VERSION 5.8 ;
BUSBITCHARS "[]" ;
DIVIDERCHAR "/" ;
UNITS
    DATABASE MICRONS 1000 ;
END UNITS

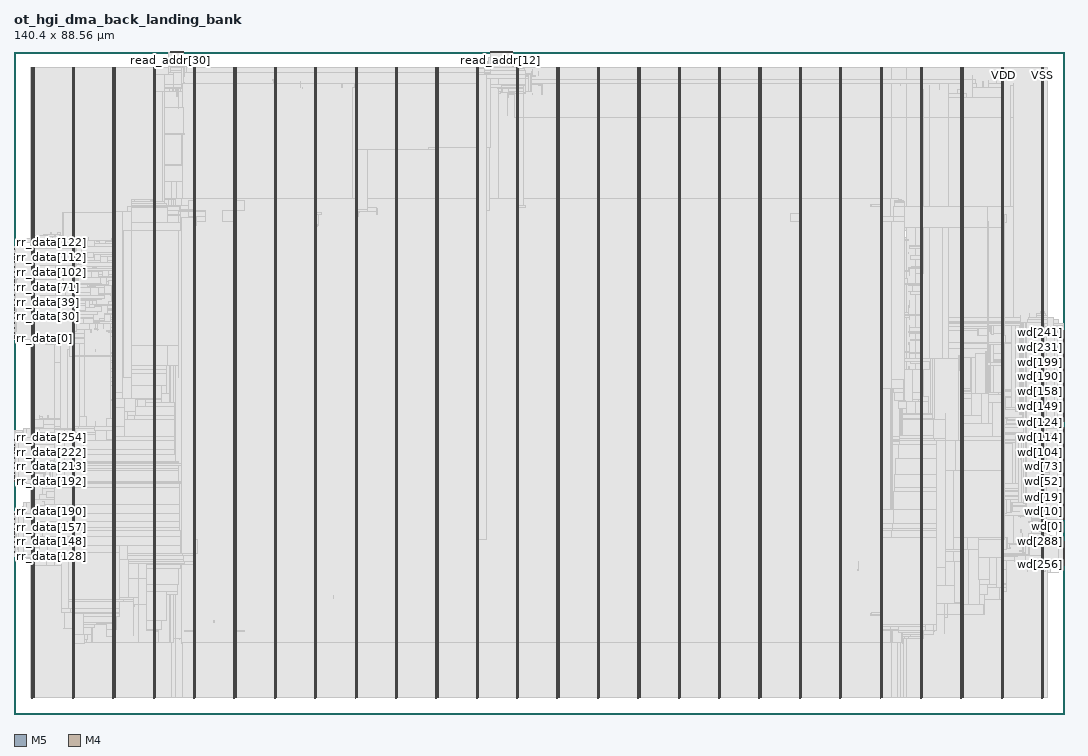
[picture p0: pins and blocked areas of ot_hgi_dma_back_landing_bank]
MACRO ot_hgi_dma_back_landing_bank
  FOREIGN ot_hgi_dma_back_landing_bank 0 0 ;
  CLASS BLOCK ;
  SIZE 140.4 BY 88.56 ;
  PIN clk
    DIRECTION INPUT ;
    USE SIGNAL ;
    PORT
      LAYER M5 ;
        RECT  63.696 88.476 63.72 88.56 ;
    END
  END clk
  PIN output_en
    DIRECTION INPUT ;
    USE SIGNAL ;
    PORT
      LAYER M5 ;
        RECT  63.792 88.476 63.816 88.56 ;
    END
  END output_en
  PIN read_addr[0]
    DIRECTION INPUT ;
    USE SIGNAL ;
    PORT
      LAYER M5 ;
        RECT  63.888 88.476 63.912 88.56 ;
    END
  END read_addr[0]
  PIN read_addr[10]
    DIRECTION INPUT ;
    USE SIGNAL ;
    PORT
      LAYER M5 ;
        RECT  64.848 88.476 64.872 88.56 ;
    END
  END read_addr[10]
  PIN read_addr[11]
    DIRECTION INPUT ;
    USE SIGNAL ;
    PORT
      LAYER M5 ;
        RECT  64.944 88.476 64.968 88.56 ;
    END
  END read_addr[11]
  PIN read_addr[12]
    DIRECTION INPUT ;
    USE SIGNAL ;
    PORT
      LAYER M5 ;
        RECT  65.04 88.476 65.064 88.56 ;
    END
  END read_addr[12]
  PIN read_addr[13]
    DIRECTION INPUT ;
    USE SIGNAL ;
    PORT
      LAYER M5 ;
        RECT  65.136 88.476 65.16 88.56 ;
    END
  END read_addr[13]
  PIN read_addr[14]
    DIRECTION INPUT ;
    USE SIGNAL ;
    PORT
      LAYER M5 ;
        RECT  65.232 88.476 65.256 88.56 ;
    END
  END read_addr[14]
  PIN read_addr[15]
    DIRECTION INPUT ;
    USE SIGNAL ;
    PORT
      LAYER M5 ;
        RECT  65.328 88.476 65.352 88.56 ;
    END
  END read_addr[15]
  PIN read_addr[16]
    DIRECTION INPUT ;
    USE SIGNAL ;
    PORT
      LAYER M5 ;
        RECT  65.424 88.476 65.448 88.56 ;
    END
  END read_addr[16]
  PIN read_addr[17]
    DIRECTION INPUT ;
    USE SIGNAL ;
    PORT
      LAYER M5 ;
        RECT  65.52 88.476 65.544 88.56 ;
    END
  END read_addr[17]
  PIN read_addr[18]
    DIRECTION INPUT ;
    USE SIGNAL ;
    PORT
      LAYER M5 ;
        RECT  65.616 88.476 65.64 88.56 ;
    END
  END read_addr[18]
  PIN read_addr[19]
    DIRECTION INPUT ;
    USE SIGNAL ;
    PORT
      LAYER M5 ;
        RECT  65.712 88.476 65.736 88.56 ;
    END
  END read_addr[19]
  PIN read_addr[1]
    DIRECTION INPUT ;
    USE SIGNAL ;
    PORT
      LAYER M5 ;
        RECT  63.984 88.476 64.008 88.56 ;
    END
  END read_addr[1]
  PIN read_addr[20]
    DIRECTION INPUT ;
    USE SIGNAL ;
    PORT
      LAYER M5 ;
        RECT  65.808 88.476 65.832 88.56 ;
    END
  END read_addr[20]
  PIN read_addr[21]
    DIRECTION INPUT ;
    USE SIGNAL ;
    PORT
      LAYER M5 ;
        RECT  65.904 88.476 65.928 88.56 ;
    END
  END read_addr[21]
  PIN read_addr[22]
    DIRECTION INPUT ;
    USE SIGNAL ;
    PORT
      LAYER M5 ;
        RECT  66 88.476 66.024 88.56 ;
    END
  END read_addr[22]
  PIN read_addr[23]
    DIRECTION INPUT ;
    USE SIGNAL ;
    PORT
      LAYER M5 ;
        RECT  66.096 88.476 66.12 88.56 ;
    END
  END read_addr[23]
  PIN read_addr[24]
    DIRECTION INPUT ;
    USE SIGNAL ;
    PORT
      LAYER M5 ;
        RECT  66.192 88.476 66.216 88.56 ;
    END
  END read_addr[24]
  PIN read_addr[25]
    DIRECTION INPUT ;
    USE SIGNAL ;
    PORT
      LAYER M5 ;
        RECT  66.288 88.476 66.312 88.56 ;
    END
  END read_addr[25]
  PIN read_addr[26]
    DIRECTION INPUT ;
    USE SIGNAL ;
    PORT
      LAYER M5 ;
        RECT  66.384 88.476 66.408 88.56 ;
    END
  END read_addr[26]
  PIN read_addr[27]
    DIRECTION INPUT ;
    USE SIGNAL ;
    PORT
      LAYER M5 ;
        RECT  66.48 88.476 66.504 88.56 ;
    END
  END read_addr[27]
  PIN read_addr[28]
    DIRECTION INPUT ;
    USE SIGNAL ;
    PORT
      LAYER M5 ;
        RECT  66.576 88.476 66.6 88.56 ;
    END
  END read_addr[28]
  PIN read_addr[29]
    DIRECTION INPUT ;
    USE SIGNAL ;
    PORT
      LAYER M5 ;
        RECT  66.672 88.476 66.696 88.56 ;
    END
  END read_addr[29]
  PIN read_addr[2]
    DIRECTION INPUT ;
    USE SIGNAL ;
    PORT
      LAYER M5 ;
        RECT  64.08 88.476 64.104 88.56 ;
    END
  END read_addr[2]
  PIN read_addr[30]
    DIRECTION INPUT ;
    USE SIGNAL ;
    PORT
      LAYER M5 ;
        RECT  20.88 88.476 20.904 88.56 ;
    END
  END read_addr[30]
  PIN read_addr[31]
    DIRECTION INPUT ;
    USE SIGNAL ;
    PORT
      LAYER M5 ;
        RECT  20.976 88.476 21 88.56 ;
    END
  END read_addr[31]
  PIN read_addr[3]
    DIRECTION INPUT ;
    USE SIGNAL ;
    PORT
      LAYER M5 ;
        RECT  64.176 88.476 64.2 88.56 ;
    END
  END read_addr[3]
  PIN read_addr[4]
    DIRECTION INPUT ;
    USE SIGNAL ;
    PORT
      LAYER M5 ;
        RECT  64.272 88.476 64.296 88.56 ;
    END
  END read_addr[4]
  PIN read_addr[5]
    DIRECTION INPUT ;
    USE SIGNAL ;
    PORT
      LAYER M5 ;
        RECT  64.368 88.476 64.392 88.56 ;
    END
  END read_addr[5]
  PIN read_addr[6]
    DIRECTION INPUT ;
    USE SIGNAL ;
    PORT
      LAYER M5 ;
        RECT  64.464 88.476 64.488 88.56 ;
    END
  END read_addr[6]
  PIN read_addr[7]
    DIRECTION INPUT ;
    USE SIGNAL ;
    PORT
      LAYER M5 ;
        RECT  64.56 88.476 64.584 88.56 ;
    END
  END read_addr[7]
  PIN read_addr[8]
    DIRECTION INPUT ;
    USE SIGNAL ;
    PORT
      LAYER M5 ;
        RECT  64.656 88.476 64.68 88.56 ;
    END
  END read_addr[8]
  PIN read_addr[9]
    DIRECTION INPUT ;
    USE SIGNAL ;
    PORT
      LAYER M5 ;
        RECT  64.752 88.476 64.776 88.56 ;
    END
  END read_addr[9]
  PIN read_en
    DIRECTION INPUT ;
    USE SIGNAL ;
    PORT
      LAYER M5 ;
        RECT  21.072 88.476 21.096 88.56 ;
    END
  END read_en
  PIN read_slot[0]
    DIRECTION INPUT ;
    USE SIGNAL ;
    PORT
      LAYER M5 ;
        RECT  21.168 88.476 21.192 88.56 ;
    END
  END read_slot[0]
  PIN read_slot[1]
    DIRECTION INPUT ;
    USE SIGNAL ;
    PORT
      LAYER M5 ;
        RECT  21.264 88.476 21.288 88.56 ;
    END
  END read_slot[1]
  PIN read_slot[2]
    DIRECTION INPUT ;
    USE SIGNAL ;
    PORT
      LAYER M5 ;
        RECT  21.36 88.476 21.384 88.56 ;
    END
  END read_slot[2]
  PIN read_slot[3]
    DIRECTION INPUT ;
    USE SIGNAL ;
    PORT
      LAYER M5 ;
        RECT  21.456 88.476 21.48 88.56 ;
    END
  END read_slot[3]
  PIN read_slot[4]
    DIRECTION INPUT ;
    USE SIGNAL ;
    PORT
      LAYER M5 ;
        RECT  21.552 88.476 21.576 88.56 ;
    END
  END read_slot[4]
  PIN read_slot[5]
    DIRECTION INPUT ;
    USE SIGNAL ;
    PORT
      LAYER M5 ;
        RECT  21.648 88.476 21.672 88.56 ;
    END
  END read_slot[5]
  PIN read_slot[6]
    DIRECTION INPUT ;
    USE SIGNAL ;
    PORT
      LAYER M5 ;
        RECT  21.744 88.476 21.768 88.56 ;
    END
  END read_slot[6]
  PIN rr_data[0]
    DIRECTION INPUT ;
    USE SIGNAL ;
    PORT
      LAYER M4 ;
        RECT  0 50.256 0.084 50.28 ;
    END
  END rr_data[0]
  PIN rr_data[100]
    DIRECTION INPUT ;
    USE SIGNAL ;
    PORT
      LAYER M4 ;
        RECT  0 59.856 0.084 59.88 ;
    END
  END rr_data[100]
  PIN rr_data[101]
    DIRECTION INPUT ;
    USE SIGNAL ;
    PORT
      LAYER M4 ;
        RECT  0 59.952 0.084 59.976 ;
    END
  END rr_data[101]
  PIN rr_data[102]
    DIRECTION INPUT ;
    USE SIGNAL ;
    PORT
      LAYER M4 ;
        RECT  0 60.048 0.084 60.072 ;
    END
  END rr_data[102]
  PIN rr_data[103]
    DIRECTION INPUT ;
    USE SIGNAL ;
    PORT
      LAYER M4 ;
        RECT  0 60.144 0.084 60.168 ;
    END
  END rr_data[103]
  PIN rr_data[104]
    DIRECTION INPUT ;
    USE SIGNAL ;
    PORT
      LAYER M4 ;
        RECT  0 60.24 0.084 60.264 ;
    END
  END rr_data[104]
  PIN rr_data[105]
    DIRECTION INPUT ;
    USE SIGNAL ;
    PORT
      LAYER M4 ;
        RECT  0 60.336 0.084 60.36 ;
    END
  END rr_data[105]
  PIN rr_data[106]
    DIRECTION INPUT ;
    USE SIGNAL ;
    PORT
      LAYER M4 ;
        RECT  0 60.432 0.084 60.456 ;
    END
  END rr_data[106]
  PIN rr_data[107]
    DIRECTION INPUT ;
    USE SIGNAL ;
    PORT
      LAYER M4 ;
        RECT  0 60.528 0.084 60.552 ;
    END
  END rr_data[107]
  PIN rr_data[108]
    DIRECTION INPUT ;
    USE SIGNAL ;
    PORT
      LAYER M4 ;
        RECT  0 60.624 0.084 60.648 ;
    END
  END rr_data[108]
  PIN rr_data[109]
    DIRECTION INPUT ;
    USE SIGNAL ;
    PORT
      LAYER M4 ;
        RECT  0 60.72 0.084 60.744 ;
    END
  END rr_data[109]
  PIN rr_data[10]
    DIRECTION INPUT ;
    USE SIGNAL ;
    PORT
      LAYER M4 ;
        RECT  0 51.216 0.084 51.24 ;
    END
  END rr_data[10]
  PIN rr_data[110]
    DIRECTION INPUT ;
    USE SIGNAL ;
    PORT
      LAYER M4 ;
        RECT  0 60.816 0.084 60.84 ;
    END
  END rr_data[110]
  PIN rr_data[111]
    DIRECTION INPUT ;
    USE SIGNAL ;
    PORT
      LAYER M4 ;
        RECT  0 60.912 0.084 60.936 ;
    END
  END rr_data[111]
  PIN rr_data[112]
    DIRECTION INPUT ;
    USE SIGNAL ;
    PORT
      LAYER M4 ;
        RECT  0 61.008 0.084 61.032 ;
    END
  END rr_data[112]
  PIN rr_data[113]
    DIRECTION INPUT ;
    USE SIGNAL ;
    PORT
      LAYER M4 ;
        RECT  0 61.104 0.084 61.128 ;
    END
  END rr_data[113]
  PIN rr_data[114]
    DIRECTION INPUT ;
    USE SIGNAL ;
    PORT
      LAYER M4 ;
        RECT  0 61.2 0.084 61.224 ;
    END
  END rr_data[114]
  PIN rr_data[115]
    DIRECTION INPUT ;
    USE SIGNAL ;
    PORT
      LAYER M4 ;
        RECT  0 61.296 0.084 61.32 ;
    END
  END rr_data[115]
  PIN rr_data[116]
    DIRECTION INPUT ;
    USE SIGNAL ;
    PORT
      LAYER M4 ;
        RECT  0 61.392 0.084 61.416 ;
    END
  END rr_data[116]
  PIN rr_data[117]
    DIRECTION INPUT ;
    USE SIGNAL ;
    PORT
      LAYER M4 ;
        RECT  0 61.488 0.084 61.512 ;
    END
  END rr_data[117]
  PIN rr_data[118]
    DIRECTION INPUT ;
    USE SIGNAL ;
    PORT
      LAYER M4 ;
        RECT  0 61.584 0.084 61.608 ;
    END
  END rr_data[118]
  PIN rr_data[119]
    DIRECTION INPUT ;
    USE SIGNAL ;
    PORT
      LAYER M4 ;
        RECT  0 61.68 0.084 61.704 ;
    END
  END rr_data[119]
  PIN rr_data[11]
    DIRECTION INPUT ;
    USE SIGNAL ;
    PORT
      LAYER M4 ;
        RECT  0 51.312 0.084 51.336 ;
    END
  END rr_data[11]
  PIN rr_data[120]
    DIRECTION INPUT ;
    USE SIGNAL ;
    PORT
      LAYER M4 ;
        RECT  0 61.776 0.084 61.8 ;
    END
  END rr_data[120]
  PIN rr_data[121]
    DIRECTION INPUT ;
    USE SIGNAL ;
    PORT
      LAYER M4 ;
        RECT  0 61.872 0.084 61.896 ;
    END
  END rr_data[121]
  PIN rr_data[122]
    DIRECTION INPUT ;
    USE SIGNAL ;
    PORT
      LAYER M4 ;
        RECT  0 61.968 0.084 61.992 ;
    END
  END rr_data[122]
  PIN rr_data[123]
    DIRECTION INPUT ;
    USE SIGNAL ;
    PORT
      LAYER M4 ;
        RECT  0 62.064 0.084 62.088 ;
    END
  END rr_data[123]
  PIN rr_data[124]
    DIRECTION INPUT ;
    USE SIGNAL ;
    PORT
      LAYER M4 ;
        RECT  0 62.16 0.084 62.184 ;
    END
  END rr_data[124]
  PIN rr_data[125]
    DIRECTION INPUT ;
    USE SIGNAL ;
    PORT
      LAYER M4 ;
        RECT  0 62.256 0.084 62.28 ;
    END
  END rr_data[125]
  PIN rr_data[126]
    DIRECTION INPUT ;
    USE SIGNAL ;
    PORT
      LAYER M4 ;
        RECT  0 62.352 0.084 62.376 ;
    END
  END rr_data[126]
  PIN rr_data[127]
    DIRECTION INPUT ;
    USE SIGNAL ;
    PORT
      LAYER M4 ;
        RECT  0 62.448 0.084 62.472 ;
    END
  END rr_data[127]
  PIN rr_data[128]
    DIRECTION INPUT ;
    USE SIGNAL ;
    PORT
      LAYER M4 ;
        RECT  0 21.072 0.084 21.096 ;
    END
  END rr_data[128]
  PIN rr_data[129]
    DIRECTION INPUT ;
    USE SIGNAL ;
    PORT
      LAYER M4 ;
        RECT  0 21.168 0.084 21.192 ;
    END
  END rr_data[129]
  PIN rr_data[12]
    DIRECTION INPUT ;
    USE SIGNAL ;
    PORT
      LAYER M4 ;
        RECT  0 51.408 0.084 51.432 ;
    END
  END rr_data[12]
  PIN rr_data[130]
    DIRECTION INPUT ;
    USE SIGNAL ;
    PORT
      LAYER M4 ;
        RECT  0 21.264 0.084 21.288 ;
    END
  END rr_data[130]
  PIN rr_data[131]
    DIRECTION INPUT ;
    USE SIGNAL ;
    PORT
      LAYER M4 ;
        RECT  0 21.36 0.084 21.384 ;
    END
  END rr_data[131]
  PIN rr_data[132]
    DIRECTION INPUT ;
    USE SIGNAL ;
    PORT
      LAYER M4 ;
        RECT  0 21.456 0.084 21.48 ;
    END
  END rr_data[132]
  PIN rr_data[133]
    DIRECTION INPUT ;
    USE SIGNAL ;
    PORT
      LAYER M4 ;
        RECT  0 21.552 0.084 21.576 ;
    END
  END rr_data[133]
  PIN rr_data[134]
    DIRECTION INPUT ;
    USE SIGNAL ;
    PORT
      LAYER M4 ;
        RECT  0 21.648 0.084 21.672 ;
    END
  END rr_data[134]
  PIN rr_data[135]
    DIRECTION INPUT ;
    USE SIGNAL ;
    PORT
      LAYER M4 ;
        RECT  0 21.744 0.084 21.768 ;
    END
  END rr_data[135]
  PIN rr_data[136]
    DIRECTION INPUT ;
    USE SIGNAL ;
    PORT
      LAYER M4 ;
        RECT  0 21.84 0.084 21.864 ;
    END
  END rr_data[136]
  PIN rr_data[137]
    DIRECTION INPUT ;
    USE SIGNAL ;
    PORT
      LAYER M4 ;
        RECT  0 21.936 0.084 21.96 ;
    END
  END rr_data[137]
  PIN rr_data[138]
    DIRECTION INPUT ;
    USE SIGNAL ;
    PORT
      LAYER M4 ;
        RECT  0 22.032 0.084 22.056 ;
    END
  END rr_data[138]
  PIN rr_data[139]
    DIRECTION INPUT ;
    USE SIGNAL ;
    PORT
      LAYER M4 ;
        RECT  0 22.128 0.084 22.152 ;
    END
  END rr_data[139]
  PIN rr_data[13]
    DIRECTION INPUT ;
    USE SIGNAL ;
    PORT
      LAYER M4 ;
        RECT  0 51.504 0.084 51.528 ;
    END
  END rr_data[13]
  PIN rr_data[140]
    DIRECTION INPUT ;
    USE SIGNAL ;
    PORT
      LAYER M4 ;
        RECT  0 22.224 0.084 22.248 ;
    END
  END rr_data[140]
  PIN rr_data[141]
    DIRECTION INPUT ;
    USE SIGNAL ;
    PORT
      LAYER M4 ;
        RECT  0 22.32 0.084 22.344 ;
    END
  END rr_data[141]
  PIN rr_data[142]
    DIRECTION INPUT ;
    USE SIGNAL ;
    PORT
      LAYER M4 ;
        RECT  0 22.416 0.084 22.44 ;
    END
  END rr_data[142]
  PIN rr_data[143]
    DIRECTION INPUT ;
    USE SIGNAL ;
    PORT
      LAYER M4 ;
        RECT  0 22.512 0.084 22.536 ;
    END
  END rr_data[143]
  PIN rr_data[144]
    DIRECTION INPUT ;
    USE SIGNAL ;
    PORT
      LAYER M4 ;
        RECT  0 22.608 0.084 22.632 ;
    END
  END rr_data[144]
  PIN rr_data[145]
    DIRECTION INPUT ;
    USE SIGNAL ;
    PORT
      LAYER M4 ;
        RECT  0 22.704 0.084 22.728 ;
    END
  END rr_data[145]
  PIN rr_data[146]
    DIRECTION INPUT ;
    USE SIGNAL ;
    PORT
      LAYER M4 ;
        RECT  0 22.8 0.084 22.824 ;
    END
  END rr_data[146]
  PIN rr_data[147]
    DIRECTION INPUT ;
    USE SIGNAL ;
    PORT
      LAYER M4 ;
        RECT  0 22.896 0.084 22.92 ;
    END
  END rr_data[147]
  PIN rr_data[148]
    DIRECTION INPUT ;
    USE SIGNAL ;
    PORT
      LAYER M4 ;
        RECT  0 22.992 0.084 23.016 ;
    END
  END rr_data[148]
  PIN rr_data[149]
    DIRECTION INPUT ;
    USE SIGNAL ;
    PORT
      LAYER M4 ;
        RECT  0 23.088 0.084 23.112 ;
    END
  END rr_data[149]
  PIN rr_data[14]
    DIRECTION INPUT ;
    USE SIGNAL ;
    PORT
      LAYER M4 ;
        RECT  0 51.6 0.084 51.624 ;
    END
  END rr_data[14]
  PIN rr_data[150]
    DIRECTION INPUT ;
    USE SIGNAL ;
    PORT
      LAYER M4 ;
        RECT  0 23.184 0.084 23.208 ;
    END
  END rr_data[150]
  PIN rr_data[151]
    DIRECTION INPUT ;
    USE SIGNAL ;
    PORT
      LAYER M4 ;
        RECT  0 23.28 0.084 23.304 ;
    END
  END rr_data[151]
  PIN rr_data[152]
    DIRECTION INPUT ;
    USE SIGNAL ;
    PORT
      LAYER M4 ;
        RECT  0 23.376 0.084 23.4 ;
    END
  END rr_data[152]
  PIN rr_data[153]
    DIRECTION INPUT ;
    USE SIGNAL ;
    PORT
      LAYER M4 ;
        RECT  0 23.472 0.084 23.496 ;
    END
  END rr_data[153]
  PIN rr_data[154]
    DIRECTION INPUT ;
    USE SIGNAL ;
    PORT
      LAYER M4 ;
        RECT  0 23.568 0.084 23.592 ;
    END
  END rr_data[154]
  PIN rr_data[155]
    DIRECTION INPUT ;
    USE SIGNAL ;
    PORT
      LAYER M4 ;
        RECT  0 23.664 0.084 23.688 ;
    END
  END rr_data[155]
  PIN rr_data[156]
    DIRECTION INPUT ;
    USE SIGNAL ;
    PORT
      LAYER M4 ;
        RECT  0 23.76 0.084 23.784 ;
    END
  END rr_data[156]
  PIN rr_data[157]
    DIRECTION INPUT ;
    USE SIGNAL ;
    PORT
      LAYER M4 ;
        RECT  0 23.856 0.084 23.88 ;
    END
  END rr_data[157]
  PIN rr_data[158]
    DIRECTION INPUT ;
    USE SIGNAL ;
    PORT
      LAYER M4 ;
        RECT  0 23.952 0.084 23.976 ;
    END
  END rr_data[158]
  PIN rr_data[159]
    DIRECTION INPUT ;
    USE SIGNAL ;
    PORT
      LAYER M4 ;
        RECT  0 24.048 0.084 24.072 ;
    END
  END rr_data[159]
  PIN rr_data[15]
    DIRECTION INPUT ;
    USE SIGNAL ;
    PORT
      LAYER M4 ;
        RECT  0 51.696 0.084 51.72 ;
    END
  END rr_data[15]
  PIN rr_data[160]
    DIRECTION INPUT ;
    USE SIGNAL ;
    PORT
      LAYER M4 ;
        RECT  0 24.144 0.084 24.168 ;
    END
  END rr_data[160]
  PIN rr_data[161]
    DIRECTION INPUT ;
    USE SIGNAL ;
    PORT
      LAYER M4 ;
        RECT  0 24.24 0.084 24.264 ;
    END
  END rr_data[161]
  PIN rr_data[162]
    DIRECTION INPUT ;
    USE SIGNAL ;
    PORT
      LAYER M4 ;
        RECT  0 24.336 0.084 24.36 ;
    END
  END rr_data[162]
  PIN rr_data[163]
    DIRECTION INPUT ;
    USE SIGNAL ;
    PORT
      LAYER M4 ;
        RECT  0 24.432 0.084 24.456 ;
    END
  END rr_data[163]
  PIN rr_data[164]
    DIRECTION INPUT ;
    USE SIGNAL ;
    PORT
      LAYER M4 ;
        RECT  0 24.528 0.084 24.552 ;
    END
  END rr_data[164]
  PIN rr_data[165]
    DIRECTION INPUT ;
    USE SIGNAL ;
    PORT
      LAYER M4 ;
        RECT  0 24.624 0.084 24.648 ;
    END
  END rr_data[165]
  PIN rr_data[166]
    DIRECTION INPUT ;
    USE SIGNAL ;
    PORT
      LAYER M4 ;
        RECT  0 24.72 0.084 24.744 ;
    END
  END rr_data[166]
  PIN rr_data[167]
    DIRECTION INPUT ;
    USE SIGNAL ;
    PORT
      LAYER M4 ;
        RECT  0 24.816 0.084 24.84 ;
    END
  END rr_data[167]
  PIN rr_data[168]
    DIRECTION INPUT ;
    USE SIGNAL ;
    PORT
      LAYER M4 ;
        RECT  0 24.912 0.084 24.936 ;
    END
  END rr_data[168]
  PIN rr_data[169]
    DIRECTION INPUT ;
    USE SIGNAL ;
    PORT
      LAYER M4 ;
        RECT  0 25.008 0.084 25.032 ;
    END
  END rr_data[169]
  PIN rr_data[16]
    DIRECTION INPUT ;
    USE SIGNAL ;
    PORT
      LAYER M4 ;
        RECT  0 51.792 0.084 51.816 ;
    END
  END rr_data[16]
  PIN rr_data[170]
    DIRECTION INPUT ;
    USE SIGNAL ;
    PORT
      LAYER M4 ;
        RECT  0 25.104 0.084 25.128 ;
    END
  END rr_data[170]
  PIN rr_data[171]
    DIRECTION INPUT ;
    USE SIGNAL ;
    PORT
      LAYER M4 ;
        RECT  0 25.2 0.084 25.224 ;
    END
  END rr_data[171]
  PIN rr_data[172]
    DIRECTION INPUT ;
    USE SIGNAL ;
    PORT
      LAYER M4 ;
        RECT  0 25.296 0.084 25.32 ;
    END
  END rr_data[172]
  PIN rr_data[173]
    DIRECTION INPUT ;
    USE SIGNAL ;
    PORT
      LAYER M4 ;
        RECT  0 25.392 0.084 25.416 ;
    END
  END rr_data[173]
  PIN rr_data[174]
    DIRECTION INPUT ;
    USE SIGNAL ;
    PORT
      LAYER M4 ;
        RECT  0 25.488 0.084 25.512 ;
    END
  END rr_data[174]
  PIN rr_data[175]
    DIRECTION INPUT ;
    USE SIGNAL ;
    PORT
      LAYER M4 ;
        RECT  0 25.584 0.084 25.608 ;
    END
  END rr_data[175]
  PIN rr_data[176]
    DIRECTION INPUT ;
    USE SIGNAL ;
    PORT
      LAYER M4 ;
        RECT  0 25.68 0.084 25.704 ;
    END
  END rr_data[176]
  PIN rr_data[177]
    DIRECTION INPUT ;
    USE SIGNAL ;
    PORT
      LAYER M4 ;
        RECT  0 25.776 0.084 25.8 ;
    END
  END rr_data[177]
  PIN rr_data[178]
    DIRECTION INPUT ;
    USE SIGNAL ;
    PORT
      LAYER M4 ;
        RECT  0 25.872 0.084 25.896 ;
    END
  END rr_data[178]
  PIN rr_data[179]
    DIRECTION INPUT ;
    USE SIGNAL ;
    PORT
      LAYER M4 ;
        RECT  0 25.968 0.084 25.992 ;
    END
  END rr_data[179]
  PIN rr_data[17]
    DIRECTION INPUT ;
    USE SIGNAL ;
    PORT
      LAYER M4 ;
        RECT  0 51.888 0.084 51.912 ;
    END
  END rr_data[17]
  PIN rr_data[180]
    DIRECTION INPUT ;
    USE SIGNAL ;
    PORT
      LAYER M4 ;
        RECT  0 26.064 0.084 26.088 ;
    END
  END rr_data[180]
  PIN rr_data[181]
    DIRECTION INPUT ;
    USE SIGNAL ;
    PORT
      LAYER M4 ;
        RECT  0 26.16 0.084 26.184 ;
    END
  END rr_data[181]
  PIN rr_data[182]
    DIRECTION INPUT ;
    USE SIGNAL ;
    PORT
      LAYER M4 ;
        RECT  0 26.256 0.084 26.28 ;
    END
  END rr_data[182]
  PIN rr_data[183]
    DIRECTION INPUT ;
    USE SIGNAL ;
    PORT
      LAYER M4 ;
        RECT  0 26.352 0.084 26.376 ;
    END
  END rr_data[183]
  PIN rr_data[184]
    DIRECTION INPUT ;
    USE SIGNAL ;
    PORT
      LAYER M4 ;
        RECT  0 26.448 0.084 26.472 ;
    END
  END rr_data[184]
  PIN rr_data[185]
    DIRECTION INPUT ;
    USE SIGNAL ;
    PORT
      LAYER M4 ;
        RECT  0 26.544 0.084 26.568 ;
    END
  END rr_data[185]
  PIN rr_data[186]
    DIRECTION INPUT ;
    USE SIGNAL ;
    PORT
      LAYER M4 ;
        RECT  0 26.64 0.084 26.664 ;
    END
  END rr_data[186]
  PIN rr_data[187]
    DIRECTION INPUT ;
    USE SIGNAL ;
    PORT
      LAYER M4 ;
        RECT  0 26.736 0.084 26.76 ;
    END
  END rr_data[187]
  PIN rr_data[188]
    DIRECTION INPUT ;
    USE SIGNAL ;
    PORT
      LAYER M4 ;
        RECT  0 26.832 0.084 26.856 ;
    END
  END rr_data[188]
  PIN rr_data[189]
    DIRECTION INPUT ;
    USE SIGNAL ;
    PORT
      LAYER M4 ;
        RECT  0 26.928 0.084 26.952 ;
    END
  END rr_data[189]
  PIN rr_data[18]
    DIRECTION INPUT ;
    USE SIGNAL ;
    PORT
      LAYER M4 ;
        RECT  0 51.984 0.084 52.008 ;
    END
  END rr_data[18]
  PIN rr_data[190]
    DIRECTION INPUT ;
    USE SIGNAL ;
    PORT
      LAYER M4 ;
        RECT  0 27.024 0.084 27.048 ;
    END
  END rr_data[190]
  PIN rr_data[191]
    DIRECTION INPUT ;
    USE SIGNAL ;
    PORT
      LAYER M4 ;
        RECT  0 27.12 0.084 27.144 ;
    END
  END rr_data[191]
  PIN rr_data[192]
    DIRECTION INPUT ;
    USE SIGNAL ;
    PORT
      LAYER M4 ;
        RECT  0 31.056 0.084 31.08 ;
    END
  END rr_data[192]
  PIN rr_data[193]
    DIRECTION INPUT ;
    USE SIGNAL ;
    PORT
      LAYER M4 ;
        RECT  0 31.152 0.084 31.176 ;
    END
  END rr_data[193]
  PIN rr_data[194]
    DIRECTION INPUT ;
    USE SIGNAL ;
    PORT
      LAYER M4 ;
        RECT  0 31.248 0.084 31.272 ;
    END
  END rr_data[194]
  PIN rr_data[195]
    DIRECTION INPUT ;
    USE SIGNAL ;
    PORT
      LAYER M4 ;
        RECT  0 31.344 0.084 31.368 ;
    END
  END rr_data[195]
  PIN rr_data[196]
    DIRECTION INPUT ;
    USE SIGNAL ;
    PORT
      LAYER M4 ;
        RECT  0 31.44 0.084 31.464 ;
    END
  END rr_data[196]
  PIN rr_data[197]
    DIRECTION INPUT ;
    USE SIGNAL ;
    PORT
      LAYER M4 ;
        RECT  0 31.536 0.084 31.56 ;
    END
  END rr_data[197]
  PIN rr_data[198]
    DIRECTION INPUT ;
    USE SIGNAL ;
    PORT
      LAYER M4 ;
        RECT  0 31.632 0.084 31.656 ;
    END
  END rr_data[198]
  PIN rr_data[199]
    DIRECTION INPUT ;
    USE SIGNAL ;
    PORT
      LAYER M4 ;
        RECT  0 31.728 0.084 31.752 ;
    END
  END rr_data[199]
  PIN rr_data[19]
    DIRECTION INPUT ;
    USE SIGNAL ;
    PORT
      LAYER M4 ;
        RECT  0 52.08 0.084 52.104 ;
    END
  END rr_data[19]
  PIN rr_data[1]
    DIRECTION INPUT ;
    USE SIGNAL ;
    PORT
      LAYER M4 ;
        RECT  0 50.352 0.084 50.376 ;
    END
  END rr_data[1]
  PIN rr_data[200]
    DIRECTION INPUT ;
    USE SIGNAL ;
    PORT
      LAYER M4 ;
        RECT  0 31.824 0.084 31.848 ;
    END
  END rr_data[200]
  PIN rr_data[201]
    DIRECTION INPUT ;
    USE SIGNAL ;
    PORT
      LAYER M4 ;
        RECT  0 31.92 0.084 31.944 ;
    END
  END rr_data[201]
  PIN rr_data[202]
    DIRECTION INPUT ;
    USE SIGNAL ;
    PORT
      LAYER M4 ;
        RECT  0 32.016 0.084 32.04 ;
    END
  END rr_data[202]
  PIN rr_data[203]
    DIRECTION INPUT ;
    USE SIGNAL ;
    PORT
      LAYER M4 ;
        RECT  0 32.112 0.084 32.136 ;
    END
  END rr_data[203]
  PIN rr_data[204]
    DIRECTION INPUT ;
    USE SIGNAL ;
    PORT
      LAYER M4 ;
        RECT  0 32.208 0.084 32.232 ;
    END
  END rr_data[204]
  PIN rr_data[205]
    DIRECTION INPUT ;
    USE SIGNAL ;
    PORT
      LAYER M4 ;
        RECT  0 32.304 0.084 32.328 ;
    END
  END rr_data[205]
  PIN rr_data[206]
    DIRECTION INPUT ;
    USE SIGNAL ;
    PORT
      LAYER M4 ;
        RECT  0 32.4 0.084 32.424 ;
    END
  END rr_data[206]
  PIN rr_data[207]
    DIRECTION INPUT ;
    USE SIGNAL ;
    PORT
      LAYER M4 ;
        RECT  0 32.496 0.084 32.52 ;
    END
  END rr_data[207]
  PIN rr_data[208]
    DIRECTION INPUT ;
    USE SIGNAL ;
    PORT
      LAYER M4 ;
        RECT  0 32.592 0.084 32.616 ;
    END
  END rr_data[208]
  PIN rr_data[209]
    DIRECTION INPUT ;
    USE SIGNAL ;
    PORT
      LAYER M4 ;
        RECT  0 32.688 0.084 32.712 ;
    END
  END rr_data[209]
  PIN rr_data[20]
    DIRECTION INPUT ;
    USE SIGNAL ;
    PORT
      LAYER M4 ;
        RECT  0 52.176 0.084 52.2 ;
    END
  END rr_data[20]
  PIN rr_data[210]
    DIRECTION INPUT ;
    USE SIGNAL ;
    PORT
      LAYER M4 ;
        RECT  0 32.784 0.084 32.808 ;
    END
  END rr_data[210]
  PIN rr_data[211]
    DIRECTION INPUT ;
    USE SIGNAL ;
    PORT
      LAYER M4 ;
        RECT  0 32.88 0.084 32.904 ;
    END
  END rr_data[211]
  PIN rr_data[212]
    DIRECTION INPUT ;
    USE SIGNAL ;
    PORT
      LAYER M4 ;
        RECT  0 32.976 0.084 33 ;
    END
  END rr_data[212]
  PIN rr_data[213]
    DIRECTION INPUT ;
    USE SIGNAL ;
    PORT
      LAYER M4 ;
        RECT  0 33.072 0.084 33.096 ;
    END
  END rr_data[213]
  PIN rr_data[214]
    DIRECTION INPUT ;
    USE SIGNAL ;
    PORT
      LAYER M4 ;
        RECT  0 33.168 0.084 33.192 ;
    END
  END rr_data[214]
  PIN rr_data[215]
    DIRECTION INPUT ;
    USE SIGNAL ;
    PORT
      LAYER M4 ;
        RECT  0 33.264 0.084 33.288 ;
    END
  END rr_data[215]
  PIN rr_data[216]
    DIRECTION INPUT ;
    USE SIGNAL ;
    PORT
      LAYER M4 ;
        RECT  0 33.36 0.084 33.384 ;
    END
  END rr_data[216]
  PIN rr_data[217]
    DIRECTION INPUT ;
    USE SIGNAL ;
    PORT
      LAYER M4 ;
        RECT  0 33.456 0.084 33.48 ;
    END
  END rr_data[217]
  PIN rr_data[218]
    DIRECTION INPUT ;
    USE SIGNAL ;
    PORT
      LAYER M4 ;
        RECT  0 33.552 0.084 33.576 ;
    END
  END rr_data[218]
  PIN rr_data[219]
    DIRECTION INPUT ;
    USE SIGNAL ;
    PORT
      LAYER M4 ;
        RECT  0 33.648 0.084 33.672 ;
    END
  END rr_data[219]
  PIN rr_data[21]
    DIRECTION INPUT ;
    USE SIGNAL ;
    PORT
      LAYER M4 ;
        RECT  0 52.272 0.084 52.296 ;
    END
  END rr_data[21]
  PIN rr_data[220]
    DIRECTION INPUT ;
    USE SIGNAL ;
    PORT
      LAYER M4 ;
        RECT  0 33.744 0.084 33.768 ;
    END
  END rr_data[220]
  PIN rr_data[221]
    DIRECTION INPUT ;
    USE SIGNAL ;
    PORT
      LAYER M4 ;
        RECT  0 33.84 0.084 33.864 ;
    END
  END rr_data[221]
  PIN rr_data[222]
    DIRECTION INPUT ;
    USE SIGNAL ;
    PORT
      LAYER M4 ;
        RECT  0 33.936 0.084 33.96 ;
    END
  END rr_data[222]
  PIN rr_data[223]
    DIRECTION INPUT ;
    USE SIGNAL ;
    PORT
      LAYER M4 ;
        RECT  0 34.032 0.084 34.056 ;
    END
  END rr_data[223]
  PIN rr_data[224]
    DIRECTION INPUT ;
    USE SIGNAL ;
    PORT
      LAYER M4 ;
        RECT  0 34.128 0.084 34.152 ;
    END
  END rr_data[224]
  PIN rr_data[225]
    DIRECTION INPUT ;
    USE SIGNAL ;
    PORT
      LAYER M4 ;
        RECT  0 34.224 0.084 34.248 ;
    END
  END rr_data[225]
  PIN rr_data[226]
    DIRECTION INPUT ;
    USE SIGNAL ;
    PORT
      LAYER M4 ;
        RECT  0 34.32 0.084 34.344 ;
    END
  END rr_data[226]
  PIN rr_data[227]
    DIRECTION INPUT ;
    USE SIGNAL ;
    PORT
      LAYER M4 ;
        RECT  0 34.416 0.084 34.44 ;
    END
  END rr_data[227]
  PIN rr_data[228]
    DIRECTION INPUT ;
    USE SIGNAL ;
    PORT
      LAYER M4 ;
        RECT  0 34.512 0.084 34.536 ;
    END
  END rr_data[228]
  PIN rr_data[229]
    DIRECTION INPUT ;
    USE SIGNAL ;
    PORT
      LAYER M4 ;
        RECT  0 34.608 0.084 34.632 ;
    END
  END rr_data[229]
  PIN rr_data[22]
    DIRECTION INPUT ;
    USE SIGNAL ;
    PORT
      LAYER M4 ;
        RECT  0 52.368 0.084 52.392 ;
    END
  END rr_data[22]
  PIN rr_data[230]
    DIRECTION INPUT ;
    USE SIGNAL ;
    PORT
      LAYER M4 ;
        RECT  0 34.704 0.084 34.728 ;
    END
  END rr_data[230]
  PIN rr_data[231]
    DIRECTION INPUT ;
    USE SIGNAL ;
    PORT
      LAYER M4 ;
        RECT  0 34.8 0.084 34.824 ;
    END
  END rr_data[231]
  PIN rr_data[232]
    DIRECTION INPUT ;
    USE SIGNAL ;
    PORT
      LAYER M4 ;
        RECT  0 34.896 0.084 34.92 ;
    END
  END rr_data[232]
  PIN rr_data[233]
    DIRECTION INPUT ;
    USE SIGNAL ;
    PORT
      LAYER M4 ;
        RECT  0 34.992 0.084 35.016 ;
    END
  END rr_data[233]
  PIN rr_data[234]
    DIRECTION INPUT ;
    USE SIGNAL ;
    PORT
      LAYER M4 ;
        RECT  0 35.088 0.084 35.112 ;
    END
  END rr_data[234]
  PIN rr_data[235]
    DIRECTION INPUT ;
    USE SIGNAL ;
    PORT
      LAYER M4 ;
        RECT  0 35.184 0.084 35.208 ;
    END
  END rr_data[235]
  PIN rr_data[236]
    DIRECTION INPUT ;
    USE SIGNAL ;
    PORT
      LAYER M4 ;
        RECT  0 35.28 0.084 35.304 ;
    END
  END rr_data[236]
  PIN rr_data[237]
    DIRECTION INPUT ;
    USE SIGNAL ;
    PORT
      LAYER M4 ;
        RECT  0 35.376 0.084 35.4 ;
    END
  END rr_data[237]
  PIN rr_data[238]
    DIRECTION INPUT ;
    USE SIGNAL ;
    PORT
      LAYER M4 ;
        RECT  0 35.472 0.084 35.496 ;
    END
  END rr_data[238]
  PIN rr_data[239]
    DIRECTION INPUT ;
    USE SIGNAL ;
    PORT
      LAYER M4 ;
        RECT  0 35.568 0.084 35.592 ;
    END
  END rr_data[239]
  PIN rr_data[23]
    DIRECTION INPUT ;
    USE SIGNAL ;
    PORT
      LAYER M4 ;
        RECT  0 52.464 0.084 52.488 ;
    END
  END rr_data[23]
  PIN rr_data[240]
    DIRECTION INPUT ;
    USE SIGNAL ;
    PORT
      LAYER M4 ;
        RECT  0 35.664 0.084 35.688 ;
    END
  END rr_data[240]
  PIN rr_data[241]
    DIRECTION INPUT ;
    USE SIGNAL ;
    PORT
      LAYER M4 ;
        RECT  0 35.76 0.084 35.784 ;
    END
  END rr_data[241]
  PIN rr_data[242]
    DIRECTION INPUT ;
    USE SIGNAL ;
    PORT
      LAYER M4 ;
        RECT  0 35.856 0.084 35.88 ;
    END
  END rr_data[242]
  PIN rr_data[243]
    DIRECTION INPUT ;
    USE SIGNAL ;
    PORT
      LAYER M4 ;
        RECT  0 35.952 0.084 35.976 ;
    END
  END rr_data[243]
  PIN rr_data[244]
    DIRECTION INPUT ;
    USE SIGNAL ;
    PORT
      LAYER M4 ;
        RECT  0 36.048 0.084 36.072 ;
    END
  END rr_data[244]
  PIN rr_data[245]
    DIRECTION INPUT ;
    USE SIGNAL ;
    PORT
      LAYER M4 ;
        RECT  0 36.144 0.084 36.168 ;
    END
  END rr_data[245]
  PIN rr_data[246]
    DIRECTION INPUT ;
    USE SIGNAL ;
    PORT
      LAYER M4 ;
        RECT  0 36.24 0.084 36.264 ;
    END
  END rr_data[246]
  PIN rr_data[247]
    DIRECTION INPUT ;
    USE SIGNAL ;
    PORT
      LAYER M4 ;
        RECT  0 36.336 0.084 36.36 ;
    END
  END rr_data[247]
  PIN rr_data[248]
    DIRECTION INPUT ;
    USE SIGNAL ;
    PORT
      LAYER M4 ;
        RECT  0 36.432 0.084 36.456 ;
    END
  END rr_data[248]
  PIN rr_data[249]
    DIRECTION INPUT ;
    USE SIGNAL ;
    PORT
      LAYER M4 ;
        RECT  0 36.528 0.084 36.552 ;
    END
  END rr_data[249]
  PIN rr_data[24]
    DIRECTION INPUT ;
    USE SIGNAL ;
    PORT
      LAYER M4 ;
        RECT  0 52.56 0.084 52.584 ;
    END
  END rr_data[24]
  PIN rr_data[250]
    DIRECTION INPUT ;
    USE SIGNAL ;
    PORT
      LAYER M4 ;
        RECT  0 36.624 0.084 36.648 ;
    END
  END rr_data[250]
  PIN rr_data[251]
    DIRECTION INPUT ;
    USE SIGNAL ;
    PORT
      LAYER M4 ;
        RECT  0 36.72 0.084 36.744 ;
    END
  END rr_data[251]
  PIN rr_data[252]
    DIRECTION INPUT ;
    USE SIGNAL ;
    PORT
      LAYER M4 ;
        RECT  0 36.816 0.084 36.84 ;
    END
  END rr_data[252]
  PIN rr_data[253]
    DIRECTION INPUT ;
    USE SIGNAL ;
    PORT
      LAYER M4 ;
        RECT  0 36.912 0.084 36.936 ;
    END
  END rr_data[253]
  PIN rr_data[254]
    DIRECTION INPUT ;
    USE SIGNAL ;
    PORT
      LAYER M4 ;
        RECT  0 37.008 0.084 37.032 ;
    END
  END rr_data[254]
  PIN rr_data[255]
    DIRECTION INPUT ;
    USE SIGNAL ;
    PORT
      LAYER M4 ;
        RECT  0 37.104 0.084 37.128 ;
    END
  END rr_data[255]
  PIN rr_data[25]
    DIRECTION INPUT ;
    USE SIGNAL ;
    PORT
      LAYER M4 ;
        RECT  0 52.656 0.084 52.68 ;
    END
  END rr_data[25]
  PIN rr_data[26]
    DIRECTION INPUT ;
    USE SIGNAL ;
    PORT
      LAYER M4 ;
        RECT  0 52.752 0.084 52.776 ;
    END
  END rr_data[26]
  PIN rr_data[27]
    DIRECTION INPUT ;
    USE SIGNAL ;
    PORT
      LAYER M4 ;
        RECT  0 52.848 0.084 52.872 ;
    END
  END rr_data[27]
  PIN rr_data[28]
    DIRECTION INPUT ;
    USE SIGNAL ;
    PORT
      LAYER M4 ;
        RECT  0 52.944 0.084 52.968 ;
    END
  END rr_data[28]
  PIN rr_data[29]
    DIRECTION INPUT ;
    USE SIGNAL ;
    PORT
      LAYER M4 ;
        RECT  0 53.04 0.084 53.064 ;
    END
  END rr_data[29]
  PIN rr_data[2]
    DIRECTION INPUT ;
    USE SIGNAL ;
    PORT
      LAYER M4 ;
        RECT  0 50.448 0.084 50.472 ;
    END
  END rr_data[2]
  PIN rr_data[30]
    DIRECTION INPUT ;
    USE SIGNAL ;
    PORT
      LAYER M4 ;
        RECT  0 53.136 0.084 53.16 ;
    END
  END rr_data[30]
  PIN rr_data[31]
    DIRECTION INPUT ;
    USE SIGNAL ;
    PORT
      LAYER M4 ;
        RECT  0 53.232 0.084 53.256 ;
    END
  END rr_data[31]
  PIN rr_data[32]
    DIRECTION INPUT ;
    USE SIGNAL ;
    PORT
      LAYER M4 ;
        RECT  0 53.328 0.084 53.352 ;
    END
  END rr_data[32]
  PIN rr_data[33]
    DIRECTION INPUT ;
    USE SIGNAL ;
    PORT
      LAYER M4 ;
        RECT  0 53.424 0.084 53.448 ;
    END
  END rr_data[33]
  PIN rr_data[34]
    DIRECTION INPUT ;
    USE SIGNAL ;
    PORT
      LAYER M4 ;
        RECT  0 53.52 0.084 53.544 ;
    END
  END rr_data[34]
  PIN rr_data[35]
    DIRECTION INPUT ;
    USE SIGNAL ;
    PORT
      LAYER M4 ;
        RECT  0 53.616 0.084 53.64 ;
    END
  END rr_data[35]
  PIN rr_data[36]
    DIRECTION INPUT ;
    USE SIGNAL ;
    PORT
      LAYER M4 ;
        RECT  0 53.712 0.084 53.736 ;
    END
  END rr_data[36]
  PIN rr_data[37]
    DIRECTION INPUT ;
    USE SIGNAL ;
    PORT
      LAYER M4 ;
        RECT  0 53.808 0.084 53.832 ;
    END
  END rr_data[37]
  PIN rr_data[38]
    DIRECTION INPUT ;
    USE SIGNAL ;
    PORT
      LAYER M4 ;
        RECT  0 53.904 0.084 53.928 ;
    END
  END rr_data[38]
  PIN rr_data[39]
    DIRECTION INPUT ;
    USE SIGNAL ;
    PORT
      LAYER M4 ;
        RECT  0 54 0.084 54.024 ;
    END
  END rr_data[39]
  PIN rr_data[3]
    DIRECTION INPUT ;
    USE SIGNAL ;
    PORT
      LAYER M4 ;
        RECT  0 50.544 0.084 50.568 ;
    END
  END rr_data[3]
  PIN rr_data[40]
    DIRECTION INPUT ;
    USE SIGNAL ;
    PORT
      LAYER M4 ;
        RECT  0 54.096 0.084 54.12 ;
    END
  END rr_data[40]
  PIN rr_data[41]
    DIRECTION INPUT ;
    USE SIGNAL ;
    PORT
      LAYER M4 ;
        RECT  0 54.192 0.084 54.216 ;
    END
  END rr_data[41]
  PIN rr_data[42]
    DIRECTION INPUT ;
    USE SIGNAL ;
    PORT
      LAYER M4 ;
        RECT  0 54.288 0.084 54.312 ;
    END
  END rr_data[42]
  PIN rr_data[43]
    DIRECTION INPUT ;
    USE SIGNAL ;
    PORT
      LAYER M4 ;
        RECT  0 54.384 0.084 54.408 ;
    END
  END rr_data[43]
  PIN rr_data[44]
    DIRECTION INPUT ;
    USE SIGNAL ;
    PORT
      LAYER M4 ;
        RECT  0 54.48 0.084 54.504 ;
    END
  END rr_data[44]
  PIN rr_data[45]
    DIRECTION INPUT ;
    USE SIGNAL ;
    PORT
      LAYER M4 ;
        RECT  0 54.576 0.084 54.6 ;
    END
  END rr_data[45]
  PIN rr_data[46]
    DIRECTION INPUT ;
    USE SIGNAL ;
    PORT
      LAYER M4 ;
        RECT  0 54.672 0.084 54.696 ;
    END
  END rr_data[46]
  PIN rr_data[47]
    DIRECTION INPUT ;
    USE SIGNAL ;
    PORT
      LAYER M4 ;
        RECT  0 54.768 0.084 54.792 ;
    END
  END rr_data[47]
  PIN rr_data[48]
    DIRECTION INPUT ;
    USE SIGNAL ;
    PORT
      LAYER M4 ;
        RECT  0 54.864 0.084 54.888 ;
    END
  END rr_data[48]
  PIN rr_data[49]
    DIRECTION INPUT ;
    USE SIGNAL ;
    PORT
      LAYER M4 ;
        RECT  0 54.96 0.084 54.984 ;
    END
  END rr_data[49]
  PIN rr_data[4]
    DIRECTION INPUT ;
    USE SIGNAL ;
    PORT
      LAYER M4 ;
        RECT  0 50.64 0.084 50.664 ;
    END
  END rr_data[4]
  PIN rr_data[50]
    DIRECTION INPUT ;
    USE SIGNAL ;
    PORT
      LAYER M4 ;
        RECT  0 55.056 0.084 55.08 ;
    END
  END rr_data[50]
  PIN rr_data[51]
    DIRECTION INPUT ;
    USE SIGNAL ;
    PORT
      LAYER M4 ;
        RECT  0 55.152 0.084 55.176 ;
    END
  END rr_data[51]
  PIN rr_data[52]
    DIRECTION INPUT ;
    USE SIGNAL ;
    PORT
      LAYER M4 ;
        RECT  0 55.248 0.084 55.272 ;
    END
  END rr_data[52]
  PIN rr_data[53]
    DIRECTION INPUT ;
    USE SIGNAL ;
    PORT
      LAYER M4 ;
        RECT  0 55.344 0.084 55.368 ;
    END
  END rr_data[53]
  PIN rr_data[54]
    DIRECTION INPUT ;
    USE SIGNAL ;
    PORT
      LAYER M4 ;
        RECT  0 55.44 0.084 55.464 ;
    END
  END rr_data[54]
  PIN rr_data[55]
    DIRECTION INPUT ;
    USE SIGNAL ;
    PORT
      LAYER M4 ;
        RECT  0 55.536 0.084 55.56 ;
    END
  END rr_data[55]
  PIN rr_data[56]
    DIRECTION INPUT ;
    USE SIGNAL ;
    PORT
      LAYER M4 ;
        RECT  0 55.632 0.084 55.656 ;
    END
  END rr_data[56]
  PIN rr_data[57]
    DIRECTION INPUT ;
    USE SIGNAL ;
    PORT
      LAYER M4 ;
        RECT  0 55.728 0.084 55.752 ;
    END
  END rr_data[57]
  PIN rr_data[58]
    DIRECTION INPUT ;
    USE SIGNAL ;
    PORT
      LAYER M4 ;
        RECT  0 55.824 0.084 55.848 ;
    END
  END rr_data[58]
  PIN rr_data[59]
    DIRECTION INPUT ;
    USE SIGNAL ;
    PORT
      LAYER M4 ;
        RECT  0 55.92 0.084 55.944 ;
    END
  END rr_data[59]
  PIN rr_data[5]
    DIRECTION INPUT ;
    USE SIGNAL ;
    PORT
      LAYER M4 ;
        RECT  0 50.736 0.084 50.76 ;
    END
  END rr_data[5]
  PIN rr_data[60]
    DIRECTION INPUT ;
    USE SIGNAL ;
    PORT
      LAYER M4 ;
        RECT  0 56.016 0.084 56.04 ;
    END
  END rr_data[60]
  PIN rr_data[61]
    DIRECTION INPUT ;
    USE SIGNAL ;
    PORT
      LAYER M4 ;
        RECT  0 56.112 0.084 56.136 ;
    END
  END rr_data[61]
  PIN rr_data[62]
    DIRECTION INPUT ;
    USE SIGNAL ;
    PORT
      LAYER M4 ;
        RECT  0 56.208 0.084 56.232 ;
    END
  END rr_data[62]
  PIN rr_data[63]
    DIRECTION INPUT ;
    USE SIGNAL ;
    PORT
      LAYER M4 ;
        RECT  0 56.304 0.084 56.328 ;
    END
  END rr_data[63]
  PIN rr_data[64]
    DIRECTION INPUT ;
    USE SIGNAL ;
    PORT
      LAYER M4 ;
        RECT  0 56.4 0.084 56.424 ;
    END
  END rr_data[64]
  PIN rr_data[65]
    DIRECTION INPUT ;
    USE SIGNAL ;
    PORT
      LAYER M4 ;
        RECT  0 56.496 0.084 56.52 ;
    END
  END rr_data[65]
  PIN rr_data[66]
    DIRECTION INPUT ;
    USE SIGNAL ;
    PORT
      LAYER M4 ;
        RECT  0 56.592 0.084 56.616 ;
    END
  END rr_data[66]
  PIN rr_data[67]
    DIRECTION INPUT ;
    USE SIGNAL ;
    PORT
      LAYER M4 ;
        RECT  0 56.688 0.084 56.712 ;
    END
  END rr_data[67]
  PIN rr_data[68]
    DIRECTION INPUT ;
    USE SIGNAL ;
    PORT
      LAYER M4 ;
        RECT  0 56.784 0.084 56.808 ;
    END
  END rr_data[68]
  PIN rr_data[69]
    DIRECTION INPUT ;
    USE SIGNAL ;
    PORT
      LAYER M4 ;
        RECT  0 56.88 0.084 56.904 ;
    END
  END rr_data[69]
  PIN rr_data[6]
    DIRECTION INPUT ;
    USE SIGNAL ;
    PORT
      LAYER M4 ;
        RECT  0 50.832 0.084 50.856 ;
    END
  END rr_data[6]
  PIN rr_data[70]
    DIRECTION INPUT ;
    USE SIGNAL ;
    PORT
      LAYER M4 ;
        RECT  0 56.976 0.084 57 ;
    END
  END rr_data[70]
  PIN rr_data[71]
    DIRECTION INPUT ;
    USE SIGNAL ;
    PORT
      LAYER M4 ;
        RECT  0 57.072 0.084 57.096 ;
    END
  END rr_data[71]
  PIN rr_data[72]
    DIRECTION INPUT ;
    USE SIGNAL ;
    PORT
      LAYER M4 ;
        RECT  0 57.168 0.084 57.192 ;
    END
  END rr_data[72]
  PIN rr_data[73]
    DIRECTION INPUT ;
    USE SIGNAL ;
    PORT
      LAYER M4 ;
        RECT  0 57.264 0.084 57.288 ;
    END
  END rr_data[73]
  PIN rr_data[74]
    DIRECTION INPUT ;
    USE SIGNAL ;
    PORT
      LAYER M4 ;
        RECT  0 57.36 0.084 57.384 ;
    END
  END rr_data[74]
  PIN rr_data[75]
    DIRECTION INPUT ;
    USE SIGNAL ;
    PORT
      LAYER M4 ;
        RECT  0 57.456 0.084 57.48 ;
    END
  END rr_data[75]
  PIN rr_data[76]
    DIRECTION INPUT ;
    USE SIGNAL ;
    PORT
      LAYER M4 ;
        RECT  0 57.552 0.084 57.576 ;
    END
  END rr_data[76]
  PIN rr_data[77]
    DIRECTION INPUT ;
    USE SIGNAL ;
    PORT
      LAYER M4 ;
        RECT  0 57.648 0.084 57.672 ;
    END
  END rr_data[77]
  PIN rr_data[78]
    DIRECTION INPUT ;
    USE SIGNAL ;
    PORT
      LAYER M4 ;
        RECT  0 57.744 0.084 57.768 ;
    END
  END rr_data[78]
  PIN rr_data[79]
    DIRECTION INPUT ;
    USE SIGNAL ;
    PORT
      LAYER M4 ;
        RECT  0 57.84 0.084 57.864 ;
    END
  END rr_data[79]
  PIN rr_data[7]
    DIRECTION INPUT ;
    USE SIGNAL ;
    PORT
      LAYER M4 ;
        RECT  0 50.928 0.084 50.952 ;
    END
  END rr_data[7]
  PIN rr_data[80]
    DIRECTION INPUT ;
    USE SIGNAL ;
    PORT
      LAYER M4 ;
        RECT  0 57.936 0.084 57.96 ;
    END
  END rr_data[80]
  PIN rr_data[81]
    DIRECTION INPUT ;
    USE SIGNAL ;
    PORT
      LAYER M4 ;
        RECT  0 58.032 0.084 58.056 ;
    END
  END rr_data[81]
  PIN rr_data[82]
    DIRECTION INPUT ;
    USE SIGNAL ;
    PORT
      LAYER M4 ;
        RECT  0 58.128 0.084 58.152 ;
    END
  END rr_data[82]
  PIN rr_data[83]
    DIRECTION INPUT ;
    USE SIGNAL ;
    PORT
      LAYER M4 ;
        RECT  0 58.224 0.084 58.248 ;
    END
  END rr_data[83]
  PIN rr_data[84]
    DIRECTION INPUT ;
    USE SIGNAL ;
    PORT
      LAYER M4 ;
        RECT  0 58.32 0.084 58.344 ;
    END
  END rr_data[84]
  PIN rr_data[85]
    DIRECTION INPUT ;
    USE SIGNAL ;
    PORT
      LAYER M4 ;
        RECT  0 58.416 0.084 58.44 ;
    END
  END rr_data[85]
  PIN rr_data[86]
    DIRECTION INPUT ;
    USE SIGNAL ;
    PORT
      LAYER M4 ;
        RECT  0 58.512 0.084 58.536 ;
    END
  END rr_data[86]
  PIN rr_data[87]
    DIRECTION INPUT ;
    USE SIGNAL ;
    PORT
      LAYER M4 ;
        RECT  0 58.608 0.084 58.632 ;
    END
  END rr_data[87]
  PIN rr_data[88]
    DIRECTION INPUT ;
    USE SIGNAL ;
    PORT
      LAYER M4 ;
        RECT  0 58.704 0.084 58.728 ;
    END
  END rr_data[88]
  PIN rr_data[89]
    DIRECTION INPUT ;
    USE SIGNAL ;
    PORT
      LAYER M4 ;
        RECT  0 58.8 0.084 58.824 ;
    END
  END rr_data[89]
  PIN rr_data[8]
    DIRECTION INPUT ;
    USE SIGNAL ;
    PORT
      LAYER M4 ;
        RECT  0 51.024 0.084 51.048 ;
    END
  END rr_data[8]
  PIN rr_data[90]
    DIRECTION INPUT ;
    USE SIGNAL ;
    PORT
      LAYER M4 ;
        RECT  0 58.896 0.084 58.92 ;
    END
  END rr_data[90]
  PIN rr_data[91]
    DIRECTION INPUT ;
    USE SIGNAL ;
    PORT
      LAYER M4 ;
        RECT  0 58.992 0.084 59.016 ;
    END
  END rr_data[91]
  PIN rr_data[92]
    DIRECTION INPUT ;
    USE SIGNAL ;
    PORT
      LAYER M4 ;
        RECT  0 59.088 0.084 59.112 ;
    END
  END rr_data[92]
  PIN rr_data[93]
    DIRECTION INPUT ;
    USE SIGNAL ;
    PORT
      LAYER M4 ;
        RECT  0 59.184 0.084 59.208 ;
    END
  END rr_data[93]
  PIN rr_data[94]
    DIRECTION INPUT ;
    USE SIGNAL ;
    PORT
      LAYER M4 ;
        RECT  0 59.28 0.084 59.304 ;
    END
  END rr_data[94]
  PIN rr_data[95]
    DIRECTION INPUT ;
    USE SIGNAL ;
    PORT
      LAYER M4 ;
        RECT  0 59.376 0.084 59.4 ;
    END
  END rr_data[95]
  PIN rr_data[96]
    DIRECTION INPUT ;
    USE SIGNAL ;
    PORT
      LAYER M4 ;
        RECT  0 59.472 0.084 59.496 ;
    END
  END rr_data[96]
  PIN rr_data[97]
    DIRECTION INPUT ;
    USE SIGNAL ;
    PORT
      LAYER M4 ;
        RECT  0 59.568 0.084 59.592 ;
    END
  END rr_data[97]
  PIN rr_data[98]
    DIRECTION INPUT ;
    USE SIGNAL ;
    PORT
      LAYER M4 ;
        RECT  0 59.664 0.084 59.688 ;
    END
  END rr_data[98]
  PIN rr_data[99]
    DIRECTION INPUT ;
    USE SIGNAL ;
    PORT
      LAYER M4 ;
        RECT  0 59.76 0.084 59.784 ;
    END
  END rr_data[99]
  PIN rr_data[9]
    DIRECTION INPUT ;
    USE SIGNAL ;
    PORT
      LAYER M4 ;
        RECT  0 51.12 0.084 51.144 ;
    END
  END rr_data[9]
  PIN rst_n
    DIRECTION INPUT ;
    USE SIGNAL ;
    PORT
      LAYER M5 ;
        RECT  21.84 88.476 21.864 88.56 ;
    END
  END rst_n
  PIN wd[0]
    DIRECTION OUTPUT ;
    USE SIGNAL ;
    PORT
      LAYER M4 ;
        RECT  140.316 26.064 140.4 26.088 ;
    END
  END wd[0]
  PIN wd[100]
    DIRECTION OUTPUT ;
    USE SIGNAL ;
    PORT
      LAYER M4 ;
        RECT  140.316 35.664 140.4 35.688 ;
    END
  END wd[100]
  PIN wd[101]
    DIRECTION OUTPUT ;
    USE SIGNAL ;
    PORT
      LAYER M4 ;
        RECT  140.316 35.76 140.4 35.784 ;
    END
  END wd[101]
  PIN wd[102]
    DIRECTION OUTPUT ;
    USE SIGNAL ;
    PORT
      LAYER M4 ;
        RECT  140.316 35.856 140.4 35.88 ;
    END
  END wd[102]
  PIN wd[103]
    DIRECTION OUTPUT ;
    USE SIGNAL ;
    PORT
      LAYER M4 ;
        RECT  140.316 35.952 140.4 35.976 ;
    END
  END wd[103]
  PIN wd[104]
    DIRECTION OUTPUT ;
    USE SIGNAL ;
    PORT
      LAYER M4 ;
        RECT  140.316 36.048 140.4 36.072 ;
    END
  END wd[104]
  PIN wd[105]
    DIRECTION OUTPUT ;
    USE SIGNAL ;
    PORT
      LAYER M4 ;
        RECT  140.316 36.144 140.4 36.168 ;
    END
  END wd[105]
  PIN wd[106]
    DIRECTION OUTPUT ;
    USE SIGNAL ;
    PORT
      LAYER M4 ;
        RECT  140.316 36.24 140.4 36.264 ;
    END
  END wd[106]
  PIN wd[107]
    DIRECTION OUTPUT ;
    USE SIGNAL ;
    PORT
      LAYER M4 ;
        RECT  140.316 36.336 140.4 36.36 ;
    END
  END wd[107]
  PIN wd[108]
    DIRECTION OUTPUT ;
    USE SIGNAL ;
    PORT
      LAYER M4 ;
        RECT  140.316 36.432 140.4 36.456 ;
    END
  END wd[108]
  PIN wd[109]
    DIRECTION OUTPUT ;
    USE SIGNAL ;
    PORT
      LAYER M4 ;
        RECT  140.316 36.528 140.4 36.552 ;
    END
  END wd[109]
  PIN wd[10]
    DIRECTION OUTPUT ;
    USE SIGNAL ;
    PORT
      LAYER M4 ;
        RECT  140.316 27.024 140.4 27.048 ;
    END
  END wd[10]
  PIN wd[110]
    DIRECTION OUTPUT ;
    USE SIGNAL ;
    PORT
      LAYER M4 ;
        RECT  140.316 36.624 140.4 36.648 ;
    END
  END wd[110]
  PIN wd[111]
    DIRECTION OUTPUT ;
    USE SIGNAL ;
    PORT
      LAYER M4 ;
        RECT  140.316 36.72 140.4 36.744 ;
    END
  END wd[111]
  PIN wd[112]
    DIRECTION OUTPUT ;
    USE SIGNAL ;
    PORT
      LAYER M4 ;
        RECT  140.316 36.816 140.4 36.84 ;
    END
  END wd[112]
  PIN wd[113]
    DIRECTION OUTPUT ;
    USE SIGNAL ;
    PORT
      LAYER M4 ;
        RECT  140.316 36.912 140.4 36.936 ;
    END
  END wd[113]
  PIN wd[114]
    DIRECTION OUTPUT ;
    USE SIGNAL ;
    PORT
      LAYER M4 ;
        RECT  140.316 37.008 140.4 37.032 ;
    END
  END wd[114]
  PIN wd[115]
    DIRECTION OUTPUT ;
    USE SIGNAL ;
    PORT
      LAYER M4 ;
        RECT  140.316 37.104 140.4 37.128 ;
    END
  END wd[115]
  PIN wd[116]
    DIRECTION OUTPUT ;
    USE SIGNAL ;
    PORT
      LAYER M4 ;
        RECT  140.316 37.2 140.4 37.224 ;
    END
  END wd[116]
  PIN wd[117]
    DIRECTION OUTPUT ;
    USE SIGNAL ;
    PORT
      LAYER M4 ;
        RECT  140.316 37.296 140.4 37.32 ;
    END
  END wd[117]
  PIN wd[118]
    DIRECTION OUTPUT ;
    USE SIGNAL ;
    PORT
      LAYER M4 ;
        RECT  140.316 37.392 140.4 37.416 ;
    END
  END wd[118]
  PIN wd[119]
    DIRECTION OUTPUT ;
    USE SIGNAL ;
    PORT
      LAYER M4 ;
        RECT  140.316 37.488 140.4 37.512 ;
    END
  END wd[119]
  PIN wd[11]
    DIRECTION OUTPUT ;
    USE SIGNAL ;
    PORT
      LAYER M4 ;
        RECT  140.316 27.12 140.4 27.144 ;
    END
  END wd[11]
  PIN wd[120]
    DIRECTION OUTPUT ;
    USE SIGNAL ;
    PORT
      LAYER M4 ;
        RECT  140.316 37.584 140.4 37.608 ;
    END
  END wd[120]
  PIN wd[121]
    DIRECTION OUTPUT ;
    USE SIGNAL ;
    PORT
      LAYER M4 ;
        RECT  140.316 37.68 140.4 37.704 ;
    END
  END wd[121]
  PIN wd[122]
    DIRECTION OUTPUT ;
    USE SIGNAL ;
    PORT
      LAYER M4 ;
        RECT  140.316 37.776 140.4 37.8 ;
    END
  END wd[122]
  PIN wd[123]
    DIRECTION OUTPUT ;
    USE SIGNAL ;
    PORT
      LAYER M4 ;
        RECT  140.316 37.872 140.4 37.896 ;
    END
  END wd[123]
  PIN wd[124]
    DIRECTION OUTPUT ;
    USE SIGNAL ;
    PORT
      LAYER M4 ;
        RECT  140.316 37.968 140.4 37.992 ;
    END
  END wd[124]
  PIN wd[125]
    DIRECTION OUTPUT ;
    USE SIGNAL ;
    PORT
      LAYER M4 ;
        RECT  140.316 38.064 140.4 38.088 ;
    END
  END wd[125]
  PIN wd[126]
    DIRECTION OUTPUT ;
    USE SIGNAL ;
    PORT
      LAYER M4 ;
        RECT  140.316 38.16 140.4 38.184 ;
    END
  END wd[126]
  PIN wd[127]
    DIRECTION OUTPUT ;
    USE SIGNAL ;
    PORT
      LAYER M4 ;
        RECT  140.316 38.256 140.4 38.28 ;
    END
  END wd[127]
  PIN wd[128]
    DIRECTION OUTPUT ;
    USE SIGNAL ;
    PORT
      LAYER M4 ;
        RECT  140.316 39.12 140.4 39.144 ;
    END
  END wd[128]
  PIN wd[129]
    DIRECTION OUTPUT ;
    USE SIGNAL ;
    PORT
      LAYER M4 ;
        RECT  140.316 39.216 140.4 39.24 ;
    END
  END wd[129]
  PIN wd[12]
    DIRECTION OUTPUT ;
    USE SIGNAL ;
    PORT
      LAYER M4 ;
        RECT  140.316 27.216 140.4 27.24 ;
    END
  END wd[12]
  PIN wd[130]
    DIRECTION OUTPUT ;
    USE SIGNAL ;
    PORT
      LAYER M4 ;
        RECT  140.316 39.312 140.4 39.336 ;
    END
  END wd[130]
  PIN wd[131]
    DIRECTION OUTPUT ;
    USE SIGNAL ;
    PORT
      LAYER M4 ;
        RECT  140.316 39.408 140.4 39.432 ;
    END
  END wd[131]
  PIN wd[132]
    DIRECTION OUTPUT ;
    USE SIGNAL ;
    PORT
      LAYER M4 ;
        RECT  140.316 39.504 140.4 39.528 ;
    END
  END wd[132]
  PIN wd[133]
    DIRECTION OUTPUT ;
    USE SIGNAL ;
    PORT
      LAYER M4 ;
        RECT  140.316 39.6 140.4 39.624 ;
    END
  END wd[133]
  PIN wd[134]
    DIRECTION OUTPUT ;
    USE SIGNAL ;
    PORT
      LAYER M4 ;
        RECT  140.316 39.696 140.4 39.72 ;
    END
  END wd[134]
  PIN wd[135]
    DIRECTION OUTPUT ;
    USE SIGNAL ;
    PORT
      LAYER M4 ;
        RECT  140.316 39.792 140.4 39.816 ;
    END
  END wd[135]
  PIN wd[136]
    DIRECTION OUTPUT ;
    USE SIGNAL ;
    PORT
      LAYER M4 ;
        RECT  140.316 39.888 140.4 39.912 ;
    END
  END wd[136]
  PIN wd[137]
    DIRECTION OUTPUT ;
    USE SIGNAL ;
    PORT
      LAYER M4 ;
        RECT  140.316 39.984 140.4 40.008 ;
    END
  END wd[137]
  PIN wd[138]
    DIRECTION OUTPUT ;
    USE SIGNAL ;
    PORT
      LAYER M4 ;
        RECT  140.316 40.08 140.4 40.104 ;
    END
  END wd[138]
  PIN wd[139]
    DIRECTION OUTPUT ;
    USE SIGNAL ;
    PORT
      LAYER M4 ;
        RECT  140.316 40.176 140.4 40.2 ;
    END
  END wd[139]
  PIN wd[13]
    DIRECTION OUTPUT ;
    USE SIGNAL ;
    PORT
      LAYER M4 ;
        RECT  140.316 27.312 140.4 27.336 ;
    END
  END wd[13]
  PIN wd[140]
    DIRECTION OUTPUT ;
    USE SIGNAL ;
    PORT
      LAYER M4 ;
        RECT  140.316 40.272 140.4 40.296 ;
    END
  END wd[140]
  PIN wd[141]
    DIRECTION OUTPUT ;
    USE SIGNAL ;
    PORT
      LAYER M4 ;
        RECT  140.316 40.368 140.4 40.392 ;
    END
  END wd[141]
  PIN wd[142]
    DIRECTION OUTPUT ;
    USE SIGNAL ;
    PORT
      LAYER M4 ;
        RECT  140.316 40.464 140.4 40.488 ;
    END
  END wd[142]
  PIN wd[143]
    DIRECTION OUTPUT ;
    USE SIGNAL ;
    PORT
      LAYER M4 ;
        RECT  140.316 40.56 140.4 40.584 ;
    END
  END wd[143]
  PIN wd[144]
    DIRECTION OUTPUT ;
    USE SIGNAL ;
    PORT
      LAYER M4 ;
        RECT  140.316 40.656 140.4 40.68 ;
    END
  END wd[144]
  PIN wd[145]
    DIRECTION OUTPUT ;
    USE SIGNAL ;
    PORT
      LAYER M4 ;
        RECT  140.316 40.752 140.4 40.776 ;
    END
  END wd[145]
  PIN wd[146]
    DIRECTION OUTPUT ;
    USE SIGNAL ;
    PORT
      LAYER M4 ;
        RECT  140.316 40.848 140.4 40.872 ;
    END
  END wd[146]
  PIN wd[147]
    DIRECTION OUTPUT ;
    USE SIGNAL ;
    PORT
      LAYER M4 ;
        RECT  140.316 40.944 140.4 40.968 ;
    END
  END wd[147]
  PIN wd[148]
    DIRECTION OUTPUT ;
    USE SIGNAL ;
    PORT
      LAYER M4 ;
        RECT  140.316 41.04 140.4 41.064 ;
    END
  END wd[148]
  PIN wd[149]
    DIRECTION OUTPUT ;
    USE SIGNAL ;
    PORT
      LAYER M4 ;
        RECT  140.316 41.136 140.4 41.16 ;
    END
  END wd[149]
  PIN wd[14]
    DIRECTION OUTPUT ;
    USE SIGNAL ;
    PORT
      LAYER M4 ;
        RECT  140.316 27.408 140.4 27.432 ;
    END
  END wd[14]
  PIN wd[150]
    DIRECTION OUTPUT ;
    USE SIGNAL ;
    PORT
      LAYER M4 ;
        RECT  140.316 41.232 140.4 41.256 ;
    END
  END wd[150]
  PIN wd[151]
    DIRECTION OUTPUT ;
    USE SIGNAL ;
    PORT
      LAYER M4 ;
        RECT  140.316 41.328 140.4 41.352 ;
    END
  END wd[151]
  PIN wd[152]
    DIRECTION OUTPUT ;
    USE SIGNAL ;
    PORT
      LAYER M4 ;
        RECT  140.316 41.424 140.4 41.448 ;
    END
  END wd[152]
  PIN wd[153]
    DIRECTION OUTPUT ;
    USE SIGNAL ;
    PORT
      LAYER M4 ;
        RECT  140.316 41.52 140.4 41.544 ;
    END
  END wd[153]
  PIN wd[154]
    DIRECTION OUTPUT ;
    USE SIGNAL ;
    PORT
      LAYER M4 ;
        RECT  140.316 41.616 140.4 41.64 ;
    END
  END wd[154]
  PIN wd[155]
    DIRECTION OUTPUT ;
    USE SIGNAL ;
    PORT
      LAYER M4 ;
        RECT  140.316 41.712 140.4 41.736 ;
    END
  END wd[155]
  PIN wd[156]
    DIRECTION OUTPUT ;
    USE SIGNAL ;
    PORT
      LAYER M4 ;
        RECT  140.316 41.808 140.4 41.832 ;
    END
  END wd[156]
  PIN wd[157]
    DIRECTION OUTPUT ;
    USE SIGNAL ;
    PORT
      LAYER M4 ;
        RECT  140.316 41.904 140.4 41.928 ;
    END
  END wd[157]
  PIN wd[158]
    DIRECTION OUTPUT ;
    USE SIGNAL ;
    PORT
      LAYER M4 ;
        RECT  140.316 42 140.4 42.024 ;
    END
  END wd[158]
  PIN wd[159]
    DIRECTION OUTPUT ;
    USE SIGNAL ;
    PORT
      LAYER M4 ;
        RECT  140.316 42.096 140.4 42.12 ;
    END
  END wd[159]
  PIN wd[15]
    DIRECTION OUTPUT ;
    USE SIGNAL ;
    PORT
      LAYER M4 ;
        RECT  140.316 27.504 140.4 27.528 ;
    END
  END wd[15]
  PIN wd[160]
    DIRECTION OUTPUT ;
    USE SIGNAL ;
    PORT
      LAYER M4 ;
        RECT  140.316 42.192 140.4 42.216 ;
    END
  END wd[160]
  PIN wd[161]
    DIRECTION OUTPUT ;
    USE SIGNAL ;
    PORT
      LAYER M4 ;
        RECT  140.316 42.288 140.4 42.312 ;
    END
  END wd[161]
  PIN wd[162]
    DIRECTION OUTPUT ;
    USE SIGNAL ;
    PORT
      LAYER M4 ;
        RECT  140.316 42.384 140.4 42.408 ;
    END
  END wd[162]
  PIN wd[163]
    DIRECTION OUTPUT ;
    USE SIGNAL ;
    PORT
      LAYER M4 ;
        RECT  140.316 42.48 140.4 42.504 ;
    END
  END wd[163]
  PIN wd[164]
    DIRECTION OUTPUT ;
    USE SIGNAL ;
    PORT
      LAYER M4 ;
        RECT  140.316 42.576 140.4 42.6 ;
    END
  END wd[164]
  PIN wd[165]
    DIRECTION OUTPUT ;
    USE SIGNAL ;
    PORT
      LAYER M4 ;
        RECT  140.316 42.672 140.4 42.696 ;
    END
  END wd[165]
  PIN wd[166]
    DIRECTION OUTPUT ;
    USE SIGNAL ;
    PORT
      LAYER M4 ;
        RECT  140.316 42.768 140.4 42.792 ;
    END
  END wd[166]
  PIN wd[167]
    DIRECTION OUTPUT ;
    USE SIGNAL ;
    PORT
      LAYER M4 ;
        RECT  140.316 42.864 140.4 42.888 ;
    END
  END wd[167]
  PIN wd[168]
    DIRECTION OUTPUT ;
    USE SIGNAL ;
    PORT
      LAYER M4 ;
        RECT  140.316 42.96 140.4 42.984 ;
    END
  END wd[168]
  PIN wd[169]
    DIRECTION OUTPUT ;
    USE SIGNAL ;
    PORT
      LAYER M4 ;
        RECT  140.316 43.056 140.4 43.08 ;
    END
  END wd[169]
  PIN wd[16]
    DIRECTION OUTPUT ;
    USE SIGNAL ;
    PORT
      LAYER M4 ;
        RECT  140.316 27.6 140.4 27.624 ;
    END
  END wd[16]
  PIN wd[170]
    DIRECTION OUTPUT ;
    USE SIGNAL ;
    PORT
      LAYER M4 ;
        RECT  140.316 43.152 140.4 43.176 ;
    END
  END wd[170]
  PIN wd[171]
    DIRECTION OUTPUT ;
    USE SIGNAL ;
    PORT
      LAYER M4 ;
        RECT  140.316 43.248 140.4 43.272 ;
    END
  END wd[171]
  PIN wd[172]
    DIRECTION OUTPUT ;
    USE SIGNAL ;
    PORT
      LAYER M4 ;
        RECT  140.316 43.344 140.4 43.368 ;
    END
  END wd[172]
  PIN wd[173]
    DIRECTION OUTPUT ;
    USE SIGNAL ;
    PORT
      LAYER M4 ;
        RECT  140.316 43.44 140.4 43.464 ;
    END
  END wd[173]
  PIN wd[174]
    DIRECTION OUTPUT ;
    USE SIGNAL ;
    PORT
      LAYER M4 ;
        RECT  140.316 43.536 140.4 43.56 ;
    END
  END wd[174]
  PIN wd[175]
    DIRECTION OUTPUT ;
    USE SIGNAL ;
    PORT
      LAYER M4 ;
        RECT  140.316 43.632 140.4 43.656 ;
    END
  END wd[175]
  PIN wd[176]
    DIRECTION OUTPUT ;
    USE SIGNAL ;
    PORT
      LAYER M4 ;
        RECT  140.316 43.728 140.4 43.752 ;
    END
  END wd[176]
  PIN wd[177]
    DIRECTION OUTPUT ;
    USE SIGNAL ;
    PORT
      LAYER M4 ;
        RECT  140.316 43.824 140.4 43.848 ;
    END
  END wd[177]
  PIN wd[178]
    DIRECTION OUTPUT ;
    USE SIGNAL ;
    PORT
      LAYER M4 ;
        RECT  140.316 43.92 140.4 43.944 ;
    END
  END wd[178]
  PIN wd[179]
    DIRECTION OUTPUT ;
    USE SIGNAL ;
    PORT
      LAYER M4 ;
        RECT  140.316 44.016 140.4 44.04 ;
    END
  END wd[179]
  PIN wd[17]
    DIRECTION OUTPUT ;
    USE SIGNAL ;
    PORT
      LAYER M4 ;
        RECT  140.316 27.696 140.4 27.72 ;
    END
  END wd[17]
  PIN wd[180]
    DIRECTION OUTPUT ;
    USE SIGNAL ;
    PORT
      LAYER M4 ;
        RECT  140.316 44.112 140.4 44.136 ;
    END
  END wd[180]
  PIN wd[181]
    DIRECTION OUTPUT ;
    USE SIGNAL ;
    PORT
      LAYER M4 ;
        RECT  140.316 44.208 140.4 44.232 ;
    END
  END wd[181]
  PIN wd[182]
    DIRECTION OUTPUT ;
    USE SIGNAL ;
    PORT
      LAYER M4 ;
        RECT  140.316 44.304 140.4 44.328 ;
    END
  END wd[182]
  PIN wd[183]
    DIRECTION OUTPUT ;
    USE SIGNAL ;
    PORT
      LAYER M4 ;
        RECT  140.316 44.4 140.4 44.424 ;
    END
  END wd[183]
  PIN wd[184]
    DIRECTION OUTPUT ;
    USE SIGNAL ;
    PORT
      LAYER M4 ;
        RECT  140.316 44.496 140.4 44.52 ;
    END
  END wd[184]
  PIN wd[185]
    DIRECTION OUTPUT ;
    USE SIGNAL ;
    PORT
      LAYER M4 ;
        RECT  140.316 44.592 140.4 44.616 ;
    END
  END wd[185]
  PIN wd[186]
    DIRECTION OUTPUT ;
    USE SIGNAL ;
    PORT
      LAYER M4 ;
        RECT  140.316 44.688 140.4 44.712 ;
    END
  END wd[186]
  PIN wd[187]
    DIRECTION OUTPUT ;
    USE SIGNAL ;
    PORT
      LAYER M4 ;
        RECT  140.316 44.784 140.4 44.808 ;
    END
  END wd[187]
  PIN wd[188]
    DIRECTION OUTPUT ;
    USE SIGNAL ;
    PORT
      LAYER M4 ;
        RECT  140.316 44.88 140.4 44.904 ;
    END
  END wd[188]
  PIN wd[189]
    DIRECTION OUTPUT ;
    USE SIGNAL ;
    PORT
      LAYER M4 ;
        RECT  140.316 44.976 140.4 45 ;
    END
  END wd[189]
  PIN wd[18]
    DIRECTION OUTPUT ;
    USE SIGNAL ;
    PORT
      LAYER M4 ;
        RECT  140.316 27.792 140.4 27.816 ;
    END
  END wd[18]
  PIN wd[190]
    DIRECTION OUTPUT ;
    USE SIGNAL ;
    PORT
      LAYER M4 ;
        RECT  140.316 45.072 140.4 45.096 ;
    END
  END wd[190]
  PIN wd[191]
    DIRECTION OUTPUT ;
    USE SIGNAL ;
    PORT
      LAYER M4 ;
        RECT  140.316 45.168 140.4 45.192 ;
    END
  END wd[191]
  PIN wd[192]
    DIRECTION OUTPUT ;
    USE SIGNAL ;
    PORT
      LAYER M4 ;
        RECT  140.316 45.264 140.4 45.288 ;
    END
  END wd[192]
  PIN wd[193]
    DIRECTION OUTPUT ;
    USE SIGNAL ;
    PORT
      LAYER M4 ;
        RECT  140.316 45.36 140.4 45.384 ;
    END
  END wd[193]
  PIN wd[194]
    DIRECTION OUTPUT ;
    USE SIGNAL ;
    PORT
      LAYER M4 ;
        RECT  140.316 45.456 140.4 45.48 ;
    END
  END wd[194]
  PIN wd[195]
    DIRECTION OUTPUT ;
    USE SIGNAL ;
    PORT
      LAYER M4 ;
        RECT  140.316 45.552 140.4 45.576 ;
    END
  END wd[195]
  PIN wd[196]
    DIRECTION OUTPUT ;
    USE SIGNAL ;
    PORT
      LAYER M4 ;
        RECT  140.316 45.648 140.4 45.672 ;
    END
  END wd[196]
  PIN wd[197]
    DIRECTION OUTPUT ;
    USE SIGNAL ;
    PORT
      LAYER M4 ;
        RECT  140.316 45.744 140.4 45.768 ;
    END
  END wd[197]
  PIN wd[198]
    DIRECTION OUTPUT ;
    USE SIGNAL ;
    PORT
      LAYER M4 ;
        RECT  140.316 45.84 140.4 45.864 ;
    END
  END wd[198]
  PIN wd[199]
    DIRECTION OUTPUT ;
    USE SIGNAL ;
    PORT
      LAYER M4 ;
        RECT  140.316 45.936 140.4 45.96 ;
    END
  END wd[199]
  PIN wd[19]
    DIRECTION OUTPUT ;
    USE SIGNAL ;
    PORT
      LAYER M4 ;
        RECT  140.316 27.888 140.4 27.912 ;
    END
  END wd[19]
  PIN wd[1]
    DIRECTION OUTPUT ;
    USE SIGNAL ;
    PORT
      LAYER M4 ;
        RECT  140.316 26.16 140.4 26.184 ;
    END
  END wd[1]
  PIN wd[200]
    DIRECTION OUTPUT ;
    USE SIGNAL ;
    PORT
      LAYER M4 ;
        RECT  140.316 46.032 140.4 46.056 ;
    END
  END wd[200]
  PIN wd[201]
    DIRECTION OUTPUT ;
    USE SIGNAL ;
    PORT
      LAYER M4 ;
        RECT  140.316 46.128 140.4 46.152 ;
    END
  END wd[201]
  PIN wd[202]
    DIRECTION OUTPUT ;
    USE SIGNAL ;
    PORT
      LAYER M4 ;
        RECT  140.316 46.224 140.4 46.248 ;
    END
  END wd[202]
  PIN wd[203]
    DIRECTION OUTPUT ;
    USE SIGNAL ;
    PORT
      LAYER M4 ;
        RECT  140.316 46.32 140.4 46.344 ;
    END
  END wd[203]
  PIN wd[204]
    DIRECTION OUTPUT ;
    USE SIGNAL ;
    PORT
      LAYER M4 ;
        RECT  140.316 46.416 140.4 46.44 ;
    END
  END wd[204]
  PIN wd[205]
    DIRECTION OUTPUT ;
    USE SIGNAL ;
    PORT
      LAYER M4 ;
        RECT  140.316 46.512 140.4 46.536 ;
    END
  END wd[205]
  PIN wd[206]
    DIRECTION OUTPUT ;
    USE SIGNAL ;
    PORT
      LAYER M4 ;
        RECT  140.316 46.608 140.4 46.632 ;
    END
  END wd[206]
  PIN wd[207]
    DIRECTION OUTPUT ;
    USE SIGNAL ;
    PORT
      LAYER M4 ;
        RECT  140.316 46.704 140.4 46.728 ;
    END
  END wd[207]
  PIN wd[208]
    DIRECTION OUTPUT ;
    USE SIGNAL ;
    PORT
      LAYER M4 ;
        RECT  140.316 46.8 140.4 46.824 ;
    END
  END wd[208]
  PIN wd[209]
    DIRECTION OUTPUT ;
    USE SIGNAL ;
    PORT
      LAYER M4 ;
        RECT  140.316 46.896 140.4 46.92 ;
    END
  END wd[209]
  PIN wd[20]
    DIRECTION OUTPUT ;
    USE SIGNAL ;
    PORT
      LAYER M4 ;
        RECT  140.316 27.984 140.4 28.008 ;
    END
  END wd[20]
  PIN wd[210]
    DIRECTION OUTPUT ;
    USE SIGNAL ;
    PORT
      LAYER M4 ;
        RECT  140.316 46.992 140.4 47.016 ;
    END
  END wd[210]
  PIN wd[211]
    DIRECTION OUTPUT ;
    USE SIGNAL ;
    PORT
      LAYER M4 ;
        RECT  140.316 47.088 140.4 47.112 ;
    END
  END wd[211]
  PIN wd[212]
    DIRECTION OUTPUT ;
    USE SIGNAL ;
    PORT
      LAYER M4 ;
        RECT  140.316 47.184 140.4 47.208 ;
    END
  END wd[212]
  PIN wd[213]
    DIRECTION OUTPUT ;
    USE SIGNAL ;
    PORT
      LAYER M4 ;
        RECT  140.316 47.28 140.4 47.304 ;
    END
  END wd[213]
  PIN wd[214]
    DIRECTION OUTPUT ;
    USE SIGNAL ;
    PORT
      LAYER M4 ;
        RECT  140.316 47.376 140.4 47.4 ;
    END
  END wd[214]
  PIN wd[215]
    DIRECTION OUTPUT ;
    USE SIGNAL ;
    PORT
      LAYER M4 ;
        RECT  140.316 47.472 140.4 47.496 ;
    END
  END wd[215]
  PIN wd[216]
    DIRECTION OUTPUT ;
    USE SIGNAL ;
    PORT
      LAYER M4 ;
        RECT  140.316 47.568 140.4 47.592 ;
    END
  END wd[216]
  PIN wd[217]
    DIRECTION OUTPUT ;
    USE SIGNAL ;
    PORT
      LAYER M4 ;
        RECT  140.316 47.664 140.4 47.688 ;
    END
  END wd[217]
  PIN wd[218]
    DIRECTION OUTPUT ;
    USE SIGNAL ;
    PORT
      LAYER M4 ;
        RECT  140.316 47.76 140.4 47.784 ;
    END
  END wd[218]
  PIN wd[219]
    DIRECTION OUTPUT ;
    USE SIGNAL ;
    PORT
      LAYER M4 ;
        RECT  140.316 47.856 140.4 47.88 ;
    END
  END wd[219]
  PIN wd[21]
    DIRECTION OUTPUT ;
    USE SIGNAL ;
    PORT
      LAYER M4 ;
        RECT  140.316 28.08 140.4 28.104 ;
    END
  END wd[21]
  PIN wd[220]
    DIRECTION OUTPUT ;
    USE SIGNAL ;
    PORT
      LAYER M4 ;
        RECT  140.316 47.952 140.4 47.976 ;
    END
  END wd[220]
  PIN wd[221]
    DIRECTION OUTPUT ;
    USE SIGNAL ;
    PORT
      LAYER M4 ;
        RECT  140.316 48.048 140.4 48.072 ;
    END
  END wd[221]
  PIN wd[222]
    DIRECTION OUTPUT ;
    USE SIGNAL ;
    PORT
      LAYER M4 ;
        RECT  140.316 48.144 140.4 48.168 ;
    END
  END wd[222]
  PIN wd[223]
    DIRECTION OUTPUT ;
    USE SIGNAL ;
    PORT
      LAYER M4 ;
        RECT  140.316 48.24 140.4 48.264 ;
    END
  END wd[223]
  PIN wd[224]
    DIRECTION OUTPUT ;
    USE SIGNAL ;
    PORT
      LAYER M4 ;
        RECT  140.316 48.336 140.4 48.36 ;
    END
  END wd[224]
  PIN wd[225]
    DIRECTION OUTPUT ;
    USE SIGNAL ;
    PORT
      LAYER M4 ;
        RECT  140.316 48.432 140.4 48.456 ;
    END
  END wd[225]
  PIN wd[226]
    DIRECTION OUTPUT ;
    USE SIGNAL ;
    PORT
      LAYER M4 ;
        RECT  140.316 48.528 140.4 48.552 ;
    END
  END wd[226]
  PIN wd[227]
    DIRECTION OUTPUT ;
    USE SIGNAL ;
    PORT
      LAYER M4 ;
        RECT  140.316 48.624 140.4 48.648 ;
    END
  END wd[227]
  PIN wd[228]
    DIRECTION OUTPUT ;
    USE SIGNAL ;
    PORT
      LAYER M4 ;
        RECT  140.316 48.72 140.4 48.744 ;
    END
  END wd[228]
  PIN wd[229]
    DIRECTION OUTPUT ;
    USE SIGNAL ;
    PORT
      LAYER M4 ;
        RECT  140.316 48.816 140.4 48.84 ;
    END
  END wd[229]
  PIN wd[22]
    DIRECTION OUTPUT ;
    USE SIGNAL ;
    PORT
      LAYER M4 ;
        RECT  140.316 28.176 140.4 28.2 ;
    END
  END wd[22]
  PIN wd[230]
    DIRECTION OUTPUT ;
    USE SIGNAL ;
    PORT
      LAYER M4 ;
        RECT  140.316 48.912 140.4 48.936 ;
    END
  END wd[230]
  PIN wd[231]
    DIRECTION OUTPUT ;
    USE SIGNAL ;
    PORT
      LAYER M4 ;
        RECT  140.316 49.008 140.4 49.032 ;
    END
  END wd[231]
  PIN wd[232]
    DIRECTION OUTPUT ;
    USE SIGNAL ;
    PORT
      LAYER M4 ;
        RECT  140.316 49.104 140.4 49.128 ;
    END
  END wd[232]
  PIN wd[233]
    DIRECTION OUTPUT ;
    USE SIGNAL ;
    PORT
      LAYER M4 ;
        RECT  140.316 49.2 140.4 49.224 ;
    END
  END wd[233]
  PIN wd[234]
    DIRECTION OUTPUT ;
    USE SIGNAL ;
    PORT
      LAYER M4 ;
        RECT  140.316 49.296 140.4 49.32 ;
    END
  END wd[234]
  PIN wd[235]
    DIRECTION OUTPUT ;
    USE SIGNAL ;
    PORT
      LAYER M4 ;
        RECT  140.316 49.392 140.4 49.416 ;
    END
  END wd[235]
  PIN wd[236]
    DIRECTION OUTPUT ;
    USE SIGNAL ;
    PORT
      LAYER M4 ;
        RECT  140.316 49.488 140.4 49.512 ;
    END
  END wd[236]
  PIN wd[237]
    DIRECTION OUTPUT ;
    USE SIGNAL ;
    PORT
      LAYER M4 ;
        RECT  140.316 49.584 140.4 49.608 ;
    END
  END wd[237]
  PIN wd[238]
    DIRECTION OUTPUT ;
    USE SIGNAL ;
    PORT
      LAYER M4 ;
        RECT  140.316 49.68 140.4 49.704 ;
    END
  END wd[238]
  PIN wd[239]
    DIRECTION OUTPUT ;
    USE SIGNAL ;
    PORT
      LAYER M4 ;
        RECT  140.316 49.776 140.4 49.8 ;
    END
  END wd[239]
  PIN wd[23]
    DIRECTION OUTPUT ;
    USE SIGNAL ;
    PORT
      LAYER M4 ;
        RECT  140.316 28.272 140.4 28.296 ;
    END
  END wd[23]
  PIN wd[240]
    DIRECTION OUTPUT ;
    USE SIGNAL ;
    PORT
      LAYER M4 ;
        RECT  140.316 49.872 140.4 49.896 ;
    END
  END wd[240]
  PIN wd[241]
    DIRECTION OUTPUT ;
    USE SIGNAL ;
    PORT
      LAYER M4 ;
        RECT  140.316 49.968 140.4 49.992 ;
    END
  END wd[241]
  PIN wd[242]
    DIRECTION OUTPUT ;
    USE SIGNAL ;
    PORT
      LAYER M4 ;
        RECT  140.316 50.064 140.4 50.088 ;
    END
  END wd[242]
  PIN wd[243]
    DIRECTION OUTPUT ;
    USE SIGNAL ;
    PORT
      LAYER M4 ;
        RECT  140.316 50.16 140.4 50.184 ;
    END
  END wd[243]
  PIN wd[244]
    DIRECTION OUTPUT ;
    USE SIGNAL ;
    PORT
      LAYER M4 ;
        RECT  140.316 50.256 140.4 50.28 ;
    END
  END wd[244]
  PIN wd[245]
    DIRECTION OUTPUT ;
    USE SIGNAL ;
    PORT
      LAYER M4 ;
        RECT  140.316 50.352 140.4 50.376 ;
    END
  END wd[245]
  PIN wd[246]
    DIRECTION OUTPUT ;
    USE SIGNAL ;
    PORT
      LAYER M4 ;
        RECT  140.316 50.448 140.4 50.472 ;
    END
  END wd[246]
  PIN wd[247]
    DIRECTION OUTPUT ;
    USE SIGNAL ;
    PORT
      LAYER M4 ;
        RECT  140.316 50.544 140.4 50.568 ;
    END
  END wd[247]
  PIN wd[248]
    DIRECTION OUTPUT ;
    USE SIGNAL ;
    PORT
      LAYER M4 ;
        RECT  140.316 50.64 140.4 50.664 ;
    END
  END wd[248]
  PIN wd[249]
    DIRECTION OUTPUT ;
    USE SIGNAL ;
    PORT
      LAYER M4 ;
        RECT  140.316 50.736 140.4 50.76 ;
    END
  END wd[249]
  PIN wd[24]
    DIRECTION OUTPUT ;
    USE SIGNAL ;
    PORT
      LAYER M4 ;
        RECT  140.316 28.368 140.4 28.392 ;
    END
  END wd[24]
  PIN wd[250]
    DIRECTION OUTPUT ;
    USE SIGNAL ;
    PORT
      LAYER M4 ;
        RECT  140.316 50.832 140.4 50.856 ;
    END
  END wd[250]
  PIN wd[251]
    DIRECTION OUTPUT ;
    USE SIGNAL ;
    PORT
      LAYER M4 ;
        RECT  140.316 50.928 140.4 50.952 ;
    END
  END wd[251]
  PIN wd[252]
    DIRECTION OUTPUT ;
    USE SIGNAL ;
    PORT
      LAYER M4 ;
        RECT  140.316 51.024 140.4 51.048 ;
    END
  END wd[252]
  PIN wd[253]
    DIRECTION OUTPUT ;
    USE SIGNAL ;
    PORT
      LAYER M4 ;
        RECT  140.316 51.12 140.4 51.144 ;
    END
  END wd[253]
  PIN wd[254]
    DIRECTION OUTPUT ;
    USE SIGNAL ;
    PORT
      LAYER M4 ;
        RECT  140.316 51.216 140.4 51.24 ;
    END
  END wd[254]
  PIN wd[255]
    DIRECTION OUTPUT ;
    USE SIGNAL ;
    PORT
      LAYER M4 ;
        RECT  140.316 51.312 140.4 51.336 ;
    END
  END wd[255]
  PIN wd[256]
    DIRECTION OUTPUT ;
    USE SIGNAL ;
    PORT
      LAYER M4 ;
        RECT  140.316 19.92 140.4 19.944 ;
    END
  END wd[256]
  PIN wd[257]
    DIRECTION OUTPUT ;
    USE SIGNAL ;
    PORT
      LAYER M4 ;
        RECT  140.316 20.016 140.4 20.04 ;
    END
  END wd[257]
  PIN wd[258]
    DIRECTION OUTPUT ;
    USE SIGNAL ;
    PORT
      LAYER M4 ;
        RECT  140.316 20.112 140.4 20.136 ;
    END
  END wd[258]
  PIN wd[259]
    DIRECTION OUTPUT ;
    USE SIGNAL ;
    PORT
      LAYER M4 ;
        RECT  140.316 20.208 140.4 20.232 ;
    END
  END wd[259]
  PIN wd[25]
    DIRECTION OUTPUT ;
    USE SIGNAL ;
    PORT
      LAYER M4 ;
        RECT  140.316 28.464 140.4 28.488 ;
    END
  END wd[25]
  PIN wd[260]
    DIRECTION OUTPUT ;
    USE SIGNAL ;
    PORT
      LAYER M4 ;
        RECT  140.316 20.304 140.4 20.328 ;
    END
  END wd[260]
  PIN wd[261]
    DIRECTION OUTPUT ;
    USE SIGNAL ;
    PORT
      LAYER M4 ;
        RECT  140.316 20.4 140.4 20.424 ;
    END
  END wd[261]
  PIN wd[262]
    DIRECTION OUTPUT ;
    USE SIGNAL ;
    PORT
      LAYER M4 ;
        RECT  140.316 20.496 140.4 20.52 ;
    END
  END wd[262]
  PIN wd[263]
    DIRECTION OUTPUT ;
    USE SIGNAL ;
    PORT
      LAYER M4 ;
        RECT  140.316 20.592 140.4 20.616 ;
    END
  END wd[263]
  PIN wd[264]
    DIRECTION OUTPUT ;
    USE SIGNAL ;
    PORT
      LAYER M4 ;
        RECT  140.316 20.688 140.4 20.712 ;
    END
  END wd[264]
  PIN wd[265]
    DIRECTION OUTPUT ;
    USE SIGNAL ;
    PORT
      LAYER M4 ;
        RECT  140.316 20.784 140.4 20.808 ;
    END
  END wd[265]
  PIN wd[266]
    DIRECTION OUTPUT ;
    USE SIGNAL ;
    PORT
      LAYER M4 ;
        RECT  140.316 20.88 140.4 20.904 ;
    END
  END wd[266]
  PIN wd[267]
    DIRECTION OUTPUT ;
    USE SIGNAL ;
    PORT
      LAYER M4 ;
        RECT  140.316 20.976 140.4 21 ;
    END
  END wd[267]
  PIN wd[268]
    DIRECTION OUTPUT ;
    USE SIGNAL ;
    PORT
      LAYER M4 ;
        RECT  140.316 21.072 140.4 21.096 ;
    END
  END wd[268]
  PIN wd[269]
    DIRECTION OUTPUT ;
    USE SIGNAL ;
    PORT
      LAYER M4 ;
        RECT  140.316 21.168 140.4 21.192 ;
    END
  END wd[269]
  PIN wd[26]
    DIRECTION OUTPUT ;
    USE SIGNAL ;
    PORT
      LAYER M4 ;
        RECT  140.316 28.56 140.4 28.584 ;
    END
  END wd[26]
  PIN wd[270]
    DIRECTION OUTPUT ;
    USE SIGNAL ;
    PORT
      LAYER M4 ;
        RECT  140.316 21.264 140.4 21.288 ;
    END
  END wd[270]
  PIN wd[271]
    DIRECTION OUTPUT ;
    USE SIGNAL ;
    PORT
      LAYER M4 ;
        RECT  140.316 21.36 140.4 21.384 ;
    END
  END wd[271]
  PIN wd[272]
    DIRECTION OUTPUT ;
    USE SIGNAL ;
    PORT
      LAYER M4 ;
        RECT  140.316 21.456 140.4 21.48 ;
    END
  END wd[272]
  PIN wd[273]
    DIRECTION OUTPUT ;
    USE SIGNAL ;
    PORT
      LAYER M4 ;
        RECT  140.316 21.552 140.4 21.576 ;
    END
  END wd[273]
  PIN wd[274]
    DIRECTION OUTPUT ;
    USE SIGNAL ;
    PORT
      LAYER M4 ;
        RECT  140.316 21.648 140.4 21.672 ;
    END
  END wd[274]
  PIN wd[275]
    DIRECTION OUTPUT ;
    USE SIGNAL ;
    PORT
      LAYER M4 ;
        RECT  140.316 21.744 140.4 21.768 ;
    END
  END wd[275]
  PIN wd[276]
    DIRECTION OUTPUT ;
    USE SIGNAL ;
    PORT
      LAYER M4 ;
        RECT  140.316 21.84 140.4 21.864 ;
    END
  END wd[276]
  PIN wd[277]
    DIRECTION OUTPUT ;
    USE SIGNAL ;
    PORT
      LAYER M4 ;
        RECT  140.316 21.936 140.4 21.96 ;
    END
  END wd[277]
  PIN wd[278]
    DIRECTION OUTPUT ;
    USE SIGNAL ;
    PORT
      LAYER M4 ;
        RECT  140.316 22.032 140.4 22.056 ;
    END
  END wd[278]
  PIN wd[279]
    DIRECTION OUTPUT ;
    USE SIGNAL ;
    PORT
      LAYER M4 ;
        RECT  140.316 22.128 140.4 22.152 ;
    END
  END wd[279]
  PIN wd[27]
    DIRECTION OUTPUT ;
    USE SIGNAL ;
    PORT
      LAYER M4 ;
        RECT  140.316 28.656 140.4 28.68 ;
    END
  END wd[27]
  PIN wd[280]
    DIRECTION OUTPUT ;
    USE SIGNAL ;
    PORT
      LAYER M4 ;
        RECT  140.316 22.224 140.4 22.248 ;
    END
  END wd[280]
  PIN wd[281]
    DIRECTION OUTPUT ;
    USE SIGNAL ;
    PORT
      LAYER M4 ;
        RECT  140.316 22.32 140.4 22.344 ;
    END
  END wd[281]
  PIN wd[282]
    DIRECTION OUTPUT ;
    USE SIGNAL ;
    PORT
      LAYER M4 ;
        RECT  140.316 22.416 140.4 22.44 ;
    END
  END wd[282]
  PIN wd[283]
    DIRECTION OUTPUT ;
    USE SIGNAL ;
    PORT
      LAYER M4 ;
        RECT  140.316 22.512 140.4 22.536 ;
    END
  END wd[283]
  PIN wd[284]
    DIRECTION OUTPUT ;
    USE SIGNAL ;
    PORT
      LAYER M4 ;
        RECT  140.316 22.608 140.4 22.632 ;
    END
  END wd[284]
  PIN wd[285]
    DIRECTION OUTPUT ;
    USE SIGNAL ;
    PORT
      LAYER M4 ;
        RECT  140.316 22.704 140.4 22.728 ;
    END
  END wd[285]
  PIN wd[286]
    DIRECTION OUTPUT ;
    USE SIGNAL ;
    PORT
      LAYER M4 ;
        RECT  140.316 22.8 140.4 22.824 ;
    END
  END wd[286]
  PIN wd[287]
    DIRECTION OUTPUT ;
    USE SIGNAL ;
    PORT
      LAYER M4 ;
        RECT  140.316 22.896 140.4 22.92 ;
    END
  END wd[287]
  PIN wd[288]
    DIRECTION OUTPUT ;
    USE SIGNAL ;
    PORT
      LAYER M4 ;
        RECT  140.316 22.992 140.4 23.016 ;
    END
  END wd[288]
  PIN wd[28]
    DIRECTION OUTPUT ;
    USE SIGNAL ;
    PORT
      LAYER M4 ;
        RECT  140.316 28.752 140.4 28.776 ;
    END
  END wd[28]
  PIN wd[29]
    DIRECTION OUTPUT ;
    USE SIGNAL ;
    PORT
      LAYER M4 ;
        RECT  140.316 28.848 140.4 28.872 ;
    END
  END wd[29]
  PIN wd[2]
    DIRECTION OUTPUT ;
    USE SIGNAL ;
    PORT
      LAYER M4 ;
        RECT  140.316 26.256 140.4 26.28 ;
    END
  END wd[2]
  PIN wd[30]
    DIRECTION OUTPUT ;
    USE SIGNAL ;
    PORT
      LAYER M4 ;
        RECT  140.316 28.944 140.4 28.968 ;
    END
  END wd[30]
  PIN wd[31]
    DIRECTION OUTPUT ;
    USE SIGNAL ;
    PORT
      LAYER M4 ;
        RECT  140.316 29.04 140.4 29.064 ;
    END
  END wd[31]
  PIN wd[32]
    DIRECTION OUTPUT ;
    USE SIGNAL ;
    PORT
      LAYER M4 ;
        RECT  140.316 29.136 140.4 29.16 ;
    END
  END wd[32]
  PIN wd[33]
    DIRECTION OUTPUT ;
    USE SIGNAL ;
    PORT
      LAYER M4 ;
        RECT  140.316 29.232 140.4 29.256 ;
    END
  END wd[33]
  PIN wd[34]
    DIRECTION OUTPUT ;
    USE SIGNAL ;
    PORT
      LAYER M4 ;
        RECT  140.316 29.328 140.4 29.352 ;
    END
  END wd[34]
  PIN wd[35]
    DIRECTION OUTPUT ;
    USE SIGNAL ;
    PORT
      LAYER M4 ;
        RECT  140.316 29.424 140.4 29.448 ;
    END
  END wd[35]
  PIN wd[36]
    DIRECTION OUTPUT ;
    USE SIGNAL ;
    PORT
      LAYER M4 ;
        RECT  140.316 29.52 140.4 29.544 ;
    END
  END wd[36]
  PIN wd[37]
    DIRECTION OUTPUT ;
    USE SIGNAL ;
    PORT
      LAYER M4 ;
        RECT  140.316 29.616 140.4 29.64 ;
    END
  END wd[37]
  PIN wd[38]
    DIRECTION OUTPUT ;
    USE SIGNAL ;
    PORT
      LAYER M4 ;
        RECT  140.316 29.712 140.4 29.736 ;
    END
  END wd[38]
  PIN wd[39]
    DIRECTION OUTPUT ;
    USE SIGNAL ;
    PORT
      LAYER M4 ;
        RECT  140.316 29.808 140.4 29.832 ;
    END
  END wd[39]
  PIN wd[3]
    DIRECTION OUTPUT ;
    USE SIGNAL ;
    PORT
      LAYER M4 ;
        RECT  140.316 26.352 140.4 26.376 ;
    END
  END wd[3]
  PIN wd[40]
    DIRECTION OUTPUT ;
    USE SIGNAL ;
    PORT
      LAYER M4 ;
        RECT  140.316 29.904 140.4 29.928 ;
    END
  END wd[40]
  PIN wd[41]
    DIRECTION OUTPUT ;
    USE SIGNAL ;
    PORT
      LAYER M4 ;
        RECT  140.316 30 140.4 30.024 ;
    END
  END wd[41]
  PIN wd[42]
    DIRECTION OUTPUT ;
    USE SIGNAL ;
    PORT
      LAYER M4 ;
        RECT  140.316 30.096 140.4 30.12 ;
    END
  END wd[42]
  PIN wd[43]
    DIRECTION OUTPUT ;
    USE SIGNAL ;
    PORT
      LAYER M4 ;
        RECT  140.316 30.192 140.4 30.216 ;
    END
  END wd[43]
  PIN wd[44]
    DIRECTION OUTPUT ;
    USE SIGNAL ;
    PORT
      LAYER M4 ;
        RECT  140.316 30.288 140.4 30.312 ;
    END
  END wd[44]
  PIN wd[45]
    DIRECTION OUTPUT ;
    USE SIGNAL ;
    PORT
      LAYER M4 ;
        RECT  140.316 30.384 140.4 30.408 ;
    END
  END wd[45]
  PIN wd[46]
    DIRECTION OUTPUT ;
    USE SIGNAL ;
    PORT
      LAYER M4 ;
        RECT  140.316 30.48 140.4 30.504 ;
    END
  END wd[46]
  PIN wd[47]
    DIRECTION OUTPUT ;
    USE SIGNAL ;
    PORT
      LAYER M4 ;
        RECT  140.316 30.576 140.4 30.6 ;
    END
  END wd[47]
  PIN wd[48]
    DIRECTION OUTPUT ;
    USE SIGNAL ;
    PORT
      LAYER M4 ;
        RECT  140.316 30.672 140.4 30.696 ;
    END
  END wd[48]
  PIN wd[49]
    DIRECTION OUTPUT ;
    USE SIGNAL ;
    PORT
      LAYER M4 ;
        RECT  140.316 30.768 140.4 30.792 ;
    END
  END wd[49]
  PIN wd[4]
    DIRECTION OUTPUT ;
    USE SIGNAL ;
    PORT
      LAYER M4 ;
        RECT  140.316 26.448 140.4 26.472 ;
    END
  END wd[4]
  PIN wd[50]
    DIRECTION OUTPUT ;
    USE SIGNAL ;
    PORT
      LAYER M4 ;
        RECT  140.316 30.864 140.4 30.888 ;
    END
  END wd[50]
  PIN wd[51]
    DIRECTION OUTPUT ;
    USE SIGNAL ;
    PORT
      LAYER M4 ;
        RECT  140.316 30.96 140.4 30.984 ;
    END
  END wd[51]
  PIN wd[52]
    DIRECTION OUTPUT ;
    USE SIGNAL ;
    PORT
      LAYER M4 ;
        RECT  140.316 31.056 140.4 31.08 ;
    END
  END wd[52]
  PIN wd[53]
    DIRECTION OUTPUT ;
    USE SIGNAL ;
    PORT
      LAYER M4 ;
        RECT  140.316 31.152 140.4 31.176 ;
    END
  END wd[53]
  PIN wd[54]
    DIRECTION OUTPUT ;
    USE SIGNAL ;
    PORT
      LAYER M4 ;
        RECT  140.316 31.248 140.4 31.272 ;
    END
  END wd[54]
  PIN wd[55]
    DIRECTION OUTPUT ;
    USE SIGNAL ;
    PORT
      LAYER M4 ;
        RECT  140.316 31.344 140.4 31.368 ;
    END
  END wd[55]
  PIN wd[56]
    DIRECTION OUTPUT ;
    USE SIGNAL ;
    PORT
      LAYER M4 ;
        RECT  140.316 31.44 140.4 31.464 ;
    END
  END wd[56]
  PIN wd[57]
    DIRECTION OUTPUT ;
    USE SIGNAL ;
    PORT
      LAYER M4 ;
        RECT  140.316 31.536 140.4 31.56 ;
    END
  END wd[57]
  PIN wd[58]
    DIRECTION OUTPUT ;
    USE SIGNAL ;
    PORT
      LAYER M4 ;
        RECT  140.316 31.632 140.4 31.656 ;
    END
  END wd[58]
  PIN wd[59]
    DIRECTION OUTPUT ;
    USE SIGNAL ;
    PORT
      LAYER M4 ;
        RECT  140.316 31.728 140.4 31.752 ;
    END
  END wd[59]
  PIN wd[5]
    DIRECTION OUTPUT ;
    USE SIGNAL ;
    PORT
      LAYER M4 ;
        RECT  140.316 26.544 140.4 26.568 ;
    END
  END wd[5]
  PIN wd[60]
    DIRECTION OUTPUT ;
    USE SIGNAL ;
    PORT
      LAYER M4 ;
        RECT  140.316 31.824 140.4 31.848 ;
    END
  END wd[60]
  PIN wd[61]
    DIRECTION OUTPUT ;
    USE SIGNAL ;
    PORT
      LAYER M4 ;
        RECT  140.316 31.92 140.4 31.944 ;
    END
  END wd[61]
  PIN wd[62]
    DIRECTION OUTPUT ;
    USE SIGNAL ;
    PORT
      LAYER M4 ;
        RECT  140.316 32.016 140.4 32.04 ;
    END
  END wd[62]
  PIN wd[63]
    DIRECTION OUTPUT ;
    USE SIGNAL ;
    PORT
      LAYER M4 ;
        RECT  140.316 32.112 140.4 32.136 ;
    END
  END wd[63]
  PIN wd[64]
    DIRECTION OUTPUT ;
    USE SIGNAL ;
    PORT
      LAYER M4 ;
        RECT  140.316 32.208 140.4 32.232 ;
    END
  END wd[64]
  PIN wd[65]
    DIRECTION OUTPUT ;
    USE SIGNAL ;
    PORT
      LAYER M4 ;
        RECT  140.316 32.304 140.4 32.328 ;
    END
  END wd[65]
  PIN wd[66]
    DIRECTION OUTPUT ;
    USE SIGNAL ;
    PORT
      LAYER M4 ;
        RECT  140.316 32.4 140.4 32.424 ;
    END
  END wd[66]
  PIN wd[67]
    DIRECTION OUTPUT ;
    USE SIGNAL ;
    PORT
      LAYER M4 ;
        RECT  140.316 32.496 140.4 32.52 ;
    END
  END wd[67]
  PIN wd[68]
    DIRECTION OUTPUT ;
    USE SIGNAL ;
    PORT
      LAYER M4 ;
        RECT  140.316 32.592 140.4 32.616 ;
    END
  END wd[68]
  PIN wd[69]
    DIRECTION OUTPUT ;
    USE SIGNAL ;
    PORT
      LAYER M4 ;
        RECT  140.316 32.688 140.4 32.712 ;
    END
  END wd[69]
  PIN wd[6]
    DIRECTION OUTPUT ;
    USE SIGNAL ;
    PORT
      LAYER M4 ;
        RECT  140.316 26.64 140.4 26.664 ;
    END
  END wd[6]
  PIN wd[70]
    DIRECTION OUTPUT ;
    USE SIGNAL ;
    PORT
      LAYER M4 ;
        RECT  140.316 32.784 140.4 32.808 ;
    END
  END wd[70]
  PIN wd[71]
    DIRECTION OUTPUT ;
    USE SIGNAL ;
    PORT
      LAYER M4 ;
        RECT  140.316 32.88 140.4 32.904 ;
    END
  END wd[71]
  PIN wd[72]
    DIRECTION OUTPUT ;
    USE SIGNAL ;
    PORT
      LAYER M4 ;
        RECT  140.316 32.976 140.4 33 ;
    END
  END wd[72]
  PIN wd[73]
    DIRECTION OUTPUT ;
    USE SIGNAL ;
    PORT
      LAYER M4 ;
        RECT  140.316 33.072 140.4 33.096 ;
    END
  END wd[73]
  PIN wd[74]
    DIRECTION OUTPUT ;
    USE SIGNAL ;
    PORT
      LAYER M4 ;
        RECT  140.316 33.168 140.4 33.192 ;
    END
  END wd[74]
  PIN wd[75]
    DIRECTION OUTPUT ;
    USE SIGNAL ;
    PORT
      LAYER M4 ;
        RECT  140.316 33.264 140.4 33.288 ;
    END
  END wd[75]
  PIN wd[76]
    DIRECTION OUTPUT ;
    USE SIGNAL ;
    PORT
      LAYER M4 ;
        RECT  140.316 33.36 140.4 33.384 ;
    END
  END wd[76]
  PIN wd[77]
    DIRECTION OUTPUT ;
    USE SIGNAL ;
    PORT
      LAYER M4 ;
        RECT  140.316 33.456 140.4 33.48 ;
    END
  END wd[77]
  PIN wd[78]
    DIRECTION OUTPUT ;
    USE SIGNAL ;
    PORT
      LAYER M4 ;
        RECT  140.316 33.552 140.4 33.576 ;
    END
  END wd[78]
  PIN wd[79]
    DIRECTION OUTPUT ;
    USE SIGNAL ;
    PORT
      LAYER M4 ;
        RECT  140.316 33.648 140.4 33.672 ;
    END
  END wd[79]
  PIN wd[7]
    DIRECTION OUTPUT ;
    USE SIGNAL ;
    PORT
      LAYER M4 ;
        RECT  140.316 26.736 140.4 26.76 ;
    END
  END wd[7]
  PIN wd[80]
    DIRECTION OUTPUT ;
    USE SIGNAL ;
    PORT
      LAYER M4 ;
        RECT  140.316 33.744 140.4 33.768 ;
    END
  END wd[80]
  PIN wd[81]
    DIRECTION OUTPUT ;
    USE SIGNAL ;
    PORT
      LAYER M4 ;
        RECT  140.316 33.84 140.4 33.864 ;
    END
  END wd[81]
  PIN wd[82]
    DIRECTION OUTPUT ;
    USE SIGNAL ;
    PORT
      LAYER M4 ;
        RECT  140.316 33.936 140.4 33.96 ;
    END
  END wd[82]
  PIN wd[83]
    DIRECTION OUTPUT ;
    USE SIGNAL ;
    PORT
      LAYER M4 ;
        RECT  140.316 34.032 140.4 34.056 ;
    END
  END wd[83]
  PIN wd[84]
    DIRECTION OUTPUT ;
    USE SIGNAL ;
    PORT
      LAYER M4 ;
        RECT  140.316 34.128 140.4 34.152 ;
    END
  END wd[84]
  PIN wd[85]
    DIRECTION OUTPUT ;
    USE SIGNAL ;
    PORT
      LAYER M4 ;
        RECT  140.316 34.224 140.4 34.248 ;
    END
  END wd[85]
  PIN wd[86]
    DIRECTION OUTPUT ;
    USE SIGNAL ;
    PORT
      LAYER M4 ;
        RECT  140.316 34.32 140.4 34.344 ;
    END
  END wd[86]
  PIN wd[87]
    DIRECTION OUTPUT ;
    USE SIGNAL ;
    PORT
      LAYER M4 ;
        RECT  140.316 34.416 140.4 34.44 ;
    END
  END wd[87]
  PIN wd[88]
    DIRECTION OUTPUT ;
    USE SIGNAL ;
    PORT
      LAYER M4 ;
        RECT  140.316 34.512 140.4 34.536 ;
    END
  END wd[88]
  PIN wd[89]
    DIRECTION OUTPUT ;
    USE SIGNAL ;
    PORT
      LAYER M4 ;
        RECT  140.316 34.608 140.4 34.632 ;
    END
  END wd[89]
  PIN wd[8]
    DIRECTION OUTPUT ;
    USE SIGNAL ;
    PORT
      LAYER M4 ;
        RECT  140.316 26.832 140.4 26.856 ;
    END
  END wd[8]
  PIN wd[90]
    DIRECTION OUTPUT ;
    USE SIGNAL ;
    PORT
      LAYER M4 ;
        RECT  140.316 34.704 140.4 34.728 ;
    END
  END wd[90]
  PIN wd[91]
    DIRECTION OUTPUT ;
    USE SIGNAL ;
    PORT
      LAYER M4 ;
        RECT  140.316 34.8 140.4 34.824 ;
    END
  END wd[91]
  PIN wd[92]
    DIRECTION OUTPUT ;
    USE SIGNAL ;
    PORT
      LAYER M4 ;
        RECT  140.316 34.896 140.4 34.92 ;
    END
  END wd[92]
  PIN wd[93]
    DIRECTION OUTPUT ;
    USE SIGNAL ;
    PORT
      LAYER M4 ;
        RECT  140.316 34.992 140.4 35.016 ;
    END
  END wd[93]
  PIN wd[94]
    DIRECTION OUTPUT ;
    USE SIGNAL ;
    PORT
      LAYER M4 ;
        RECT  140.316 35.088 140.4 35.112 ;
    END
  END wd[94]
  PIN wd[95]
    DIRECTION OUTPUT ;
    USE SIGNAL ;
    PORT
      LAYER M4 ;
        RECT  140.316 35.184 140.4 35.208 ;
    END
  END wd[95]
  PIN wd[96]
    DIRECTION OUTPUT ;
    USE SIGNAL ;
    PORT
      LAYER M4 ;
        RECT  140.316 35.28 140.4 35.304 ;
    END
  END wd[96]
  PIN wd[97]
    DIRECTION OUTPUT ;
    USE SIGNAL ;
    PORT
      LAYER M4 ;
        RECT  140.316 35.376 140.4 35.4 ;
    END
  END wd[97]
  PIN wd[98]
    DIRECTION OUTPUT ;
    USE SIGNAL ;
    PORT
      LAYER M4 ;
        RECT  140.316 35.472 140.4 35.496 ;
    END
  END wd[98]
  PIN wd[99]
    DIRECTION OUTPUT ;
    USE SIGNAL ;
    PORT
      LAYER M4 ;
        RECT  140.316 35.568 140.4 35.592 ;
    END
  END wd[99]
  PIN wd[9]
    DIRECTION OUTPUT ;
    USE SIGNAL ;
    PORT
      LAYER M4 ;
        RECT  140.316 26.928 140.4 26.952 ;
    END
  END wd[9]
  PIN write_en
    DIRECTION INPUT ;
    USE SIGNAL ;
    PORT
      LAYER M5 ;
        RECT  21.936 88.476 21.96 88.56 ;
    END
  END write_en
  PIN write_slot[0]
    DIRECTION INPUT ;
    USE SIGNAL ;
    PORT
      LAYER M5 ;
        RECT  22.032 88.476 22.056 88.56 ;
    END
  END write_slot[0]
  PIN write_slot[1]
    DIRECTION INPUT ;
    USE SIGNAL ;
    PORT
      LAYER M5 ;
        RECT  22.128 88.476 22.152 88.56 ;
    END
  END write_slot[1]
  PIN write_slot[2]
    DIRECTION INPUT ;
    USE SIGNAL ;
    PORT
      LAYER M5 ;
        RECT  22.224 88.476 22.248 88.56 ;
    END
  END write_slot[2]
  PIN write_slot[3]
    DIRECTION INPUT ;
    USE SIGNAL ;
    PORT
      LAYER M5 ;
        RECT  22.32 88.476 22.344 88.56 ;
    END
  END write_slot[3]
  PIN write_slot[4]
    DIRECTION INPUT ;
    USE SIGNAL ;
    PORT
      LAYER M5 ;
        RECT  22.416 88.476 22.44 88.56 ;
    END
  END write_slot[4]
  PIN write_slot[5]
    DIRECTION INPUT ;
    USE SIGNAL ;
    PORT
      LAYER M5 ;
        RECT  22.512 88.476 22.536 88.56 ;
    END
  END write_slot[5]
  PIN write_slot[6]
    DIRECTION INPUT ;
    USE SIGNAL ;
    PORT
      LAYER M5 ;
        RECT  22.608 88.476 22.632 88.56 ;
    END
  END write_slot[6]
  PIN VDD
    DIRECTION INOUT ;
    USE POWER ;
    PORT
      LAYER M5 ;
        RECT  137.592 2.151 137.712 86.409 ;
        RECT  132.192 2.151 132.312 86.409 ;
        RECT  126.792 2.151 126.912 86.409 ;
        RECT  121.392 2.151 121.512 86.409 ;
        RECT  115.992 2.151 116.112 86.409 ;
        RECT  110.592 2.151 110.712 86.409 ;
        RECT  105.192 2.151 105.312 86.409 ;
        RECT  99.792 2.151 99.912 86.409 ;
        RECT  94.392 2.151 94.512 86.409 ;
        RECT  88.992 2.151 89.112 86.409 ;
        RECT  83.592 2.151 83.712 86.409 ;
        RECT  78.192 2.151 78.312 86.409 ;
        RECT  72.792 2.151 72.912 86.409 ;
        RECT  67.392 2.151 67.512 86.409 ;
        RECT  61.992 2.151 62.112 86.409 ;
        RECT  56.592 2.151 56.712 86.409 ;
        RECT  51.192 2.151 51.312 86.409 ;
        RECT  45.792 2.151 45.912 86.409 ;
        RECT  40.392 2.151 40.512 86.409 ;
        RECT  34.992 2.151 35.112 86.409 ;
        RECT  29.592 2.151 29.712 86.409 ;
        RECT  24.192 2.151 24.312 86.409 ;
        RECT  18.792 2.151 18.912 86.409 ;
        RECT  13.392 2.151 13.512 86.409 ;
        RECT  7.992 2.151 8.112 86.409 ;
        RECT  2.592 2.151 2.712 86.409 ;
    END
  END VDD
  PIN VSS
    DIRECTION INOUT ;
    USE GROUND ;
    PORT
      LAYER M5 ;
        RECT  137.4 2.137 137.52 86.423 ;
        RECT  132 2.137 132.12 86.423 ;
        RECT  126.6 2.137 126.72 86.423 ;
        RECT  121.2 2.137 121.32 86.423 ;
        RECT  115.8 2.137 115.92 86.423 ;
        RECT  110.4 2.137 110.52 86.423 ;
        RECT  105 2.137 105.12 86.423 ;
        RECT  99.6 2.137 99.72 86.423 ;
        RECT  94.2 2.137 94.32 86.423 ;
        RECT  88.8 2.137 88.92 86.423 ;
        RECT  83.4 2.137 83.52 86.423 ;
        RECT  78 2.137 78.12 86.423 ;
        RECT  72.6 2.137 72.72 86.423 ;
        RECT  67.2 2.137 67.32 86.423 ;
        RECT  61.8 2.137 61.92 86.423 ;
        RECT  56.4 2.137 56.52 86.423 ;
        RECT  51 2.137 51.12 86.423 ;
        RECT  45.6 2.137 45.72 86.423 ;
        RECT  40.2 2.137 40.32 86.423 ;
        RECT  34.8 2.137 34.92 86.423 ;
        RECT  29.4 2.137 29.52 86.423 ;
        RECT  24 2.137 24.12 86.423 ;
        RECT  18.6 2.137 18.72 86.423 ;
        RECT  13.2 2.137 13.32 86.423 ;
        RECT  7.8 2.137 7.92 86.423 ;
        RECT  2.4 2.137 2.52 86.423 ;
    END
  END VSS
  # OT_OBS_CLOSED layer=M5 d_um=1.536 added=126
  OBS
    LAYER RVTN ;
     RECT  2.16 2.16 138.24 2.295 ;
     RECT  2.16 2.565 138.24 2.835 ;
     RECT  2.16 3.105 138.24 3.375 ;
     RECT  2.16 3.645 138.24 3.915 ;
     RECT  2.16 4.185 138.24 4.455 ;
     RECT  2.16 4.725 138.24 4.995 ;
     RECT  2.16 5.265 138.24 5.535 ;
     RECT  2.16 5.805 138.24 6.075 ;
     RECT  2.16 6.345 138.24 6.615 ;
     RECT  2.16 6.885 138.24 7.155 ;
     RECT  2.16 7.425 138.24 7.695 ;
     RECT  2.16 7.965 138.24 8.235 ;
     RECT  2.16 8.505 138.24 8.775 ;
     RECT  2.16 9.045 138.24 9.315 ;
     RECT  2.16 9.585 138.24 9.855 ;
     RECT  2.16 10.125 138.24 10.395 ;
     RECT  2.16 10.665 138.24 10.935 ;
     RECT  2.16 11.205 138.24 11.475 ;
     RECT  2.16 11.745 138.24 12.015 ;
     RECT  2.16 12.285 138.24 12.555 ;
     RECT  2.16 12.825 138.24 13.095 ;
     RECT  2.16 13.365 138.24 13.635 ;
     RECT  2.16 13.905 138.24 14.175 ;
     RECT  2.16 14.445 138.24 14.715 ;
     RECT  2.16 14.985 138.24 15.255 ;
     RECT  2.16 15.525 138.24 15.795 ;
     RECT  2.16 16.065 138.24 16.335 ;
     RECT  2.16 16.605 138.24 16.875 ;
     RECT  2.16 17.145 138.24 17.415 ;
     RECT  2.16 17.685 138.24 17.955 ;
     RECT  2.16 18.225 138.24 18.495 ;
     RECT  2.16 18.765 138.24 19.035 ;
     RECT  2.16 19.305 138.24 19.575 ;
     RECT  2.16 19.845 138.24 20.115 ;
     RECT  2.16 20.385 138.24 20.655 ;
     RECT  2.16 20.925 138.24 21.195 ;
     RECT  2.16 21.465 138.24 21.6 ;
     RECT  2.16 21.6 20.412 21.735 ;
     RECT  119.34 21.6 138.24 21.735 ;
     RECT  2.16 22.005 20.412 22.275 ;
     RECT  119.34 22.005 138.24 22.275 ;
     RECT  2.16 22.545 20.412 22.815 ;
     RECT  119.34 22.545 138.24 22.815 ;
     RECT  2.16 23.085 20.412 23.355 ;
     RECT  119.34 23.085 138.24 23.355 ;
     RECT  2.16 23.625 20.412 23.895 ;
     RECT  119.34 23.625 138.24 23.895 ;
     RECT  2.16 24.165 20.412 24.435 ;
     RECT  119.34 24.165 138.24 24.435 ;
     RECT  2.16 24.705 20.412 24.975 ;
     RECT  119.34 24.705 138.24 24.975 ;
     RECT  2.16 25.245 20.412 25.515 ;
     RECT  119.34 25.245 138.24 25.515 ;
     RECT  2.16 25.785 20.412 26.055 ;
     RECT  119.34 25.785 138.24 26.055 ;
     RECT  2.16 26.325 20.412 26.595 ;
     RECT  119.34 26.325 138.24 26.595 ;
     RECT  2.16 26.865 20.412 27.135 ;
     RECT  119.34 26.865 138.24 27.135 ;
     RECT  2.16 27.405 20.412 27.675 ;
     RECT  119.34 27.405 138.24 27.675 ;
     RECT  2.16 27.945 20.412 28.215 ;
     RECT  119.34 27.945 138.24 28.215 ;
     RECT  2.16 28.485 20.412 28.755 ;
     RECT  119.34 28.485 138.24 28.755 ;
     RECT  2.16 29.025 20.412 29.295 ;
     RECT  119.34 29.025 138.24 29.295 ;
     RECT  2.16 29.565 20.412 29.835 ;
     RECT  119.34 29.565 138.24 29.835 ;
     RECT  2.16 30.105 20.412 30.375 ;
     RECT  119.34 30.105 138.24 30.375 ;
     RECT  2.16 30.645 20.412 30.915 ;
     RECT  119.34 30.645 138.24 30.915 ;
     RECT  2.16 31.185 20.412 31.455 ;
     RECT  119.34 31.185 138.24 31.455 ;
     RECT  2.16 31.725 20.412 31.995 ;
     RECT  119.34 31.725 138.24 31.995 ;
     RECT  2.16 32.265 20.412 32.535 ;
     RECT  119.34 32.265 138.24 32.535 ;
     RECT  2.16 32.805 20.412 33.075 ;
     RECT  119.34 32.805 138.24 33.075 ;
     RECT  2.16 33.345 20.412 33.615 ;
     RECT  119.34 33.345 138.24 33.615 ;
     RECT  2.16 33.885 20.412 34.155 ;
     RECT  119.34 33.885 138.24 34.155 ;
     RECT  2.16 34.425 20.412 34.695 ;
     RECT  119.34 34.425 138.24 34.695 ;
     RECT  2.16 34.965 20.412 35.235 ;
     RECT  119.34 34.965 138.24 35.235 ;
     RECT  2.16 35.505 20.412 35.775 ;
     RECT  119.34 35.505 138.24 35.775 ;
     RECT  2.16 36.045 20.412 36.315 ;
     RECT  119.34 36.045 138.24 36.315 ;
     RECT  2.16 36.585 20.412 36.855 ;
     RECT  119.34 36.585 138.24 36.855 ;
     RECT  2.16 37.125 20.412 37.395 ;
     RECT  119.34 37.125 138.24 37.395 ;
     RECT  2.16 37.665 20.412 37.935 ;
     RECT  119.34 37.665 138.24 37.935 ;
     RECT  2.16 38.205 20.412 38.475 ;
     RECT  119.34 38.205 138.24 38.475 ;
     RECT  2.16 38.745 20.412 39.015 ;
     RECT  119.34 38.745 138.24 39.015 ;
     RECT  2.16 39.285 20.412 39.555 ;
     RECT  119.34 39.285 138.24 39.555 ;
     RECT  2.16 39.825 20.412 40.095 ;
     RECT  119.34 39.825 138.24 40.095 ;
     RECT  2.16 40.365 20.412 40.635 ;
     RECT  119.34 40.365 138.24 40.635 ;
     RECT  2.16 40.905 20.412 41.175 ;
     RECT  119.34 40.905 138.24 41.175 ;
     RECT  2.16 41.445 20.412 41.715 ;
     RECT  119.34 41.445 138.24 41.715 ;
     RECT  2.16 41.985 20.412 42.255 ;
     RECT  119.34 41.985 138.24 42.255 ;
     RECT  2.16 42.525 20.412 42.795 ;
     RECT  119.34 42.525 138.24 42.795 ;
     RECT  2.16 43.065 20.412 43.335 ;
     RECT  119.34 43.065 138.24 43.335 ;
     RECT  2.16 43.605 20.412 43.875 ;
     RECT  119.34 43.605 138.24 43.875 ;
     RECT  2.16 44.145 20.412 44.415 ;
     RECT  119.34 44.145 138.24 44.415 ;
     RECT  2.16 44.685 20.412 44.955 ;
     RECT  119.34 44.685 138.24 44.955 ;
     RECT  2.16 45.225 20.412 45.495 ;
     RECT  119.34 45.225 138.24 45.495 ;
     RECT  2.16 45.765 20.412 46.035 ;
     RECT  119.34 45.765 138.24 46.035 ;
     RECT  2.16 46.305 20.412 46.575 ;
     RECT  119.34 46.305 138.24 46.575 ;
     RECT  2.16 46.845 20.412 47.115 ;
     RECT  119.34 46.845 138.24 47.115 ;
     RECT  2.16 47.385 20.412 47.655 ;
     RECT  119.34 47.385 138.24 47.655 ;
     RECT  2.16 47.925 20.412 48.195 ;
     RECT  119.34 47.925 138.24 48.195 ;
     RECT  2.16 48.465 20.412 48.735 ;
     RECT  119.34 48.465 138.24 48.735 ;
     RECT  2.16 49.005 20.412 49.275 ;
     RECT  119.34 49.005 138.24 49.275 ;
     RECT  2.16 49.545 20.412 49.815 ;
     RECT  119.34 49.545 138.24 49.815 ;
     RECT  2.16 50.085 20.412 50.355 ;
     RECT  119.34 50.085 138.24 50.355 ;
     RECT  2.16 50.625 20.412 50.895 ;
     RECT  119.34 50.625 138.24 50.895 ;
     RECT  2.16 51.165 20.412 51.435 ;
     RECT  119.34 51.165 138.24 51.435 ;
     RECT  2.16 51.705 20.412 51.975 ;
     RECT  119.34 51.705 138.24 51.975 ;
     RECT  2.16 52.245 20.412 52.515 ;
     RECT  119.34 52.245 138.24 52.515 ;
     RECT  2.16 52.785 20.412 53.055 ;
     RECT  119.34 52.785 138.24 53.055 ;
     RECT  2.16 53.325 20.412 53.595 ;
     RECT  119.34 53.325 138.24 53.595 ;
     RECT  2.16 53.865 20.412 54.135 ;
     RECT  119.34 53.865 138.24 54.135 ;
     RECT  2.16 54.405 20.412 54.675 ;
     RECT  119.34 54.405 138.24 54.675 ;
     RECT  2.16 54.945 20.412 55.215 ;
     RECT  119.34 54.945 138.24 55.215 ;
     RECT  2.16 55.485 20.412 55.755 ;
     RECT  119.34 55.485 138.24 55.755 ;
     RECT  2.16 56.025 20.412 56.295 ;
     RECT  119.34 56.025 138.24 56.295 ;
     RECT  2.16 56.565 20.412 56.835 ;
     RECT  119.34 56.565 138.24 56.835 ;
     RECT  2.16 57.105 20.412 57.375 ;
     RECT  119.34 57.105 138.24 57.375 ;
     RECT  2.16 57.645 20.412 57.915 ;
     RECT  119.34 57.645 138.24 57.915 ;
     RECT  2.16 58.185 20.412 58.455 ;
     RECT  119.34 58.185 138.24 58.455 ;
     RECT  2.16 58.725 20.412 58.995 ;
     RECT  119.34 58.725 138.24 58.995 ;
     RECT  2.16 59.265 20.412 59.535 ;
     RECT  119.34 59.265 138.24 59.535 ;
     RECT  2.16 59.805 20.412 60.075 ;
     RECT  119.34 59.805 138.24 60.075 ;
     RECT  2.16 60.345 20.412 60.615 ;
     RECT  119.34 60.345 138.24 60.615 ;
     RECT  2.16 60.885 20.412 61.155 ;
     RECT  119.34 60.885 138.24 61.155 ;
     RECT  2.16 61.425 20.412 61.695 ;
     RECT  119.34 61.425 138.24 61.695 ;
     RECT  2.16 61.965 20.412 62.235 ;
     RECT  119.34 61.965 138.24 62.235 ;
     RECT  2.16 62.505 20.412 62.775 ;
     RECT  119.34 62.505 138.24 62.775 ;
     RECT  2.16 63.045 20.412 63.315 ;
     RECT  119.34 63.045 138.24 63.315 ;
     RECT  2.16 63.585 20.412 63.855 ;
     RECT  119.34 63.585 138.24 63.855 ;
     RECT  2.16 64.125 20.412 64.395 ;
     RECT  119.34 64.125 138.24 64.395 ;
     RECT  2.16 64.665 20.412 64.935 ;
     RECT  119.34 64.665 138.24 64.935 ;
     RECT  2.16 65.205 20.412 65.475 ;
     RECT  119.34 65.205 138.24 65.475 ;
     RECT  2.16 65.745 20.412 66.015 ;
     RECT  119.34 65.745 138.24 66.015 ;
     RECT  2.16 66.285 20.412 66.555 ;
     RECT  119.34 66.285 138.24 66.555 ;
     RECT  2.16 66.825 20.412 66.96 ;
     RECT  119.34 66.825 138.24 66.96 ;
     RECT  2.16 66.96 138.24 67.095 ;
     RECT  2.16 67.365 138.24 67.635 ;
     RECT  2.16 67.905 138.24 68.175 ;
     RECT  2.16 68.445 138.24 68.715 ;
     RECT  2.16 68.985 138.24 69.255 ;
     RECT  2.16 69.525 138.24 69.795 ;
     RECT  2.16 70.065 138.24 70.335 ;
     RECT  2.16 70.605 138.24 70.875 ;
     RECT  2.16 71.145 138.24 71.415 ;
     RECT  2.16 71.685 138.24 71.955 ;
     RECT  2.16 72.225 138.24 72.495 ;
     RECT  2.16 72.765 138.24 73.035 ;
     RECT  2.16 73.305 138.24 73.575 ;
     RECT  2.16 73.845 138.24 74.115 ;
     RECT  2.16 74.385 138.24 74.655 ;
     RECT  2.16 74.925 138.24 75.195 ;
     RECT  2.16 75.465 138.24 75.735 ;
     RECT  2.16 76.005 138.24 76.275 ;
     RECT  2.16 76.545 138.24 76.815 ;
     RECT  2.16 77.085 138.24 77.355 ;
     RECT  2.16 77.625 138.24 77.895 ;
     RECT  2.16 78.165 138.24 78.435 ;
     RECT  2.16 78.705 138.24 78.975 ;
     RECT  2.16 79.245 138.24 79.515 ;
     RECT  2.16 79.785 138.24 80.055 ;
     RECT  2.16 80.325 138.24 80.595 ;
     RECT  2.16 80.865 138.24 81.135 ;
     RECT  2.16 81.405 138.24 81.675 ;
     RECT  2.16 81.945 138.24 82.215 ;
     RECT  2.16 82.485 138.24 82.755 ;
     RECT  2.16 83.025 138.24 83.295 ;
     RECT  2.16 83.565 138.24 83.835 ;
     RECT  2.16 84.105 138.24 84.375 ;
     RECT  2.16 84.645 138.24 84.915 ;
     RECT  2.16 85.185 138.24 85.455 ;
     RECT  2.16 85.725 138.24 85.995 ;
     RECT  2.16 86.265 138.24 86.4 ;
    LAYER RVTP ;
     RECT  2.16 2.295 138.24 2.565 ;
     RECT  2.16 2.835 138.24 3.105 ;
     RECT  2.16 3.375 138.24 3.645 ;
     RECT  2.16 3.915 138.24 4.185 ;
     RECT  2.16 4.455 138.24 4.725 ;
     RECT  2.16 4.995 138.24 5.265 ;
     RECT  2.16 5.535 138.24 5.805 ;
     RECT  2.16 6.075 138.24 6.345 ;
     RECT  2.16 6.615 138.24 6.885 ;
     RECT  2.16 7.155 138.24 7.425 ;
     RECT  2.16 7.695 138.24 7.965 ;
     RECT  2.16 8.235 138.24 8.505 ;
     RECT  2.16 8.775 138.24 9.045 ;
     RECT  2.16 9.315 138.24 9.585 ;
     RECT  2.16 9.855 138.24 10.125 ;
     RECT  2.16 10.395 138.24 10.665 ;
     RECT  2.16 10.935 138.24 11.205 ;
     RECT  2.16 11.475 138.24 11.745 ;
     RECT  2.16 12.015 138.24 12.285 ;
     RECT  2.16 12.555 138.24 12.825 ;
     RECT  2.16 13.095 138.24 13.365 ;
     RECT  2.16 13.635 138.24 13.905 ;
     RECT  2.16 14.175 138.24 14.445 ;
     RECT  2.16 14.715 138.24 14.985 ;
     RECT  2.16 15.255 138.24 15.525 ;
     RECT  2.16 15.795 138.24 16.065 ;
     RECT  2.16 16.335 138.24 16.605 ;
     RECT  2.16 16.875 138.24 17.145 ;
     RECT  2.16 17.415 138.24 17.685 ;
     RECT  2.16 17.955 138.24 18.225 ;
     RECT  2.16 18.495 138.24 18.765 ;
     RECT  2.16 19.035 138.24 19.305 ;
     RECT  2.16 19.575 138.24 19.845 ;
     RECT  2.16 20.115 138.24 20.385 ;
     RECT  2.16 20.655 138.24 20.925 ;
     RECT  2.16 21.195 138.24 21.465 ;
     RECT  2.16 21.735 20.412 22.005 ;
     RECT  119.34 21.735 138.24 22.005 ;
     RECT  2.16 22.275 20.412 22.545 ;
     RECT  119.34 22.275 138.24 22.545 ;
     RECT  2.16 22.815 20.412 23.085 ;
     RECT  119.34 22.815 138.24 23.085 ;
     RECT  2.16 23.355 20.412 23.625 ;
     RECT  119.34 23.355 138.24 23.625 ;
     RECT  2.16 23.895 20.412 24.165 ;
     RECT  119.34 23.895 138.24 24.165 ;
     RECT  2.16 24.435 20.412 24.705 ;
     RECT  119.34 24.435 138.24 24.705 ;
     RECT  2.16 24.975 20.412 25.245 ;
     RECT  119.34 24.975 138.24 25.245 ;
     RECT  2.16 25.515 20.412 25.785 ;
     RECT  119.34 25.515 138.24 25.785 ;
     RECT  2.16 26.055 20.412 26.325 ;
     RECT  119.34 26.055 138.24 26.325 ;
     RECT  2.16 26.595 20.412 26.865 ;
     RECT  119.34 26.595 138.24 26.865 ;
     RECT  2.16 27.135 20.412 27.405 ;
     RECT  119.34 27.135 138.24 27.405 ;
     RECT  2.16 27.675 20.412 27.945 ;
     RECT  119.34 27.675 138.24 27.945 ;
     RECT  2.16 28.215 20.412 28.485 ;
     RECT  119.34 28.215 138.24 28.485 ;
     RECT  2.16 28.755 20.412 29.025 ;
     RECT  119.34 28.755 138.24 29.025 ;
     RECT  2.16 29.295 20.412 29.565 ;
     RECT  119.34 29.295 138.24 29.565 ;
     RECT  2.16 29.835 20.412 30.105 ;
     RECT  119.34 29.835 138.24 30.105 ;
     RECT  2.16 30.375 20.412 30.645 ;
     RECT  119.34 30.375 138.24 30.645 ;
     RECT  2.16 30.915 20.412 31.185 ;
     RECT  119.34 30.915 138.24 31.185 ;
     RECT  2.16 31.455 20.412 31.725 ;
     RECT  119.34 31.455 138.24 31.725 ;
     RECT  2.16 31.995 20.412 32.265 ;
     RECT  119.34 31.995 138.24 32.265 ;
     RECT  2.16 32.535 20.412 32.805 ;
     RECT  119.34 32.535 138.24 32.805 ;
     RECT  2.16 33.075 20.412 33.345 ;
     RECT  119.34 33.075 138.24 33.345 ;
     RECT  2.16 33.615 20.412 33.885 ;
     RECT  119.34 33.615 138.24 33.885 ;
     RECT  2.16 34.155 20.412 34.425 ;
     RECT  119.34 34.155 138.24 34.425 ;
     RECT  2.16 34.695 20.412 34.965 ;
     RECT  119.34 34.695 138.24 34.965 ;
     RECT  2.16 35.235 20.412 35.505 ;
     RECT  119.34 35.235 138.24 35.505 ;
     RECT  2.16 35.775 20.412 36.045 ;
     RECT  119.34 35.775 138.24 36.045 ;
     RECT  2.16 36.315 20.412 36.585 ;
     RECT  119.34 36.315 138.24 36.585 ;
     RECT  2.16 36.855 20.412 37.125 ;
     RECT  119.34 36.855 138.24 37.125 ;
     RECT  2.16 37.395 20.412 37.665 ;
     RECT  119.34 37.395 138.24 37.665 ;
     RECT  2.16 37.935 20.412 38.205 ;
     RECT  119.34 37.935 138.24 38.205 ;
     RECT  2.16 38.475 20.412 38.745 ;
     RECT  119.34 38.475 138.24 38.745 ;
     RECT  2.16 39.015 20.412 39.285 ;
     RECT  119.34 39.015 138.24 39.285 ;
     RECT  2.16 39.555 20.412 39.825 ;
     RECT  119.34 39.555 138.24 39.825 ;
     RECT  2.16 40.095 20.412 40.365 ;
     RECT  119.34 40.095 138.24 40.365 ;
     RECT  2.16 40.635 20.412 40.905 ;
     RECT  119.34 40.635 138.24 40.905 ;
     RECT  2.16 41.175 20.412 41.445 ;
     RECT  119.34 41.175 138.24 41.445 ;
     RECT  2.16 41.715 20.412 41.985 ;
     RECT  119.34 41.715 138.24 41.985 ;
     RECT  2.16 42.255 20.412 42.525 ;
     RECT  119.34 42.255 138.24 42.525 ;
     RECT  2.16 42.795 20.412 43.065 ;
     RECT  119.34 42.795 138.24 43.065 ;
     RECT  2.16 43.335 20.412 43.605 ;
     RECT  119.34 43.335 138.24 43.605 ;
     RECT  2.16 43.875 20.412 44.145 ;
     RECT  119.34 43.875 138.24 44.145 ;
     RECT  2.16 44.415 20.412 44.685 ;
     RECT  119.34 44.415 138.24 44.685 ;
     RECT  2.16 44.955 20.412 45.225 ;
     RECT  119.34 44.955 138.24 45.225 ;
     RECT  2.16 45.495 20.412 45.765 ;
     RECT  119.34 45.495 138.24 45.765 ;
     RECT  2.16 46.035 20.412 46.305 ;
     RECT  119.34 46.035 138.24 46.305 ;
     RECT  2.16 46.575 20.412 46.845 ;
     RECT  119.34 46.575 138.24 46.845 ;
     RECT  2.16 47.115 20.412 47.385 ;
     RECT  119.34 47.115 138.24 47.385 ;
     RECT  2.16 47.655 20.412 47.925 ;
     RECT  119.34 47.655 138.24 47.925 ;
     RECT  2.16 48.195 20.412 48.465 ;
     RECT  119.34 48.195 138.24 48.465 ;
     RECT  2.16 48.735 20.412 49.005 ;
     RECT  119.34 48.735 138.24 49.005 ;
     RECT  2.16 49.275 20.412 49.545 ;
     RECT  119.34 49.275 138.24 49.545 ;
     RECT  2.16 49.815 20.412 50.085 ;
     RECT  119.34 49.815 138.24 50.085 ;
     RECT  2.16 50.355 20.412 50.625 ;
     RECT  119.34 50.355 138.24 50.625 ;
     RECT  2.16 50.895 20.412 51.165 ;
     RECT  119.34 50.895 138.24 51.165 ;
     RECT  2.16 51.435 20.412 51.705 ;
     RECT  119.34 51.435 138.24 51.705 ;
     RECT  2.16 51.975 20.412 52.245 ;
     RECT  119.34 51.975 138.24 52.245 ;
     RECT  2.16 52.515 20.412 52.785 ;
     RECT  119.34 52.515 138.24 52.785 ;
     RECT  2.16 53.055 20.412 53.325 ;
     RECT  119.34 53.055 138.24 53.325 ;
     RECT  2.16 53.595 20.412 53.865 ;
     RECT  119.34 53.595 138.24 53.865 ;
     RECT  2.16 54.135 20.412 54.405 ;
     RECT  119.34 54.135 138.24 54.405 ;
     RECT  2.16 54.675 20.412 54.945 ;
     RECT  119.34 54.675 138.24 54.945 ;
     RECT  2.16 55.215 20.412 55.485 ;
     RECT  119.34 55.215 138.24 55.485 ;
     RECT  2.16 55.755 20.412 56.025 ;
     RECT  119.34 55.755 138.24 56.025 ;
     RECT  2.16 56.295 20.412 56.565 ;
     RECT  119.34 56.295 138.24 56.565 ;
     RECT  2.16 56.835 20.412 57.105 ;
     RECT  119.34 56.835 138.24 57.105 ;
     RECT  2.16 57.375 20.412 57.645 ;
     RECT  119.34 57.375 138.24 57.645 ;
     RECT  2.16 57.915 20.412 58.185 ;
     RECT  119.34 57.915 138.24 58.185 ;
     RECT  2.16 58.455 20.412 58.725 ;
     RECT  119.34 58.455 138.24 58.725 ;
     RECT  2.16 58.995 20.412 59.265 ;
     RECT  119.34 58.995 138.24 59.265 ;
     RECT  2.16 59.535 20.412 59.805 ;
     RECT  119.34 59.535 138.24 59.805 ;
     RECT  2.16 60.075 20.412 60.345 ;
     RECT  119.34 60.075 138.24 60.345 ;
     RECT  2.16 60.615 20.412 60.885 ;
     RECT  119.34 60.615 138.24 60.885 ;
     RECT  2.16 61.155 20.412 61.425 ;
     RECT  119.34 61.155 138.24 61.425 ;
     RECT  2.16 61.695 20.412 61.965 ;
     RECT  119.34 61.695 138.24 61.965 ;
     RECT  2.16 62.235 20.412 62.505 ;
     RECT  119.34 62.235 138.24 62.505 ;
     RECT  2.16 62.775 20.412 63.045 ;
     RECT  119.34 62.775 138.24 63.045 ;
     RECT  2.16 63.315 20.412 63.585 ;
     RECT  119.34 63.315 138.24 63.585 ;
     RECT  2.16 63.855 20.412 64.125 ;
     RECT  119.34 63.855 138.24 64.125 ;
     RECT  2.16 64.395 20.412 64.665 ;
     RECT  119.34 64.395 138.24 64.665 ;
     RECT  2.16 64.935 20.412 65.205 ;
     RECT  119.34 64.935 138.24 65.205 ;
     RECT  2.16 65.475 20.412 65.745 ;
     RECT  119.34 65.475 138.24 65.745 ;
     RECT  2.16 66.015 20.412 66.285 ;
     RECT  119.34 66.015 138.24 66.285 ;
     RECT  2.16 66.555 20.412 66.825 ;
     RECT  119.34 66.555 138.24 66.825 ;
     RECT  2.16 67.095 138.24 67.365 ;
     RECT  2.16 67.635 138.24 67.905 ;
     RECT  2.16 68.175 138.24 68.445 ;
     RECT  2.16 68.715 138.24 68.985 ;
     RECT  2.16 69.255 138.24 69.525 ;
     RECT  2.16 69.795 138.24 70.065 ;
     RECT  2.16 70.335 138.24 70.605 ;
     RECT  2.16 70.875 138.24 71.145 ;
     RECT  2.16 71.415 138.24 71.685 ;
     RECT  2.16 71.955 138.24 72.225 ;
     RECT  2.16 72.495 138.24 72.765 ;
     RECT  2.16 73.035 138.24 73.305 ;
     RECT  2.16 73.575 138.24 73.845 ;
     RECT  2.16 74.115 138.24 74.385 ;
     RECT  2.16 74.655 138.24 74.925 ;
     RECT  2.16 75.195 138.24 75.465 ;
     RECT  2.16 75.735 138.24 76.005 ;
     RECT  2.16 76.275 138.24 76.545 ;
     RECT  2.16 76.815 138.24 77.085 ;
     RECT  2.16 77.355 138.24 77.625 ;
     RECT  2.16 77.895 138.24 78.165 ;
     RECT  2.16 78.435 138.24 78.705 ;
     RECT  2.16 78.975 138.24 79.245 ;
     RECT  2.16 79.515 138.24 79.785 ;
     RECT  2.16 80.055 138.24 80.325 ;
     RECT  2.16 80.595 138.24 80.865 ;
     RECT  2.16 81.135 138.24 81.405 ;
     RECT  2.16 81.675 138.24 81.945 ;
     RECT  2.16 82.215 138.24 82.485 ;
     RECT  2.16 82.755 138.24 83.025 ;
     RECT  2.16 83.295 138.24 83.565 ;
     RECT  2.16 83.835 138.24 84.105 ;
     RECT  2.16 84.375 138.24 84.645 ;
     RECT  2.16 84.915 138.24 85.185 ;
     RECT  2.16 85.455 138.24 85.725 ;
     RECT  2.16 85.995 138.24 86.265 ;
    LAYER M1 ;
     RECT  2.16 2.151 138.24 21.609 ;
     RECT  22.464 23.76 117.288 64.824 ;
     RECT  2.16 21.609 20.412 66.951 ;
     RECT  119.34 21.609 138.24 66.951 ;
     RECT  2.16 66.951 138.24 86.409 ;
    LAYER M2 ;
     RECT  0.103 26.802 0.139 27.09 ;
     RECT  0.103 37.872 0.139 37.89 ;
     RECT  0.103 52.182 0.139 54.774 ;
     RECT  0.103 56.232 0.139 56.25 ;
     RECT  0.103 57.312 0.139 57.87 ;
     RECT  0.103 58.662 0.139 59.526 ;
     RECT  0.103 60.282 0.139 60.84 ;
     RECT  0.103 22.086 0.175 24.93 ;
     RECT  0.103 50.562 0.175 51.39 ;
     RECT  0.139 52.182 0.347 55.242 ;
     RECT  0.175 21.942 0.499 24.93 ;
     RECT  0.103 35.712 0.499 35.73 ;
     RECT  0.139 36.792 0.499 36.81 ;
     RECT  0.103 21.132 0.535 21.15 ;
     RECT  0.499 21.906 0.535 25.002 ;
     RECT  0.139 25.992 0.535 26.01 ;
     RECT  0.103 31.158 0.535 33.3 ;
     RECT  0.103 34.092 0.535 34.65 ;
     RECT  0.499 35.712 0.535 36.81 ;
     RECT  0.175 50.022 0.535 51.39 ;
     RECT  0.347 52.182 0.535 54.774 ;
     RECT  0.139 56.034 0.535 56.25 ;
     RECT  0.139 57.312 0.535 60.84 ;
     RECT  0.103 61.704 0.535 61.722 ;
     RECT  0.139 26.802 1.147 27.36 ;
     RECT  0.535 30.96 1.147 36.81 ;
     RECT  0.139 37.602 1.147 37.89 ;
     RECT  0.535 56.034 1.147 61.722 ;
     RECT  0.535 20.97 1.183 26.01 ;
     RECT  1.147 26.802 1.183 27.63 ;
     RECT  1.147 63.522 1.183 63.54 ;
     RECT  1.183 20.97 1.219 27.774 ;
     RECT  1.147 30.96 1.219 37.89 ;
     RECT  1.183 63.126 1.219 63.54 ;
     RECT  1.219 20.97 1.723 28.278 ;
     RECT  1.219 30.96 1.723 38.16 ;
     RECT  1.723 20.862 2.16 28.278 ;
     RECT  1.723 30.852 2.16 38.16 ;
     RECT  0.535 50.022 2.16 54.774 ;
     RECT  1.147 56.034 2.16 62.19 ;
     RECT  1.219 62.982 2.16 63.54 ;
     RECT  2.16 2.151 21.011 86.409 ;
     RECT  21.011 2.151 21.659 63.882 ;
     RECT  21.659 29.61 21.695 56.484 ;
     RECT  21.695 29.61 21.731 54.234 ;
     RECT  21.659 2.151 22.464 28.854 ;
     RECT  21.731 29.61 22.464 51.732 ;
     RECT  21.731 52.56 22.464 54.234 ;
     RECT  21.695 55.116 22.464 56.484 ;
     RECT  21.659 57.384 22.464 63.882 ;
     RECT  21.011 64.872 22.464 86.409 ;
     RECT  22.464 2.151 117.288 86.409 ;
     RECT  117.288 2.151 118.111 25.308 ;
     RECT  117.288 26.064 118.111 26.784 ;
     RECT  118.111 2.151 118.543 26.784 ;
     RECT  117.288 28.296 118.579 63.774 ;
     RECT  118.543 2.151 118.903 27.198 ;
     RECT  118.903 2.151 118.939 27.234 ;
     RECT  118.579 28.26 118.939 63.774 ;
     RECT  118.939 2.151 119.34 63.774 ;
     RECT  117.288 64.674 119.34 86.409 ;
     RECT  119.34 2.151 138.24 86.409 ;
     RECT  138.24 22.32 138.479 24.624 ;
     RECT  138.479 22.32 138.515 23.814 ;
     RECT  138.24 25.758 138.515 34.686 ;
     RECT  138.24 18.936 138.623 21.564 ;
     RECT  138.515 25.956 139.019 34.686 ;
     RECT  138.24 35.676 139.019 52.974 ;
     RECT  138.623 20.124 139.055 21.564 ;
     RECT  139.019 49.014 139.055 52.974 ;
     RECT  139.055 20.124 139.091 21.492 ;
     RECT  138.515 23.058 139.091 23.814 ;
     RECT  139.019 35.676 139.091 48.15 ;
     RECT  139.055 49.248 139.091 52.812 ;
     RECT  139.019 25.956 139.127 32.796 ;
     RECT  139.019 33.624 139.127 34.686 ;
     RECT  139.091 35.676 139.127 36.774 ;
     RECT  139.091 37.566 139.127 48.114 ;
     RECT  139.091 20.124 139.163 21.42 ;
     RECT  138.479 24.606 139.379 24.624 ;
     RECT  139.091 51.138 139.523 52.812 ;
     RECT  139.127 26.298 139.595 31.014 ;
     RECT  139.163 20.124 139.631 20.142 ;
     RECT  139.163 20.898 139.631 21.42 ;
     RECT  139.595 26.298 139.631 28.944 ;
     RECT  139.523 51.408 139.631 52.812 ;
     RECT  138.623 18.936 139.667 18.954 ;
     RECT  139.631 27.414 139.667 28.944 ;
     RECT  139.595 29.736 139.667 31.014 ;
     RECT  139.631 51.876 139.667 52.812 ;
     RECT  139.667 51.876 139.703 52.236 ;
     RECT  139.127 31.806 139.999 32.796 ;
     RECT  139.999 31.806 140.143 33.444 ;
     RECT  139.127 34.326 140.143 34.686 ;
     RECT  140.143 31.806 140.171 34.686 ;
     RECT  139.127 37.566 140.171 45.486 ;
     RECT  139.127 46.314 140.207 48.114 ;
     RECT  140.171 33.588 140.215 34.686 ;
     RECT  140.171 37.566 140.243 45.324 ;
     RECT  140.207 46.314 140.243 46.764 ;
     RECT  139.667 29.736 140.279 30.402 ;
     RECT  140.215 33.588 140.279 35.424 ;
     RECT  140.243 37.566 140.279 40.698 ;
     RECT  140.243 41.616 140.279 42.444 ;
     RECT  140.243 43.416 140.279 45.324 ;
     RECT  140.243 46.314 140.279 46.494 ;
     RECT  140.207 47.628 140.279 48.114 ;
     RECT  139.091 49.248 140.279 49.734 ;
     RECT  139.703 51.876 140.279 52.164 ;
     RECT  139.631 20.898 140.315 20.916 ;
     RECT  139.091 23.058 140.315 23.076 ;
     RECT  139.631 26.298 140.315 26.316 ;
     RECT  139.667 27.648 140.315 28.944 ;
     RECT  140.279 29.736 140.315 29.754 ;
     RECT  140.171 31.806 140.315 32.796 ;
     RECT  140.279 34.326 140.315 35.424 ;
     RECT  139.127 36.756 140.315 36.774 ;
     RECT  140.279 38.106 140.315 38.124 ;
     RECT  140.279 39.258 140.315 40.698 ;
     RECT  140.279 41.616 140.315 41.634 ;
     RECT  140.279 42.426 140.315 42.444 ;
     RECT  140.279 43.416 140.315 45.144 ;
     RECT  140.279 46.476 140.315 46.494 ;
     RECT  140.279 48.096 140.315 48.114 ;
     RECT  140.279 49.248 140.315 49.374 ;
     RECT  140.279 51.876 140.315 51.894 ;
    LAYER M3 ;
     RECT  2.415 2.143 2.505 2.413 ;
     RECT  7.815 2.143 7.905 2.413 ;
     RECT  13.215 2.143 13.305 2.413 ;
     RECT  18.615 2.143 18.705 2.413 ;
     RECT  24.015 2.143 24.105 2.413 ;
     RECT  29.415 2.143 29.505 2.413 ;
     RECT  34.815 2.143 34.905 2.413 ;
     RECT  40.215 2.143 40.305 2.413 ;
     RECT  45.615 2.143 45.705 2.413 ;
     RECT  51.015 2.143 51.105 2.413 ;
     RECT  56.415 2.143 56.505 2.413 ;
     RECT  61.815 2.143 61.905 2.413 ;
     RECT  67.215 2.143 67.305 2.413 ;
     RECT  72.615 2.143 72.705 2.413 ;
     RECT  78.015 2.143 78.105 2.413 ;
     RECT  83.415 2.143 83.505 2.413 ;
     RECT  88.815 2.143 88.905 2.413 ;
     RECT  94.215 2.143 94.305 2.413 ;
     RECT  99.615 2.143 99.705 2.413 ;
     RECT  105.015 2.143 105.105 2.413 ;
     RECT  110.415 2.143 110.505 2.413 ;
     RECT  115.815 2.143 115.905 2.413 ;
     RECT  121.215 2.143 121.305 2.413 ;
     RECT  126.615 2.143 126.705 2.413 ;
     RECT  132.015 2.143 132.105 2.413 ;
     RECT  137.415 2.143 137.505 2.413 ;
     RECT  22.356 9.481 22.374 9.533 ;
     RECT  21.24 9.499 21.258 9.545 ;
     RECT  22.176 10.021 22.194 10.061 ;
     RECT  24.015 2.413 24.297 10.12 ;
     RECT  23.292 10.12 24.297 10.157 ;
     RECT  26.748 10.027 26.766 10.157 ;
     RECT  118.584 10.027 118.602 10.157 ;
     RECT  121.215 2.413 121.497 10.459 ;
     RECT  12.456 10.315 12.474 10.561 ;
     RECT  13.215 2.413 13.497 10.561 ;
     RECT  25.056 10.459 25.074 10.589 ;
     RECT  12.456 10.561 13.497 10.597 ;
     RECT  12.276 10.597 13.497 10.637 ;
     RECT  18.615 2.413 18.897 10.651 ;
     RECT  18.072 10.651 19.206 10.699 ;
     RECT  20.592 10.696 20.61 10.733 ;
     RECT  40.215 2.413 40.497 10.741 ;
     RECT  18.072 10.699 19.494 10.769 ;
     RECT  34.815 2.413 35.097 10.831 ;
     RECT  45.615 2.413 45.897 10.831 ;
     RECT  56.415 2.413 56.697 10.831 ;
     RECT  67.215 2.413 67.497 10.831 ;
     RECT  78.015 2.413 78.297 10.831 ;
     RECT  88.815 2.413 89.097 10.831 ;
     RECT  99.615 2.413 99.897 10.831 ;
     RECT  110.415 2.413 110.697 10.831 ;
     RECT  45.504 10.831 45.897 10.877 ;
     RECT  56.304 10.831 56.697 10.877 ;
     RECT  67.104 10.831 67.497 10.877 ;
     RECT  77.904 10.831 78.297 10.877 ;
     RECT  88.704 10.831 89.097 10.877 ;
     RECT  99.504 10.831 99.897 10.877 ;
     RECT  110.304 10.831 110.697 10.877 ;
     RECT  15.156 10.411 15.174 10.891 ;
     RECT  29.415 2.413 29.697 10.987 ;
     RECT  61.815 2.413 62.097 10.987 ;
     RECT  67.215 10.877 67.497 10.987 ;
     RECT  110.415 10.877 110.697 10.987 ;
     RECT  29.415 10.987 29.898 11.039 ;
     RECT  67.215 10.987 67.662 11.039 ;
     RECT  110.415 10.987 110.862 11.039 ;
     RECT  26.496 10.987 26.802 11.083 ;
     RECT  14.796 10.891 15.174 11.101 ;
     RECT  26.496 11.083 27.522 11.101 ;
     RECT  29.415 11.039 29.79 11.117 ;
     RECT  106.596 10.987 106.722 11.117 ;
     RECT  26.388 11.101 27.522 11.129 ;
     RECT  45.615 10.877 45.897 11.137 ;
     RECT  56.415 10.877 56.697 11.137 ;
     RECT  78.015 10.877 78.297 11.137 ;
     RECT  88.815 10.877 89.097 11.137 ;
     RECT  99.615 10.877 99.897 11.137 ;
     RECT  42.768 11.083 42.786 11.179 ;
     RECT  54.72 11.083 54.738 11.179 ;
     RECT  74.664 11.083 74.682 11.179 ;
     RECT  86.652 11.083 86.67 11.179 ;
     RECT  98.604 11.083 98.622 11.179 ;
     RECT  106.704 11.117 106.722 11.179 ;
     RECT  14.76 11.101 15.714 11.213 ;
     RECT  26.388 11.129 27.342 11.213 ;
     RECT  42.768 11.179 42.894 11.213 ;
     RECT  45.615 11.137 45.918 11.213 ;
     RECT  54.72 11.179 54.846 11.213 ;
     RECT  56.415 11.137 56.718 11.213 ;
     RECT  67.215 11.039 67.554 11.213 ;
     RECT  74.664 11.179 74.79 11.213 ;
     RECT  78.015 11.137 78.318 11.213 ;
     RECT  86.652 11.179 86.778 11.213 ;
     RECT  88.815 11.137 89.118 11.213 ;
     RECT  98.604 11.179 98.73 11.213 ;
     RECT  99.615 11.137 99.918 11.213 ;
     RECT  106.704 11.179 106.83 11.213 ;
     RECT  110.415 11.039 110.754 11.213 ;
     RECT  18.615 10.769 19.494 11.227 ;
     RECT  18.615 11.227 19.53 11.273 ;
     RECT  12.312 10.637 13.497 11.281 ;
     RECT  120.96 10.459 121.497 11.281 ;
     RECT  30.672 11.179 30.69 11.309 ;
     RECT  42.876 11.213 42.894 11.309 ;
     RECT  54.828 11.213 54.846 11.309 ;
     RECT  61.815 10.987 62.874 11.309 ;
     RECT  74.772 11.213 74.79 11.309 ;
     RECT  86.76 11.213 86.778 11.309 ;
     RECT  98.712 11.213 98.73 11.309 ;
     RECT  106.812 11.213 106.83 11.309 ;
     RECT  118.584 11.179 118.602 11.309 ;
     RECT  12.312 11.281 14.022 11.357 ;
     RECT  22.824 10.987 22.95 11.357 ;
     RECT  62.856 11.309 62.874 11.357 ;
     RECT  20.628 11.227 20.646 11.371 ;
     RECT  14.796 11.213 15.714 11.399 ;
     RECT  27.324 11.213 27.342 11.399 ;
     RECT  19.692 11.371 19.71 11.408 ;
     RECT  25.74 11.371 25.758 11.408 ;
     RECT  23.904 10.157 24.297 11.515 ;
     RECT  22.176 11.515 22.194 11.669 ;
     RECT  23.292 11.515 24.297 11.669 ;
     RECT  11.376 11.641 11.394 11.693 ;
     RECT  16.812 11.128 16.83 11.741 ;
     RECT  12.312 11.357 13.518 11.749 ;
     RECT  19.836 11.467 19.854 11.803 ;
     RECT  20.628 11.371 20.826 11.803 ;
     RECT  45.615 11.213 45.897 11.803 ;
     RECT  56.415 11.213 56.697 11.803 ;
     RECT  67.215 11.213 67.497 11.803 ;
     RECT  78.015 11.213 78.297 11.803 ;
     RECT  88.815 11.213 89.097 11.803 ;
     RECT  99.615 11.213 99.897 11.803 ;
     RECT  110.415 11.213 110.697 11.803 ;
     RECT  12.276 11.749 13.518 11.849 ;
     RECT  19.836 11.803 21.906 11.849 ;
     RECT  23.904 11.669 24.297 11.849 ;
     RECT  34.704 10.831 35.097 11.849 ;
     RECT  45.504 11.803 45.897 11.849 ;
     RECT  56.304 11.803 56.697 11.849 ;
     RECT  67.104 11.803 67.497 11.849 ;
     RECT  77.904 11.803 78.297 11.849 ;
     RECT  88.704 11.803 89.097 11.849 ;
     RECT  99.504 11.803 99.897 11.849 ;
     RECT  110.304 11.803 110.697 11.849 ;
     RECT  10.548 11.821 10.566 11.885 ;
     RECT  15.156 11.399 15.714 11.981 ;
     RECT  20.952 11.849 20.97 11.981 ;
     RECT  119.016 11.803 119.034 11.981 ;
     RECT  18.615 11.273 18.897 12.181 ;
     RECT  12.276 11.849 12.474 12.283 ;
     RECT  26.64 12.187 26.658 12.317 ;
     RECT  118.656 12.187 118.674 12.317 ;
     RECT  21.888 11.849 21.906 12.451 ;
     RECT  18.615 12.181 19.062 12.475 ;
     RECT  19.836 11.849 20.178 12.475 ;
     RECT  22.824 12.283 23.094 12.479 ;
     RECT  22.824 12.479 22.878 12.509 ;
     RECT  120.564 11.281 121.497 12.523 ;
     RECT  13.215 11.849 13.518 12.619 ;
     RECT  122.976 11.371 122.994 12.763 ;
     RECT  118.584 12.619 118.602 12.797 ;
     RECT  24.015 11.849 24.297 12.811 ;
     RECT  25.668 12.793 25.686 12.811 ;
     RECT  20.916 12.571 20.934 12.829 ;
     RECT  21.888 12.451 21.978 12.829 ;
     RECT  120.024 12.523 121.497 12.829 ;
     RECT  12.24 12.283 12.474 12.859 ;
     RECT  13.215 12.619 13.59 12.859 ;
     RECT  15.156 11.981 15.174 12.859 ;
     RECT  18.615 12.475 20.178 12.859 ;
     RECT  20.916 12.829 21.978 12.859 ;
     RECT  18.615 12.859 21.978 12.865 ;
     RECT  36.9 11.281 36.918 12.865 ;
     RECT  36.864 12.865 36.918 12.901 ;
     RECT  124.452 10.741 124.47 12.901 ;
     RECT  12.24 12.859 13.59 12.991 ;
     RECT  24.015 12.811 24.498 12.991 ;
     RECT  34.815 11.849 35.097 12.991 ;
     RECT  45.615 11.849 45.897 12.991 ;
     RECT  56.415 11.849 56.697 12.991 ;
     RECT  67.215 11.849 67.497 12.991 ;
     RECT  78.015 11.849 78.297 12.991 ;
     RECT  88.815 11.849 89.097 12.991 ;
     RECT  99.615 11.849 99.897 12.991 ;
     RECT  110.415 11.849 110.697 12.991 ;
     RECT  18.615 12.865 22.086 13.019 ;
     RECT  25.596 12.811 25.686 13.019 ;
     RECT  22.86 12.509 22.878 13.055 ;
     RECT  25.668 13.019 25.686 13.055 ;
     RECT  126.615 2.413 126.897 13.063 ;
     RECT  18.615 13.019 20.214 13.085 ;
     RECT  18.615 13.085 19.962 13.091 ;
     RECT  117.684 11.947 117.702 13.147 ;
     RECT  12.24 12.991 14.022 13.339 ;
     RECT  117.144 13.147 117.702 13.339 ;
     RECT  12.24 13.339 14.202 13.531 ;
     RECT  15.12 12.859 15.174 13.531 ;
     RECT  19.872 13.091 19.962 13.559 ;
     RECT  31.284 13.387 31.302 13.559 ;
     RECT  32.4 13.387 32.418 13.559 ;
     RECT  23.904 12.991 24.498 13.567 ;
     RECT  17.64 13.531 17.658 13.613 ;
     RECT  114.768 13.435 114.786 13.613 ;
     RECT  117.036 13.339 117.702 13.613 ;
     RECT  23.724 13.567 24.498 13.627 ;
     RECT  10.872 12.523 10.89 13.639 ;
     RECT  119.844 12.829 121.497 13.639 ;
     RECT  23.724 13.627 24.858 13.661 ;
     RECT  23.904 13.661 24.858 13.739 ;
     RECT  12.24 13.531 15.174 13.867 ;
     RECT  21.06 13.019 22.086 13.915 ;
     RECT  12.24 13.867 15.822 13.981 ;
     RECT  43.596 12.901 43.614 13.981 ;
     RECT  34.704 12.991 35.097 13.997 ;
     RECT  114.588 13.867 114.606 13.997 ;
     RECT  45.504 12.991 45.897 14.009 ;
     RECT  56.304 12.991 56.697 14.009 ;
     RECT  67.104 12.991 67.497 14.009 ;
     RECT  77.904 12.991 78.297 14.009 ;
     RECT  88.704 12.991 89.097 14.009 ;
     RECT  99.504 12.991 99.897 14.009 ;
     RECT  110.304 12.991 110.697 14.009 ;
     RECT  10.872 13.639 11.322 14.071 ;
     RECT  18.615 13.091 18.897 14.107 ;
     RECT  119.7 13.639 121.497 14.107 ;
     RECT  17.424 14.071 17.442 14.141 ;
     RECT  18.54 14.107 18.897 14.144 ;
     RECT  6.696 11.419 6.714 14.203 ;
     RECT  7.815 2.413 8.097 14.203 ;
     RECT  18.612 14.144 18.897 14.207 ;
     RECT  10.836 14.071 11.322 14.243 ;
     RECT  18.615 14.207 18.897 14.347 ;
     RECT  119.196 14.107 121.497 14.347 ;
     RECT  22.824 14.347 22.842 14.477 ;
     RECT  26.748 14.44 26.766 14.477 ;
     RECT  27.864 14.341 27.882 14.477 ;
     RECT  30.744 14.347 30.762 14.477 ;
     RECT  117.684 13.613 117.702 14.485 ;
     RECT  12.204 13.981 15.822 14.521 ;
     RECT  115.815 2.413 116.097 14.521 ;
     RECT  20.952 13.915 22.086 14.611 ;
     RECT  23.904 13.739 24.297 14.611 ;
     RECT  117.684 14.485 117.738 14.647 ;
     RECT  19.872 13.559 19.89 14.683 ;
     RECT  20.952 14.611 22.626 14.683 ;
     RECT  23.508 14.611 24.297 14.717 ;
     RECT  10.872 14.243 11.322 14.755 ;
     RECT  9.036 10.843 9.054 14.791 ;
     RECT  9.936 14.215 9.954 14.791 ;
     RECT  117.144 14.647 117.738 14.791 ;
     RECT  118.584 14.347 121.497 14.791 ;
     RECT  18.615 14.347 18.99 14.953 ;
     RECT  19.872 14.683 22.626 14.953 ;
     RECT  18.615 14.953 22.626 14.971 ;
     RECT  10.872 14.755 11.466 15.151 ;
     RECT  34.815 13.997 35.097 15.151 ;
     RECT  45.615 14.009 45.897 15.151 ;
     RECT  56.415 14.009 56.697 15.151 ;
     RECT  67.215 14.009 67.497 15.151 ;
     RECT  78.015 14.009 78.297 15.151 ;
     RECT  88.815 14.009 89.097 15.151 ;
     RECT  99.615 14.009 99.897 15.151 ;
     RECT  110.415 14.009 110.697 15.151 ;
     RECT  117.144 14.791 121.497 15.187 ;
     RECT  6.696 14.203 8.097 15.259 ;
     RECT  9.036 14.791 9.954 15.259 ;
     RECT  128.124 15.019 128.142 15.259 ;
     RECT  6.696 15.259 9.954 15.295 ;
     RECT  10.836 15.151 11.466 15.295 ;
     RECT  6.696 15.295 11.466 15.331 ;
     RECT  12.204 14.521 16.29 15.331 ;
     RECT  38.448 11.371 38.466 15.451 ;
     RECT  131.076 15.307 131.094 15.499 ;
     RECT  122.544 12.763 122.994 15.547 ;
     RECT  38.448 15.451 38.79 15.691 ;
     RECT  40.032 10.741 40.497 15.691 ;
     RECT  42.912 13.981 43.614 15.691 ;
     RECT  114.588 15.451 114.606 15.691 ;
     RECT  34.704 15.151 35.097 15.725 ;
     RECT  110.304 15.151 110.697 15.725 ;
     RECT  23.904 14.717 24.297 15.728 ;
     RECT  45.504 15.151 45.897 15.728 ;
     RECT  56.304 15.151 56.697 15.728 ;
     RECT  67.104 15.151 67.497 15.728 ;
     RECT  77.904 15.151 78.297 15.728 ;
     RECT  88.704 15.151 89.097 15.728 ;
     RECT  99.504 15.151 99.897 15.728 ;
     RECT  126.54 13.063 126.897 15.763 ;
     RECT  38.448 15.691 40.497 15.821 ;
     RECT  42.624 15.691 43.614 15.821 ;
     RECT  114.588 15.691 114.714 15.821 ;
     RECT  132.015 2.413 132.297 15.835 ;
     RECT  117.144 15.187 121.59 16.075 ;
     RECT  122.544 15.547 123.39 16.075 ;
     RECT  126.54 15.763 127.134 16.105 ;
     RECT  6.696 15.331 16.29 16.141 ;
     RECT  114.588 15.821 114.606 16.157 ;
     RECT  17.892 14.971 22.626 16.339 ;
     RECT  124.452 12.901 124.758 16.339 ;
     RECT  125.82 16.105 127.134 16.339 ;
     RECT  131.976 15.835 132.297 16.363 ;
     RECT  117.144 16.075 123.39 16.397 ;
     RECT  124.452 16.339 127.134 16.501 ;
     RECT  128.124 15.259 128.646 16.501 ;
     RECT  129.42 16.411 129.438 16.651 ;
     RECT  36.864 12.901 36.99 16.681 ;
     RECT  38.448 15.821 38.466 16.771 ;
     RECT  40.032 15.821 40.497 16.771 ;
     RECT  6.696 16.141 16.794 16.843 ;
     RECT  38.448 16.771 38.538 16.877 ;
     RECT  39.312 16.771 40.497 16.877 ;
     RECT  117.144 16.397 121.59 16.879 ;
     RECT  131.076 15.499 131.166 16.939 ;
     RECT  131.976 16.363 132.75 16.939 ;
     RECT  115.776 14.521 116.097 17.077 ;
     RECT  116.856 16.879 121.59 17.077 ;
     RECT  129.42 16.651 129.474 17.077 ;
     RECT  115.776 17.077 121.59 17.117 ;
     RECT  17.82 16.339 22.626 17.221 ;
     RECT  42.912 15.821 43.614 17.221 ;
     RECT  61.815 11.309 62.097 17.221 ;
     RECT  110.415 15.725 110.697 17.221 ;
     RECT  24.015 15.728 24.297 17.311 ;
     RECT  34.815 15.725 35.097 17.311 ;
     RECT  45.615 15.728 45.897 17.311 ;
     RECT  56.415 15.728 56.697 17.311 ;
     RECT  67.215 15.728 67.497 17.311 ;
     RECT  78.015 15.728 78.297 17.311 ;
     RECT  88.815 15.728 89.097 17.311 ;
     RECT  99.615 15.728 99.897 17.311 ;
     RECT  110.415 17.221 110.718 17.311 ;
     RECT  131.076 16.939 132.75 17.323 ;
     RECT  17.82 17.221 22.878 17.339 ;
     RECT  30.852 17.221 30.87 17.339 ;
     RECT  54.792 17.221 54.81 17.339 ;
     RECT  61.815 17.221 62.766 17.339 ;
     RECT  74.736 17.221 74.754 17.339 ;
     RECT  86.688 17.221 86.706 17.339 ;
     RECT  98.676 17.221 98.694 17.339 ;
     RECT  106.668 17.221 106.686 17.339 ;
     RECT  110.304 17.311 110.718 17.339 ;
     RECT  6.696 16.843 16.974 17.347 ;
     RECT  17.82 17.339 22.842 17.347 ;
     RECT  124.452 16.501 128.646 17.419 ;
     RECT  129.384 17.077 129.474 17.419 ;
     RECT  130.536 17.323 132.75 17.453 ;
     RECT  38.448 16.877 38.466 17.761 ;
     RECT  42.804 17.221 43.614 17.761 ;
     RECT  6.696 17.347 22.842 17.879 ;
     RECT  30.78 17.761 30.798 17.879 ;
     RECT  54.72 17.761 54.738 17.879 ;
     RECT  61.815 17.339 62.73 17.879 ;
     RECT  74.664 17.761 74.682 17.879 ;
     RECT  86.652 17.761 86.67 17.879 ;
     RECT  98.604 17.761 98.622 17.879 ;
     RECT  106.596 17.761 106.614 17.879 ;
     RECT  34.704 17.311 35.097 17.885 ;
     RECT  110.304 17.339 110.697 17.885 ;
     RECT  38.34 17.761 38.466 17.887 ;
     RECT  45.504 17.311 45.897 17.888 ;
     RECT  56.304 17.311 56.697 17.888 ;
     RECT  67.104 17.311 67.497 17.888 ;
     RECT  77.904 17.311 78.297 17.888 ;
     RECT  88.704 17.311 89.097 17.888 ;
     RECT  99.504 17.311 99.897 17.888 ;
     RECT  115.776 17.117 116.097 17.959 ;
     RECT  117.072 17.117 121.59 17.959 ;
     RECT  23.904 17.311 24.297 18.121 ;
     RECT  42.768 17.761 43.614 18.427 ;
     RECT  41.868 16.123 41.886 18.463 ;
     RECT  42.768 18.427 43.686 18.463 ;
     RECT  39.276 17.887 39.294 18.535 ;
     RECT  40.032 16.877 40.497 18.535 ;
     RECT  41.832 18.463 41.886 18.535 ;
     RECT  42.768 18.463 44.37 18.535 ;
     RECT  38.268 17.887 38.466 18.571 ;
     RECT  6.696 17.879 22.662 18.661 ;
     RECT  23.652 18.121 24.297 18.661 ;
     RECT  36.216 16.681 36.99 18.661 ;
     RECT  37.8 18.571 38.466 18.661 ;
     RECT  39.276 18.535 40.497 18.697 ;
     RECT  6.696 18.661 24.426 18.701 ;
     RECT  36.216 18.661 38.466 18.733 ;
     RECT  39.276 18.697 40.806 18.733 ;
     RECT  124.452 17.419 129.474 18.805 ;
     RECT  130.284 17.851 130.302 18.805 ;
     RECT  23.652 18.701 24.354 18.989 ;
     RECT  41.832 18.535 44.37 19.039 ;
     RECT  115.776 17.959 121.59 19.075 ;
     RECT  122.544 16.397 123.39 19.075 ;
     RECT  137.415 2.413 137.697 19.075 ;
     RECT  137.415 19.075 137.97 19.111 ;
     RECT  113.04 19.099 113.058 19.277 ;
     RECT  124.452 18.805 130.302 19.291 ;
     RECT  131.076 17.453 132.75 19.291 ;
     RECT  137.376 19.111 137.97 19.345 ;
     RECT  6.696 18.701 22.662 19.471 ;
     RECT  34.815 17.885 35.097 19.471 ;
     RECT  45.615 17.888 45.897 19.471 ;
     RECT  56.415 17.888 56.697 19.471 ;
     RECT  67.215 17.888 67.497 19.471 ;
     RECT  78.015 17.888 78.297 19.471 ;
     RECT  88.815 17.888 89.097 19.471 ;
     RECT  99.615 17.888 99.897 19.471 ;
     RECT  110.415 17.885 110.697 19.471 ;
     RECT  6.696 19.471 22.842 19.615 ;
     RECT  45.504 19.471 45.897 19.651 ;
     RECT  56.304 19.471 56.697 19.651 ;
     RECT  61.815 17.879 62.097 19.651 ;
     RECT  67.104 19.471 67.497 19.651 ;
     RECT  77.904 19.471 78.297 19.651 ;
     RECT  88.704 19.471 89.097 19.651 ;
     RECT  99.504 19.471 99.897 19.651 ;
     RECT  110.304 19.471 110.697 19.651 ;
     RECT  136.764 19.345 137.97 19.651 ;
     RECT  6.696 19.615 22.878 19.741 ;
     RECT  23.904 18.989 24.354 19.741 ;
     RECT  34.704 19.471 35.097 19.741 ;
     RECT  2.415 2.413 2.697 19.813 ;
     RECT  135.468 19.111 135.486 19.885 ;
     RECT  136.512 19.651 138.618 19.885 ;
     RECT  2.415 19.813 3.222 19.912 ;
     RECT  4.068 19.885 4.41 19.912 ;
     RECT  30.78 19.741 30.798 19.913 ;
     RECT  34.704 19.741 35.154 19.913 ;
     RECT  45.504 19.651 45.954 19.913 ;
     RECT  54.72 19.651 54.738 19.913 ;
     RECT  56.304 19.651 56.754 19.913 ;
     RECT  61.815 19.651 62.73 19.913 ;
     RECT  67.104 19.651 67.554 19.913 ;
     RECT  74.664 19.651 74.682 19.913 ;
     RECT  77.904 19.651 78.354 19.913 ;
     RECT  86.652 19.651 86.67 19.913 ;
     RECT  88.704 19.651 89.154 19.913 ;
     RECT  98.604 19.651 98.622 19.913 ;
     RECT  99.504 19.651 99.954 19.913 ;
     RECT  106.596 19.651 106.614 19.913 ;
     RECT  110.304 19.651 110.754 19.913 ;
     RECT  2.415 19.912 4.41 19.915 ;
     RECT  2.304 19.915 4.41 19.921 ;
     RECT  5.364 19.915 5.382 19.921 ;
     RECT  139.644 18.931 139.662 19.949 ;
     RECT  2.304 19.921 5.382 19.955 ;
     RECT  2.415 19.955 5.382 20.011 ;
     RECT  6.696 19.741 22.914 20.047 ;
     RECT  26.748 20.011 26.766 20.141 ;
     RECT  112.86 20.011 112.878 20.141 ;
     RECT  139.608 20.107 139.626 20.147 ;
     RECT  2.415 20.011 5.85 20.155 ;
     RECT  6.696 20.047 23.094 20.155 ;
     RECT  135.468 19.885 138.618 20.191 ;
     RECT  2.415 20.155 23.094 20.281 ;
     RECT  23.904 19.741 24.39 20.281 ;
     RECT  134.82 20.191 139.158 20.309 ;
     RECT  133.776 20.425 133.794 20.461 ;
     RECT  113.004 20.347 113.022 20.477 ;
     RECT  34.704 19.913 35.097 20.489 ;
     RECT  45.504 19.913 45.897 20.489 ;
     RECT  56.304 19.913 56.697 20.489 ;
     RECT  67.104 19.913 67.497 20.489 ;
     RECT  77.904 19.913 78.297 20.489 ;
     RECT  88.704 19.913 89.097 20.489 ;
     RECT  99.504 19.913 99.897 20.489 ;
     RECT  110.304 19.913 110.697 20.489 ;
     RECT  124.452 19.291 132.75 20.491 ;
     RECT  133.596 20.461 133.794 20.491 ;
     RECT  2.415 20.281 24.39 20.587 ;
     RECT  34.776 20.489 35.097 20.659 ;
     RECT  2.415 20.587 25.038 20.723 ;
     RECT  34.776 20.659 35.154 20.849 ;
     RECT  2.415 20.723 24.966 20.857 ;
     RECT  1.728 20.857 24.966 20.885 ;
     RECT  1.728 20.885 24.822 20.909 ;
     RECT  140.292 20.875 140.31 20.921 ;
     RECT  124.452 20.491 133.794 21.001 ;
     RECT  36.216 18.733 40.806 21.119 ;
     RECT  41.544 19.039 44.37 21.119 ;
     RECT  0.54 20.965 0.558 21.127 ;
     RECT  124.452 21.001 134.226 21.127 ;
     RECT  135.216 20.309 139.158 21.127 ;
     RECT  37.8 21.119 40.806 21.235 ;
     RECT  41.544 21.119 41.886 21.235 ;
     RECT  32.256 19.003 32.274 21.271 ;
     RECT  29.415 11.117 29.697 21.347 ;
     RECT  34.776 20.849 35.097 21.347 ;
     RECT  45.615 20.489 45.897 21.347 ;
     RECT  51.015 2.413 51.297 21.347 ;
     RECT  56.415 20.489 56.697 21.347 ;
     RECT  61.815 19.913 62.097 21.347 ;
     RECT  67.215 20.489 67.497 21.347 ;
     RECT  72.615 2.413 72.897 21.347 ;
     RECT  78.015 20.489 78.297 21.347 ;
     RECT  83.415 2.413 83.697 21.347 ;
     RECT  88.815 20.489 89.097 21.347 ;
     RECT  94.215 2.413 94.497 21.347 ;
     RECT  99.615 20.489 99.897 21.347 ;
     RECT  105.015 2.413 105.297 21.347 ;
     RECT  110.415 20.489 110.697 21.347 ;
     RECT  124.452 21.127 139.158 21.355 ;
     RECT  31.572 21.271 32.274 21.389 ;
     RECT  36.216 21.119 36.99 21.389 ;
     RECT  37.8 21.235 41.886 21.389 ;
     RECT  42.912 21.119 44.37 21.389 ;
     RECT  124.452 21.355 139.626 21.425 ;
     RECT  23.688 20.909 24.822 21.437 ;
     RECT  37.8 21.389 37.962 21.461 ;
     RECT  23.688 21.437 24.105 21.485 ;
     RECT  25.956 21.361 25.974 21.485 ;
     RECT  27.072 21.433 27.162 21.485 ;
     RECT  37.872 21.461 37.962 21.533 ;
     RECT  27.144 21.485 27.162 21.541 ;
     RECT  1.728 20.909 22.914 21.569 ;
     RECT  27.144 21.541 27.234 21.569 ;
     RECT  24.015 21.485 24.105 21.617 ;
     RECT  29.415 21.347 29.505 21.617 ;
     RECT  34.776 21.347 34.905 21.617 ;
     RECT  40.215 21.389 40.305 21.617 ;
     RECT  45.615 21.347 45.705 21.617 ;
     RECT  51.015 21.347 51.105 21.617 ;
     RECT  56.415 21.347 56.505 21.617 ;
     RECT  61.815 21.347 61.905 21.617 ;
     RECT  67.215 21.347 67.305 21.617 ;
     RECT  72.615 21.347 72.705 21.617 ;
     RECT  78.015 21.347 78.105 21.617 ;
     RECT  83.415 21.347 83.505 21.617 ;
     RECT  88.815 21.347 88.905 21.617 ;
     RECT  94.215 21.347 94.305 21.617 ;
     RECT  99.615 21.347 99.705 21.617 ;
     RECT  105.015 21.347 105.105 21.617 ;
     RECT  110.415 21.347 110.505 21.617 ;
     RECT  1.728 21.569 22.842 21.659 ;
     RECT  27.216 21.569 27.234 21.659 ;
     RECT  34.776 21.617 34.794 21.659 ;
     RECT  37.944 21.533 37.962 21.659 ;
     RECT  115.776 19.075 123.39 21.883 ;
     RECT  41.868 21.389 41.886 22.349 ;
     RECT  115.704 21.883 123.39 22.349 ;
     RECT  115.956 22.349 123.39 22.441 ;
     RECT  1.728 21.659 22.662 22.459 ;
     RECT  115.956 22.441 123.426 22.469 ;
     RECT  0.108 21.127 0.558 22.577 ;
     RECT  124.452 21.425 139.086 22.699 ;
     RECT  1.728 22.459 22.77 22.733 ;
     RECT  124.452 22.699 139.374 22.739 ;
     RECT  116.496 22.469 123.426 22.819 ;
     RECT  116.496 22.819 123.498 22.973 ;
     RECT  140.292 22.795 140.31 23.081 ;
     RECT  1.728 22.733 22.734 23.213 ;
     RECT  134.82 22.739 139.374 23.279 ;
     RECT  0.108 22.577 0.234 23.315 ;
     RECT  115.128 22.711 115.146 23.476 ;
     RECT  2.268 23.213 22.734 23.76 ;
     RECT  114.588 23.476 115.146 23.76 ;
     RECT  116.892 22.973 123.498 23.76 ;
     RECT  135.684 23.279 139.374 23.819 ;
     RECT  134.82 23.279 134.838 24.089 ;
     RECT  135.684 23.819 138.474 24.089 ;
     RECT  135.936 24.089 138.186 24.161 ;
     RECT  134.604 24.205 134.658 24.359 ;
     RECT  136.08 24.161 138.186 24.431 ;
     RECT  2.268 23.76 123.498 24.467 ;
     RECT  0.108 23.315 0.198 24.523 ;
     RECT  134.64 24.359 134.658 24.629 ;
     RECT  139.356 23.819 139.374 24.629 ;
     RECT  136.8 24.431 138.186 24.899 ;
     RECT  0.108 24.523 0.558 25.003 ;
     RECT  136.8 24.899 138.114 25.007 ;
     RECT  0.108 25.003 1.17 25.291 ;
     RECT  0.108 25.291 1.206 25.547 ;
     RECT  136.224 25.321 136.242 25.591 ;
     RECT  135.648 25.591 136.242 25.709 ;
     RECT  1.152 25.547 1.206 25.745 ;
     RECT  137.016 25.007 138.114 25.753 ;
     RECT  1.188 25.745 1.206 25.771 ;
     RECT  136.116 25.709 136.242 25.825 ;
     RECT  137.016 25.753 138.51 25.825 ;
     RECT  136.116 25.825 138.51 25.951 ;
     RECT  2.304 24.467 123.498 25.963 ;
     RECT  2.232 25.963 123.498 26.051 ;
     RECT  1.188 25.771 1.278 26.155 ;
     RECT  136.116 25.951 139.122 26.189 ;
     RECT  140.292 26.251 140.31 26.321 ;
     RECT  134.568 26.257 134.586 26.365 ;
     RECT  2.232 26.051 123.426 26.393 ;
     RECT  134.352 26.365 134.586 26.401 ;
     RECT  0.108 25.547 0.198 26.443 ;
     RECT  124.452 22.739 133.614 26.563 ;
     RECT  134.352 26.401 135.306 26.563 ;
     RECT  136.116 26.189 138.114 26.563 ;
     RECT  0.108 26.443 0.342 26.573 ;
     RECT  139.104 26.189 139.122 26.573 ;
     RECT  1.188 26.155 1.458 26.683 ;
     RECT  1.152 26.683 1.458 26.933 ;
     RECT  0.108 26.573 0.162 27.095 ;
     RECT  139.608 26.635 139.626 27.337 ;
     RECT  0.144 27.095 0.162 27.365 ;
     RECT  139.104 27.337 139.626 27.403 ;
     RECT  139.104 27.403 140.31 27.629 ;
     RECT  1.152 26.933 1.242 27.635 ;
     RECT  124.452 26.563 138.114 27.691 ;
     RECT  1.188 27.635 1.242 27.779 ;
     RECT  2.304 26.393 123.426 27.869 ;
     RECT  2.304 27.869 11.034 27.905 ;
     RECT  124.452 27.691 138.546 27.913 ;
     RECT  2.376 27.905 11.034 27.941 ;
     RECT  139.608 27.629 140.31 28.211 ;
     RECT  1.224 27.779 1.242 28.283 ;
     RECT  124.272 27.913 138.546 28.319 ;
     RECT  124.452 28.319 138.546 28.685 ;
     RECT  2.415 27.941 11.034 28.715 ;
     RECT  11.844 27.869 123.426 29.101 ;
     RECT  124.452 28.685 138.51 29.101 ;
     RECT  11.844 29.101 138.51 29.219 ;
     RECT  3.42 28.715 11.034 29.291 ;
     RECT  139.644 28.211 140.31 29.419 ;
     RECT  139.608 29.419 140.31 29.611 ;
     RECT  139.572 29.611 140.31 29.803 ;
     RECT  124.452 29.219 138.51 29.899 ;
     RECT  139.536 29.803 140.31 29.899 ;
     RECT  124.452 29.899 140.31 30.173 ;
     RECT  3.78 29.291 11.034 30.181 ;
     RECT  2.415 28.715 2.697 30.451 ;
     RECT  3.744 30.181 11.034 30.451 ;
     RECT  2.415 30.451 11.034 30.847 ;
     RECT  124.452 30.173 139.194 30.991 ;
     RECT  140.22 30.173 140.31 30.991 ;
     RECT  124.452 30.991 140.31 31.085 ;
     RECT  0.54 30.955 0.558 31.144 ;
     RECT  0.108 31.144 0.558 31.277 ;
     RECT  1.728 30.847 11.034 31.373 ;
     RECT  124.452 31.085 139.122 31.565 ;
     RECT  11.844 29.219 123.426 31.801 ;
     RECT  11.772 31.801 123.426 31.919 ;
     RECT  12.24 31.919 123.426 31.991 ;
     RECT  0.108 31.277 0.162 32.035 ;
     RECT  140.22 31.085 140.31 32.059 ;
     RECT  0.108 32.035 0.558 32.141 ;
     RECT  2.268 31.373 11.034 32.189 ;
     RECT  140.112 32.059 140.31 32.225 ;
     RECT  140.184 32.225 140.31 32.237 ;
     RECT  2.268 32.189 10.998 32.305 ;
     RECT  124.452 31.565 139.086 32.477 ;
     RECT  1.728 32.305 10.998 32.621 ;
     RECT  124.452 32.477 138.114 32.717 ;
     RECT  124.452 32.717 138.042 32.861 ;
     RECT  140.22 32.237 140.31 33.355 ;
     RECT  12.24 31.991 121.497 33.377 ;
     RECT  140.076 33.355 140.31 33.403 ;
     RECT  0.108 32.141 0.198 33.421 ;
     RECT  140.004 33.403 140.31 33.449 ;
     RECT  140.076 33.449 140.31 33.581 ;
     RECT  138.996 32.477 139.086 33.619 ;
     RECT  140.148 33.581 140.31 33.629 ;
     RECT  124.452 32.861 138.006 33.643 ;
     RECT  138.996 33.619 139.122 33.643 ;
     RECT  124.452 33.643 139.122 33.683 ;
     RECT  138.996 33.683 139.122 33.881 ;
     RECT  12.24 33.377 118.602 33.989 ;
     RECT  139.068 33.881 139.122 34.079 ;
     RECT  118.116 33.989 118.602 34.123 ;
     RECT  119.376 33.377 121.497 34.123 ;
     RECT  118.116 34.123 121.497 34.151 ;
     RECT  118.44 34.151 121.497 34.349 ;
     RECT  140.22 33.629 140.31 34.363 ;
     RECT  118.44 34.349 119.934 34.397 ;
     RECT  140.076 34.363 140.31 34.421 ;
     RECT  2.268 32.621 10.998 34.603 ;
     RECT  139.104 34.079 139.122 34.733 ;
     RECT  124.452 33.683 137.898 34.735 ;
     RECT  2.232 34.603 10.998 34.925 ;
     RECT  140.112 34.421 140.31 34.973 ;
     RECT  12.24 33.989 117.378 34.987 ;
     RECT  12.24 34.987 117.414 35.069 ;
     RECT  120.852 34.349 121.497 35.069 ;
     RECT  2.268 34.925 10.998 35.159 ;
     RECT  12.924 35.069 117.414 35.179 ;
     RECT  118.44 34.397 119.862 35.179 ;
     RECT  2.268 35.159 10.854 35.231 ;
     RECT  12.924 35.179 119.862 35.323 ;
     RECT  11.736 35.323 11.754 35.429 ;
     RECT  124.452 34.735 137.934 35.563 ;
     RECT  124.452 35.563 138.51 35.671 ;
     RECT  12.924 35.323 119.97 35.771 ;
     RECT  124.452 35.671 139.122 35.789 ;
     RECT  10.836 35.231 10.854 35.899 ;
     RECT  122.364 31.991 123.426 35.969 ;
     RECT  119.448 35.771 119.97 36.029 ;
     RECT  140.22 34.973 140.31 36.043 ;
     RECT  119.484 36.029 119.97 36.049 ;
     RECT  2.268 35.231 9.882 36.077 ;
     RECT  12.924 35.771 118.71 36.077 ;
     RECT  123.372 35.969 123.426 36.077 ;
     RECT  119.484 36.049 120.186 36.149 ;
     RECT  139.104 35.789 139.122 36.173 ;
     RECT  10.836 35.899 11.43 36.239 ;
     RECT  124.452 35.789 137.97 36.239 ;
     RECT  140.112 36.043 140.31 36.269 ;
     RECT  119.484 36.149 119.862 36.383 ;
     RECT  0.108 33.421 0.558 36.427 ;
     RECT  1.332 36.043 1.35 36.427 ;
     RECT  2.304 36.077 9.882 36.472 ;
     RECT  10.836 36.239 10.89 36.472 ;
     RECT  12.924 36.077 118.674 36.472 ;
     RECT  11.664 36.472 11.682 36.509 ;
     RECT  119.484 36.383 119.754 36.509 ;
     RECT  124.524 36.239 137.97 36.523 ;
     RECT  12.528 36.472 118.674 36.625 ;
     RECT  0.108 36.427 1.35 36.653 ;
     RECT  124.524 36.523 139.086 36.653 ;
     RECT  12.384 36.625 118.674 36.689 ;
     RECT  123.408 36.077 123.426 36.779 ;
     RECT  118.584 36.689 118.674 37.021 ;
     RECT  119.484 36.509 119.682 37.021 ;
     RECT  1.152 36.653 1.35 37.085 ;
     RECT  139.032 36.653 139.086 37.195 ;
     RECT  140.22 36.269 140.31 37.195 ;
     RECT  118.584 37.021 119.682 37.229 ;
     RECT  2.304 36.472 10.89 37.355 ;
     RECT  1.188 37.085 1.35 37.427 ;
     RECT  124.524 36.653 137.862 37.471 ;
     RECT  139.032 37.195 140.31 37.517 ;
     RECT  124.524 37.471 137.898 37.579 ;
     RECT  0.108 36.653 0.162 37.625 ;
     RECT  2.376 37.355 10.89 37.625 ;
     RECT  1.188 37.427 1.242 37.769 ;
     RECT  0.108 37.625 0.126 37.895 ;
     RECT  139.068 37.517 140.31 37.931 ;
     RECT  2.415 37.625 10.89 38.129 ;
     RECT  139.536 37.931 140.31 38.129 ;
     RECT  1.224 37.769 1.242 38.165 ;
     RECT  7.128 38.129 10.89 38.201 ;
     RECT  124.524 37.579 138.006 38.245 ;
     RECT  118.584 37.229 119.106 38.281 ;
     RECT  118.584 38.281 119.754 38.285 ;
     RECT  8.82 38.201 10.89 38.309 ;
     RECT  2.415 38.129 6.282 38.435 ;
     RECT  124.524 38.245 138.042 38.749 ;
     RECT  119.628 38.285 119.754 38.813 ;
     RECT  124.524 38.749 138.438 38.821 ;
     RECT  118.584 38.285 118.674 38.861 ;
     RECT  10.872 38.309 10.89 39.047 ;
     RECT  139.536 38.129 140.274 39.211 ;
     RECT  119.628 38.813 119.646 39.217 ;
     RECT  124.524 38.821 138.51 39.217 ;
     RECT  139.536 39.211 140.31 39.217 ;
     RECT  119.556 39.217 119.646 39.253 ;
     RECT  124.524 39.217 140.31 39.341 ;
     RECT  3.528 38.435 6.282 39.355 ;
     RECT  3.456 39.355 6.282 39.361 ;
     RECT  3.42 39.361 6.282 39.479 ;
     RECT  12.384 36.689 117.414 39.479 ;
     RECT  119.088 39.253 119.646 39.595 ;
     RECT  124.524 39.341 138.51 39.629 ;
     RECT  3.42 39.479 3.762 39.749 ;
     RECT  8.82 38.309 9.702 39.749 ;
     RECT  119.088 39.595 119.754 39.749 ;
     RECT  3.42 39.749 3.438 39.893 ;
     RECT  4.536 39.479 4.554 39.893 ;
     RECT  119.844 39.793 119.862 39.893 ;
     RECT  119.088 39.749 119.106 39.917 ;
     RECT  139.608 39.341 140.31 39.929 ;
     RECT  121.215 35.069 121.497 40.075 ;
     RECT  121.215 40.075 121.59 40.301 ;
     RECT  139.068 40.075 139.086 40.631 ;
     RECT  124.524 39.629 138.006 40.651 ;
     RECT  119.592 40.567 119.61 40.703 ;
     RECT  124.524 40.651 138.438 40.739 ;
     RECT  140.076 39.929 140.31 40.747 ;
     RECT  139.608 40.747 140.31 41.171 ;
     RECT  118.62 39.991 118.638 41.207 ;
     RECT  119.844 40.873 119.862 41.341 ;
     RECT  124.56 40.739 138.438 41.611 ;
     RECT  119.088 41.413 119.106 41.645 ;
     RECT  119.844 41.341 119.898 41.647 ;
     RECT  12.924 39.479 117.414 41.909 ;
     RECT  14.58 41.909 117.414 41.933 ;
     RECT  12.924 41.909 13.842 42.053 ;
     RECT  119.52 41.647 119.898 42.187 ;
     RECT  119.52 42.187 120.078 42.215 ;
     RECT  124.56 41.611 139.086 42.259 ;
     RECT  124.56 42.259 139.122 42.413 ;
     RECT  119.556 42.215 120.078 42.449 ;
     RECT  140.112 41.171 140.31 42.449 ;
     RECT  124.56 42.413 138.582 42.521 ;
     RECT  119.556 42.449 120.042 42.755 ;
     RECT  140.112 42.449 140.274 42.763 ;
     RECT  119.556 42.755 119.898 42.899 ;
     RECT  14.58 41.933 117.378 43.141 ;
     RECT  124.56 42.521 138.006 43.169 ;
     RECT  124.632 43.169 138.006 43.259 ;
     RECT  140.076 42.763 140.274 43.339 ;
     RECT  14.58 43.141 117.414 43.411 ;
     RECT  139.68 43.339 140.274 43.411 ;
     RECT  124.632 43.259 137.862 43.529 ;
     RECT  139.644 43.411 140.31 43.531 ;
     RECT  14.256 43.411 117.414 43.627 ;
     RECT  118.584 43.531 118.602 43.627 ;
     RECT  119.592 42.899 119.898 43.627 ;
     RECT  14.256 43.627 118.602 43.673 ;
     RECT  118.584 43.673 118.602 43.771 ;
     RECT  119.592 43.627 119.934 43.771 ;
     RECT  121.215 40.301 121.497 43.771 ;
     RECT  121.104 43.771 121.497 43.808 ;
     RECT  118.584 43.771 119.97 43.871 ;
     RECT  12.924 42.053 13.497 43.951 ;
     RECT  14.256 43.673 117.594 43.951 ;
     RECT  118.584 43.871 119.754 44.045 ;
     RECT  124.956 43.529 137.862 44.221 ;
     RECT  119.592 44.045 119.754 44.375 ;
     RECT  12.924 43.951 117.594 44.419 ;
     RECT  118.584 44.045 118.674 44.419 ;
     RECT  122.364 35.969 122.382 44.443 ;
     RECT  12.924 44.419 118.674 44.447 ;
     RECT  124.956 44.221 138.042 44.491 ;
     RECT  12.924 44.447 118.638 44.525 ;
     RECT  122.364 44.443 122.562 44.573 ;
     RECT  118.62 44.525 118.638 44.717 ;
     RECT  124.956 44.491 138.51 44.717 ;
     RECT  119.736 44.375 119.754 44.789 ;
     RECT  139.608 43.531 140.31 44.875 ;
     RECT  12.924 44.525 117.414 45.005 ;
     RECT  139.572 44.875 140.31 45.059 ;
     RECT  119.808 45.031 119.826 45.149 ;
     RECT  140.04 45.059 140.31 45.197 ;
     RECT  121.215 43.808 121.497 45.391 ;
     RECT  122.364 44.573 122.382 45.403 ;
     RECT  14.76 45.005 117.414 45.455 ;
     RECT  140.112 45.197 140.31 45.485 ;
     RECT  140.148 45.485 140.31 45.491 ;
     RECT  118.62 45.463 118.638 45.563 ;
     RECT  12.924 45.005 13.986 45.841 ;
     RECT  14.76 45.455 17.478 45.841 ;
     RECT  119.88 45.661 119.898 45.869 ;
     RECT  139.068 45.643 139.122 45.869 ;
     RECT  121.104 45.391 121.497 45.931 ;
     RECT  139.068 45.869 139.086 46.103 ;
     RECT  122.364 45.403 122.562 46.109 ;
     RECT  12.924 45.841 17.478 46.139 ;
     RECT  124.956 44.717 138.042 46.219 ;
     RECT  140.22 45.491 140.31 46.315 ;
     RECT  124.956 46.219 138.51 46.349 ;
     RECT  14.256 46.139 17.478 46.381 ;
     RECT  18.216 45.455 117.414 46.381 ;
     RECT  119.628 46.201 119.79 46.409 ;
     RECT  119.772 46.409 119.79 46.499 ;
     RECT  14.256 46.381 117.414 46.535 ;
     RECT  118.836 46.471 118.854 46.543 ;
     RECT  14.616 46.535 117.414 46.699 ;
     RECT  118.62 46.543 118.854 46.699 ;
     RECT  122.364 46.109 122.382 46.885 ;
     RECT  140.184 46.315 140.31 46.891 ;
     RECT  120.528 45.931 121.497 46.921 ;
     RECT  12.924 46.139 13.497 47.011 ;
     RECT  5.4 39.479 6.282 47.039 ;
     RECT  122.364 46.885 122.598 47.039 ;
     RECT  122.364 47.039 122.562 47.165 ;
     RECT  139.5 46.891 140.31 47.213 ;
     RECT  14.616 46.699 118.854 47.219 ;
     RECT  118.836 47.219 118.854 47.236 ;
     RECT  119.844 46.921 121.497 47.236 ;
     RECT  12.924 47.011 13.77 47.272 ;
     RECT  14.616 47.219 117.99 47.272 ;
     RECT  12.924 47.272 117.99 47.309 ;
     RECT  118.836 47.236 121.497 47.309 ;
     RECT  124.956 46.349 138.042 47.309 ;
     RECT  118.836 47.309 119.718 47.453 ;
     RECT  124.956 47.309 138.006 47.453 ;
     RECT  124.128 46.921 124.218 47.489 ;
     RECT  139.572 47.213 140.31 47.849 ;
     RECT  140.112 47.849 140.31 47.885 ;
     RECT  139.104 47.965 139.122 48.077 ;
     RECT  14.508 47.309 117.99 48.127 ;
     RECT  118.836 47.453 118.854 48.127 ;
     RECT  5.4 47.039 5.418 48.191 ;
     RECT  119.7 47.453 119.718 48.199 ;
     RECT  120.528 47.309 121.497 48.199 ;
     RECT  12.924 47.309 13.77 48.235 ;
     RECT  14.508 48.127 118.854 48.235 ;
     RECT  12.924 48.235 118.854 48.299 ;
     RECT  14.688 48.299 118.854 48.344 ;
     RECT  119.7 48.199 121.497 48.389 ;
     RECT  118.836 48.344 118.854 48.397 ;
     RECT  119.7 48.389 119.754 48.397 ;
     RECT  139.068 48.127 139.086 48.523 ;
     RECT  118.836 48.397 119.754 48.533 ;
     RECT  139.032 48.523 139.086 48.541 ;
     RECT  7.128 38.201 8.097 48.731 ;
     RECT  10.836 48.469 10.854 48.731 ;
     RECT  138.996 48.541 139.086 48.845 ;
     RECT  140.292 47.885 140.31 48.907 ;
     RECT  124.956 47.453 137.97 48.929 ;
     RECT  140.256 48.907 140.31 49.003 ;
     RECT  139.032 48.845 139.086 49.037 ;
     RECT  140.22 49.003 140.31 49.099 ;
     RECT  14.688 48.344 117.99 49.207 ;
     RECT  118.836 48.533 118.854 49.207 ;
     RECT  119.736 48.533 119.754 49.279 ;
     RECT  139.068 49.037 139.086 49.291 ;
     RECT  140.184 49.099 140.31 49.291 ;
     RECT  139.068 49.291 140.31 49.421 ;
     RECT  4.536 49.351 4.698 49.435 ;
     RECT  5.472 49.351 5.49 49.435 ;
     RECT  4.536 49.435 5.49 49.441 ;
     RECT  119.736 49.279 119.79 49.441 ;
     RECT  4.176 49.441 5.526 49.477 ;
     RECT  7.815 48.731 8.097 49.549 ;
     RECT  8.82 39.749 9.414 49.549 ;
     RECT  119.628 49.441 119.79 49.613 ;
     RECT  2.415 38.435 2.697 49.621 ;
     RECT  4.032 49.477 5.526 49.621 ;
     RECT  6.264 47.039 6.282 49.621 ;
     RECT  124.956 48.929 137.898 49.675 ;
     RECT  139.068 49.421 140.274 49.739 ;
     RECT  2.415 49.621 3.078 49.819 ;
     RECT  14.688 49.207 118.854 49.883 ;
     RECT  2.232 49.819 3.078 49.891 ;
     RECT  4.032 49.621 6.282 49.891 ;
     RECT  139.068 49.739 140.238 49.963 ;
     RECT  120.528 48.389 121.497 49.981 ;
     RECT  119.88 49.981 121.497 50.117 ;
     RECT  2.232 49.891 6.858 50.155 ;
     RECT  14.688 49.883 117.99 50.189 ;
     RECT  2.232 50.155 6.894 50.251 ;
     RECT  7.815 49.549 9.414 50.251 ;
     RECT  2.232 50.251 9.414 50.287 ;
     RECT  0.18 50.017 0.198 50.443 ;
     RECT  12.924 48.299 13.77 50.521 ;
     RECT  14.688 50.189 117.414 50.521 ;
     RECT  0.108 50.443 0.198 50.539 ;
     RECT  139.032 49.963 140.238 50.539 ;
     RECT  1.8 50.287 9.414 50.861 ;
     RECT  119.736 50.431 119.79 50.863 ;
     RECT  120.528 50.117 121.497 50.863 ;
     RECT  12.924 50.521 117.414 50.971 ;
     RECT  119.736 50.863 121.497 50.971 ;
     RECT  10.332 50.971 10.35 51.061 ;
     RECT  118.836 49.883 118.854 51.061 ;
     RECT  119.628 50.971 121.497 51.089 ;
     RECT  12.6 50.971 117.414 51.133 ;
     RECT  10.26 51.061 10.35 51.241 ;
     RECT  12.384 51.133 117.414 51.269 ;
     RECT  124.956 49.675 138.222 51.307 ;
     RECT  139.032 50.539 140.31 51.307 ;
     RECT  2.304 50.861 9.414 51.367 ;
     RECT  11.196 51.331 11.214 51.367 ;
     RECT  10.188 51.241 10.35 51.395 ;
     RECT  11.196 51.367 11.286 51.403 ;
     RECT  2.304 51.367 9.45 51.439 ;
     RECT  10.8 51.403 11.286 51.467 ;
     RECT  118.62 51.061 118.854 51.467 ;
     RECT  10.8 51.467 11.214 51.539 ;
     RECT  12.888 51.269 117.414 51.701 ;
     RECT  0.108 50.539 0.558 51.737 ;
     RECT  119.736 51.089 121.497 51.737 ;
     RECT  124.956 51.307 140.31 51.773 ;
     RECT  0.108 51.737 0.198 51.821 ;
     RECT  139.032 51.773 140.31 51.899 ;
     RECT  119.736 51.737 119.754 52.007 ;
     RECT  139.032 51.899 140.274 52.169 ;
     RECT  11.988 51.511 12.006 52.171 ;
     RECT  12.888 51.701 13.77 52.171 ;
     RECT  139.032 52.169 139.698 52.241 ;
     RECT  2.304 51.439 10.062 52.249 ;
     RECT  10.836 51.539 11.214 52.249 ;
     RECT  11.988 52.171 13.77 52.249 ;
     RECT  2.268 52.249 10.062 52.267 ;
     RECT  10.836 52.249 13.77 52.267 ;
     RECT  124.956 51.773 138.222 52.277 ;
     RECT  124.956 52.277 134.694 52.349 ;
     RECT  14.616 51.701 117.414 52.363 ;
     RECT  2.268 52.267 13.77 52.439 ;
     RECT  124.956 52.349 134.622 52.439 ;
     RECT  2.268 52.439 12.078 52.619 ;
     RECT  14.616 52.363 118.026 52.636 ;
     RECT  118.836 51.467 118.854 52.636 ;
     RECT  0.108 51.821 0.126 52.651 ;
     RECT  135.576 52.277 138.222 52.709 ;
     RECT  14.616 52.636 118.854 52.781 ;
     RECT  12.924 52.439 13.77 52.789 ;
     RECT  14.616 52.781 117.99 52.789 ;
     RECT  139.032 52.241 139.662 52.817 ;
     RECT  11.412 52.619 12.078 52.889 ;
     RECT  118.836 52.781 118.854 52.951 ;
     RECT  119.7 52.717 119.718 52.951 ;
     RECT  135.648 52.709 138.222 52.979 ;
     RECT  139.032 52.817 139.05 52.979 ;
     RECT  2.268 52.619 10.566 52.987 ;
     RECT  12.924 52.789 117.99 53.015 ;
     RECT  124.956 52.439 134.55 53.015 ;
     RECT  118.836 52.951 119.718 53.221 ;
     RECT  120.528 51.737 121.497 53.221 ;
     RECT  136.692 52.979 138.222 53.249 ;
     RECT  134.532 53.015 134.55 53.285 ;
     RECT  136.692 53.249 138.006 53.321 ;
     RECT  0.108 52.651 0.558 53.357 ;
     RECT  1.728 52.987 10.566 53.357 ;
     RECT  118.836 53.221 121.497 53.357 ;
     RECT  12.06 52.889 12.078 53.365 ;
     RECT  12.924 53.015 13.77 53.365 ;
     RECT  2.304 53.357 10.566 53.401 ;
     RECT  118.836 53.357 119.79 53.429 ;
     RECT  135.756 52.979 135.774 53.519 ;
     RECT  136.692 53.321 137.97 53.519 ;
     RECT  12.06 53.365 13.77 53.555 ;
     RECT  137.304 53.519 137.97 53.591 ;
     RECT  118.836 53.429 119.646 53.627 ;
     RECT  2.304 53.401 11.178 53.761 ;
     RECT  137.304 53.591 137.826 53.789 ;
     RECT  137.304 53.789 137.697 53.825 ;
     RECT  12.492 53.555 13.77 53.905 ;
     RECT  14.616 53.015 117.99 53.905 ;
     RECT  12.492 53.905 117.99 54.059 ;
     RECT  0.108 53.357 0.162 54.187 ;
     RECT  12.528 54.059 117.99 54.221 ;
     RECT  0.108 54.187 0.378 54.373 ;
     RECT  119.628 53.627 119.646 54.373 ;
     RECT  2.304 53.761 11.682 54.473 ;
     RECT  118.836 53.627 118.854 54.481 ;
     RECT  119.628 54.373 119.754 54.481 ;
     RECT  0.108 54.373 0.558 54.605 ;
     RECT  119.592 54.481 119.754 54.635 ;
     RECT  12.528 54.221 117.45 54.671 ;
     RECT  2.304 54.473 9.666 54.679 ;
     RECT  12.636 54.671 117.45 54.701 ;
     RECT  14.688 54.701 117.45 54.743 ;
     RECT  0.108 54.605 0.342 54.797 ;
     RECT  119.736 54.635 119.754 54.841 ;
     RECT  1.728 54.679 9.666 54.893 ;
     RECT  119.736 54.841 119.79 55.049 ;
     RECT  12.636 54.701 13.95 55.211 ;
     RECT  14.76 54.743 117.45 55.219 ;
     RECT  118.584 54.481 118.854 55.219 ;
     RECT  119.736 55.049 119.754 55.247 ;
     RECT  2.196 54.893 9.666 55.285 ;
     RECT  10.548 54.473 10.998 55.285 ;
     RECT  2.196 55.285 10.998 55.381 ;
     RECT  0.144 54.797 0.342 55.469 ;
     RECT  2.196 55.381 11.682 55.561 ;
     RECT  13.032 55.211 13.95 55.651 ;
     RECT  13.032 55.651 13.986 55.859 ;
     RECT  0.144 55.469 0.162 55.915 ;
     RECT  13.032 55.859 13.95 55.957 ;
     RECT  2.196 55.561 12.078 55.985 ;
     RECT  120.528 53.357 121.497 56.065 ;
     RECT  11.34 55.985 12.078 56.101 ;
     RECT  12.852 55.957 13.95 56.101 ;
     RECT  119.952 56.065 121.497 56.101 ;
     RECT  11.34 56.101 13.95 56.219 ;
     RECT  0.108 55.915 0.162 56.255 ;
     RECT  2.196 55.985 10.278 56.363 ;
     RECT  119.844 56.101 121.497 56.461 ;
     RECT  119.628 56.461 121.497 56.561 ;
     RECT  13.032 56.219 13.95 56.839 ;
     RECT  14.76 55.219 118.854 56.839 ;
     RECT  0.54 56.683 0.558 56.875 ;
     RECT  1.296 56.779 1.314 56.875 ;
     RECT  0.54 56.875 1.314 56.903 ;
     RECT  2.304 56.363 10.278 57.073 ;
     RECT  11.34 56.219 12.114 57.073 ;
     RECT  13.032 56.839 118.854 57.299 ;
     RECT  2.304 57.073 12.114 57.307 ;
     RECT  13.032 57.299 117.99 57.307 ;
     RECT  120.096 56.561 121.497 57.307 ;
     RECT  2.304 57.307 117.99 57.407 ;
     RECT  118.836 57.299 118.854 57.496 ;
     RECT  119.592 57.307 121.497 57.496 ;
     RECT  2.304 57.407 11.682 57.569 ;
     RECT  118.836 57.496 121.497 57.569 ;
     RECT  1.152 56.903 1.314 57.605 ;
     RECT  1.296 57.605 1.314 57.677 ;
     RECT  0.108 57.067 0.234 57.739 ;
     RECT  12.42 57.407 117.99 57.839 ;
     RECT  0.108 57.739 0.342 57.869 ;
     RECT  118.836 57.569 119.538 58.253 ;
     RECT  2.304 57.569 11.574 58.379 ;
     RECT  11.304 58.379 11.574 58.387 ;
     RECT  12.42 57.839 13.95 58.387 ;
     RECT  14.688 57.839 117.99 58.387 ;
     RECT  118.836 58.253 118.854 58.387 ;
     RECT  2.304 58.379 10.566 58.415 ;
     RECT  14.688 58.387 118.854 58.523 ;
     RECT  11.304 58.387 13.95 58.559 ;
     RECT  12.636 58.559 13.95 58.729 ;
     RECT  14.688 58.523 117.99 58.729 ;
     RECT  0.108 57.869 0.234 58.891 ;
     RECT  120.528 57.569 121.497 58.963 ;
     RECT  0.108 58.891 0.306 58.991 ;
     RECT  2.304 58.415 10.386 59.161 ;
     RECT  11.304 58.559 11.79 59.161 ;
     RECT  118.836 58.523 118.854 59.197 ;
     RECT  119.736 58.657 119.754 59.197 ;
     RECT  2.304 59.161 11.79 59.305 ;
     RECT  12.636 58.729 117.99 59.305 ;
     RECT  118.836 59.197 119.754 59.333 ;
     RECT  2.304 59.305 117.99 59.503 ;
     RECT  118.836 59.333 118.854 59.503 ;
     RECT  119.628 59.333 119.754 59.611 ;
     RECT  120.528 58.963 121.626 59.611 ;
     RECT  119.628 59.611 121.626 59.729 ;
     RECT  119.988 59.729 121.626 59.837 ;
     RECT  0.108 58.991 0.198 59.851 ;
     RECT  2.304 59.503 118.854 59.885 ;
     RECT  118.584 59.885 118.854 60.179 ;
     RECT  0.108 59.851 0.558 60.377 ;
     RECT  2.304 59.885 117.414 60.377 ;
     RECT  2.304 60.377 11.61 60.611 ;
     RECT  12.564 60.377 117.414 60.619 ;
     RECT  120.528 59.837 121.626 60.817 ;
     RECT  0.108 60.377 0.342 60.845 ;
     RECT  2.304 60.611 10.782 60.989 ;
     RECT  0.144 60.845 0.342 61.099 ;
     RECT  2.304 60.989 9.846 61.151 ;
     RECT  11.592 60.611 11.61 61.159 ;
     RECT  12.564 60.619 117.45 61.159 ;
     RECT  119.844 60.817 121.626 61.259 ;
     RECT  10.584 60.989 10.782 61.393 ;
     RECT  11.592 61.159 117.45 61.393 ;
     RECT  118.836 60.179 118.854 61.393 ;
     RECT  0.144 61.099 0.558 61.457 ;
     RECT  10.584 61.393 117.45 61.483 ;
     RECT  118.584 61.393 118.854 61.483 ;
     RECT  0.144 61.457 0.342 61.579 ;
     RECT  0.108 61.579 0.342 61.727 ;
     RECT  119.592 61.627 119.61 61.763 ;
     RECT  1.152 61.483 1.17 61.771 ;
     RECT  9.072 61.151 9.846 61.771 ;
     RECT  10.584 61.483 118.854 61.771 ;
     RECT  1.152 61.771 1.206 61.915 ;
     RECT  0.324 61.727 0.342 62.093 ;
     RECT  120.528 61.259 121.626 62.203 ;
     RECT  2.304 61.151 8.298 62.465 ;
     RECT  9.072 61.771 118.854 62.465 ;
     RECT  119.7 62.203 121.626 62.465 ;
     RECT  2.34 62.465 8.298 62.509 ;
     RECT  9.072 62.465 9.846 62.509 ;
     RECT  119.736 62.465 121.626 62.699 ;
     RECT  2.34 62.509 9.846 62.735 ;
     RECT  2.376 62.735 9.846 62.771 ;
     RECT  7.815 62.771 9.846 62.807 ;
     RECT  7.815 62.807 8.586 62.843 ;
     RECT  10.728 62.465 118.854 62.861 ;
     RECT  10.728 62.861 117.414 62.969 ;
     RECT  1.152 61.915 1.242 63.005 ;
     RECT  7.815 62.843 8.478 63.053 ;
     RECT  1.152 63.005 1.206 63.149 ;
     RECT  118.584 62.861 118.854 63.149 ;
     RECT  9.576 62.807 9.846 63.239 ;
     RECT  12.276 62.969 117.414 63.239 ;
     RECT  12.348 63.239 117.414 63.245 ;
     RECT  9.828 63.239 9.846 63.247 ;
     RECT  118.836 63.149 118.854 63.247 ;
     RECT  2.376 62.771 6.786 63.275 ;
     RECT  10.728 62.969 11.394 63.275 ;
     RECT  12.348 63.245 13.497 63.275 ;
     RECT  9.828 63.247 9.918 63.341 ;
     RECT  118.836 63.247 119.646 63.341 ;
     RECT  10.728 63.275 11.358 63.347 ;
     RECT  118.836 63.341 119.574 63.383 ;
     RECT  1.152 63.149 1.17 63.545 ;
     RECT  2.415 63.275 6.246 63.545 ;
     RECT  13.032 63.275 13.497 63.581 ;
     RECT  14.688 63.245 117.414 63.595 ;
     RECT  14.688 63.595 117.45 63.653 ;
     RECT  9.9 63.341 9.918 63.779 ;
     RECT  14.688 63.653 117.378 63.779 ;
     RECT  3.924 63.545 6.246 63.815 ;
     RECT  3.924 63.815 4.086 64.049 ;
     RECT  4.86 63.815 6.246 64.049 ;
     RECT  3.924 64.049 3.978 64.061 ;
     RECT  3.924 64.061 3.942 64.085 ;
     RECT  4.932 64.049 5.022 64.085 ;
     RECT  5.76 64.049 6.246 64.085 ;
     RECT  5.832 64.085 6.246 64.157 ;
     RECT  5.832 64.157 6.21 64.319 ;
     RECT  4.932 64.085 4.95 64.355 ;
     RECT  5.94 64.319 5.958 64.355 ;
     RECT  14.688 63.779 117.288 64.669 ;
     RECT  14.688 64.669 117.414 64.824 ;
     RECT  118.836 63.383 118.854 65.165 ;
     RECT  117.324 64.824 117.414 65.357 ;
     RECT  117.324 65.357 117.342 65.399 ;
     RECT  120.528 62.699 121.626 65.551 ;
     RECT  122.364 47.165 122.382 65.551 ;
     RECT  118.656 65.551 118.674 65.641 ;
     RECT  118.584 65.641 118.674 65.669 ;
     RECT  118.584 65.669 118.602 65.939 ;
     RECT  120.528 65.551 122.382 65.939 ;
     RECT  14.688 64.824 22.482 66.221 ;
     RECT  15.012 66.221 22.482 66.253 ;
     RECT  15.012 66.253 22.518 66.317 ;
     RECT  15.012 66.317 16.974 66.365 ;
     RECT  120.528 65.939 121.626 66.389 ;
     RECT  18.036 66.317 22.518 66.451 ;
     RECT  120.6 66.389 121.626 66.479 ;
     RECT  45.252 64.824 45.27 66.523 ;
     RECT  46.152 66.487 46.17 66.523 ;
     RECT  124.128 47.489 124.146 66.551 ;
     RECT  39.888 64.824 39.906 66.631 ;
     RECT  122.364 65.939 122.382 66.715 ;
     RECT  15.012 66.365 16.758 66.749 ;
     RECT  18.036 66.451 22.59 66.785 ;
     RECT  40.788 66.631 40.806 66.811 ;
     RECT  41.832 65.821 42.534 66.811 ;
     RECT  118.584 66.715 118.602 66.845 ;
     RECT  122.364 66.715 122.562 66.845 ;
     RECT  15.984 66.749 16.758 66.857 ;
     RECT  38.844 66.811 38.862 66.859 ;
     RECT  39.888 66.631 39.942 66.943 ;
     RECT  40.788 66.811 42.534 66.943 ;
     RECT  67.824 64.824 67.842 66.943 ;
     RECT  13.215 63.581 13.497 66.991 ;
     RECT  24.015 66.943 24.105 66.991 ;
     RECT  38.772 66.859 38.862 66.991 ;
     RECT  39.888 66.943 42.534 67.019 ;
     RECT  45.252 66.523 46.17 67.019 ;
     RECT  47.52 66.907 47.538 67.019 ;
     RECT  13.104 66.991 13.497 67.037 ;
     RECT  38.772 66.991 39.042 67.085 ;
     RECT  69.876 66.991 69.894 67.085 ;
     RECT  39.888 67.019 41.382 67.091 ;
     RECT  23.904 66.991 24.21 67.099 ;
     RECT  38.772 67.085 38.898 67.133 ;
     RECT  45.252 67.019 45.99 67.135 ;
     RECT  67.215 66.943 67.842 67.135 ;
     RECT  103.752 66.907 103.77 67.135 ;
     RECT  15.012 66.749 15.21 67.163 ;
     RECT  38.808 67.133 38.898 67.163 ;
     RECT  44.784 67.135 45.99 67.181 ;
     RECT  38.808 67.163 38.826 67.199 ;
     RECT  23.652 67.099 24.21 67.213 ;
     RECT  29.415 66.943 29.505 67.213 ;
     RECT  34.815 66.943 34.905 67.213 ;
     RECT  51.015 66.943 51.105 67.213 ;
     RECT  56.415 66.943 56.505 67.213 ;
     RECT  61.815 66.943 61.905 67.213 ;
     RECT  72.615 66.943 72.705 67.213 ;
     RECT  78.015 66.943 78.105 67.213 ;
     RECT  83.415 66.943 83.505 67.213 ;
     RECT  88.815 66.943 88.905 67.213 ;
     RECT  94.215 66.943 94.305 67.213 ;
     RECT  99.615 66.943 99.705 67.213 ;
     RECT  105.015 66.943 105.105 67.213 ;
     RECT  110.415 66.943 110.505 67.213 ;
     RECT  115.815 66.943 115.905 67.213 ;
     RECT  23.652 67.213 24.297 67.243 ;
     RECT  67.215 67.135 68.346 67.243 ;
     RECT  26.208 67.051 26.226 67.261 ;
     RECT  33.588 66.991 33.606 67.261 ;
     RECT  40.215 67.091 41.382 67.277 ;
     RECT  47.232 67.171 47.25 67.277 ;
     RECT  103.428 67.135 103.77 67.277 ;
     RECT  67.215 67.243 68.814 67.289 ;
     RECT  103.752 67.277 103.77 67.289 ;
     RECT  33.552 67.261 33.606 67.297 ;
     RECT  56.415 67.213 56.697 67.297 ;
     RECT  61.815 67.213 62.097 67.297 ;
     RECT  67.215 67.289 68.526 67.297 ;
     RECT  78.015 67.213 78.297 67.297 ;
     RECT  88.815 67.213 89.097 67.297 ;
     RECT  99.615 67.213 99.897 67.297 ;
     RECT  110.415 67.213 110.697 67.297 ;
     RECT  18.615 66.785 22.59 67.333 ;
     RECT  23.328 67.243 24.297 67.333 ;
     RECT  18.615 67.333 24.297 67.339 ;
     RECT  25.056 67.243 25.47 67.339 ;
     RECT  54.72 67.297 54.738 67.369 ;
     RECT  61.815 67.297 62.73 67.369 ;
     RECT  66.816 67.297 68.526 67.369 ;
     RECT  74.664 67.297 74.682 67.369 ;
     RECT  86.652 67.297 86.67 67.369 ;
     RECT  98.604 67.297 98.622 67.369 ;
     RECT  106.596 67.297 106.614 67.369 ;
     RECT  66.744 67.369 68.526 67.373 ;
     RECT  18.615 67.339 25.47 67.387 ;
     RECT  26.208 67.261 26.514 67.387 ;
     RECT  54.72 67.369 54.81 67.397 ;
     RECT  74.664 67.369 74.754 67.397 ;
     RECT  86.652 67.369 86.742 67.397 ;
     RECT  98.604 67.369 98.694 67.397 ;
     RECT  106.596 67.369 106.686 67.397 ;
     RECT  56.415 67.297 56.754 67.432 ;
     RECT  78.015 67.297 78.354 67.432 ;
     RECT  88.815 67.297 89.154 67.432 ;
     RECT  99.615 67.297 99.954 67.432 ;
     RECT  110.415 67.297 110.79 67.432 ;
     RECT  15.984 66.857 16.074 67.433 ;
     RECT  16.056 67.433 16.074 67.469 ;
     RECT  54.792 67.397 54.81 67.469 ;
     RECT  61.815 67.369 62.802 67.469 ;
     RECT  74.736 67.397 74.754 67.469 ;
     RECT  86.724 67.397 86.742 67.469 ;
     RECT  98.676 67.397 98.694 67.469 ;
     RECT  106.668 67.397 106.686 67.469 ;
     RECT  114.588 67.339 114.606 67.469 ;
     RECT  34.815 67.213 35.097 67.525 ;
     RECT  18.615 67.387 26.802 67.531 ;
     RECT  27.612 67.243 27.63 67.531 ;
     RECT  101.052 67.051 101.07 67.531 ;
     RECT  121.215 66.479 121.626 67.531 ;
     RECT  16.812 67.243 16.83 67.559 ;
     RECT  17.604 67.243 17.622 67.559 ;
     RECT  33.228 67.297 33.606 67.559 ;
     RECT  102.6 67.525 102.618 67.565 ;
     RECT  18.615 67.531 27.63 67.568 ;
     RECT  121.104 67.531 121.626 67.568 ;
     RECT  66.744 67.373 67.95 67.579 ;
     RECT  33.228 67.559 33.246 67.595 ;
     RECT  101.052 67.531 101.214 67.595 ;
     RECT  18.615 67.568 27.162 67.661 ;
     RECT  30.672 67.531 30.69 67.661 ;
     RECT  28.512 67.627 28.53 67.675 ;
     RECT  29.415 67.213 29.697 67.675 ;
     RECT  66.708 67.579 67.95 67.709 ;
     RECT  28.008 67.675 29.697 67.711 ;
     RECT  34.704 67.525 35.097 67.711 ;
     RECT  51.015 67.213 51.297 67.711 ;
     RECT  56.304 67.432 56.754 67.711 ;
     RECT  72.615 67.213 72.897 67.711 ;
     RECT  77.904 67.432 78.354 67.711 ;
     RECT  83.415 67.213 83.697 67.711 ;
     RECT  88.704 67.432 89.154 67.711 ;
     RECT  94.215 67.213 94.497 67.711 ;
     RECT  99.504 67.432 99.954 67.711 ;
     RECT  105.015 67.213 105.297 67.711 ;
     RECT  115.815 67.213 116.097 67.711 ;
     RECT  28.008 67.711 29.79 67.739 ;
     RECT  29.124 67.739 29.79 67.757 ;
     RECT  34.704 67.711 35.19 67.757 ;
     RECT  40.215 67.277 40.59 67.757 ;
     RECT  45.252 67.181 45.99 67.757 ;
     RECT  51.015 67.711 51.39 67.757 ;
     RECT  56.304 67.711 56.79 67.757 ;
     RECT  61.815 67.469 62.19 67.757 ;
     RECT  67.104 67.709 67.59 67.757 ;
     RECT  72.615 67.711 72.99 67.757 ;
     RECT  77.904 67.711 78.39 67.757 ;
     RECT  83.415 67.711 83.79 67.757 ;
     RECT  88.704 67.711 89.19 67.757 ;
     RECT  94.215 67.711 94.59 67.757 ;
     RECT  99.504 67.711 99.99 67.757 ;
     RECT  105.015 67.711 105.39 67.757 ;
     RECT  110.304 67.432 110.79 67.757 ;
     RECT  115.815 67.711 116.19 67.757 ;
     RECT  18.615 67.661 26.226 67.805 ;
     RECT  19.764 67.805 26.226 67.829 ;
     RECT  28.008 67.739 28.278 67.829 ;
     RECT  29.124 67.757 29.697 67.829 ;
     RECT  15.192 67.163 15.21 67.853 ;
     RECT  124.956 53.015 133.614 67.901 ;
     RECT  34.704 67.757 35.097 68.009 ;
     RECT  56.304 67.757 56.697 68.009 ;
     RECT  67.104 67.757 67.497 68.009 ;
     RECT  77.904 67.757 78.297 68.009 ;
     RECT  88.704 67.757 89.097 68.009 ;
     RECT  99.504 67.757 99.897 68.009 ;
     RECT  110.304 67.757 110.697 68.009 ;
     RECT  101.196 67.595 101.214 68.141 ;
     RECT  19.764 67.829 26.01 68.369 ;
     RECT  27.144 67.661 27.162 68.369 ;
     RECT  28.26 67.829 28.278 68.369 ;
     RECT  26.964 68.395 26.982 68.587 ;
     RECT  29.415 67.829 29.697 68.587 ;
     RECT  114.696 67.867 114.714 68.587 ;
     RECT  115.815 67.757 116.097 68.587 ;
     RECT  19.764 68.369 23.166 68.639 ;
     RECT  24.015 68.369 24.354 68.639 ;
     RECT  25.452 68.369 25.866 68.639 ;
     RECT  26.784 68.587 26.982 68.639 ;
     RECT  29.304 68.587 29.697 68.639 ;
     RECT  115.704 68.587 116.097 68.639 ;
     RECT  26.784 68.639 26.802 68.717 ;
     RECT  114.588 68.587 114.714 68.717 ;
     RECT  19.764 68.639 23.094 68.765 ;
     RECT  30.672 68.683 30.69 68.813 ;
     RECT  114.696 68.717 114.714 68.813 ;
     RECT  26.604 68.779 26.622 68.909 ;
     RECT  27.72 68.683 27.738 68.909 ;
     RECT  19.764 68.765 22.518 68.957 ;
     RECT  19.764 68.957 21.006 71.185 ;
     RECT  21.744 68.957 22.518 71.185 ;
     RECT  19.764 71.185 22.518 73.381 ;
     RECT  19.764 73.381 22.59 73.499 ;
     RECT  56.415 68.009 56.697 75.451 ;
     RECT  55.8 75.451 56.697 75.659 ;
     RECT  55.476 75.691 55.494 75.731 ;
     RECT  19.764 73.499 22.446 77.521 ;
     RECT  67.215 68.009 67.497 77.557 ;
     RECT  19.764 77.521 22.734 77.621 ;
     RECT  133.272 67.901 133.614 79.709 ;
     RECT  67.215 77.557 67.95 79.987 ;
     RECT  19.764 77.621 22.626 81.059 ;
     RECT  67.032 79.987 67.95 82.147 ;
     RECT  124.956 67.901 132.297 82.409 ;
     RECT  65.952 80.023 65.97 82.417 ;
     RECT  67.032 82.147 68.13 82.651 ;
     RECT  65.952 82.417 66.114 82.831 ;
     RECT  66.924 82.651 68.13 82.831 ;
     RECT  65.952 82.831 68.13 82.921 ;
     RECT  69.3 82.831 69.318 82.949 ;
     RECT  124.956 82.409 127.35 82.949 ;
     RECT  70.596 82.795 70.614 83.029 ;
     RECT  64.728 66.043 64.746 83.035 ;
     RECT  64.728 83.035 65.034 83.191 ;
     RECT  65.952 82.921 68.454 83.191 ;
     RECT  19.764 81.059 22.554 83.255 ;
     RECT  19.764 83.255 19.854 83.327 ;
     RECT  121.215 67.568 121.626 83.489 ;
     RECT  126.108 82.949 126.897 83.489 ;
     RECT  64.728 83.191 69.174 83.605 ;
     RECT  70.596 83.029 70.686 83.669 ;
     RECT  38.556 83.641 38.574 83.759 ;
     RECT  45.252 67.757 45.897 83.759 ;
     RECT  128.196 82.409 132.297 83.759 ;
     RECT  19.764 83.327 19.782 83.939 ;
     RECT  122.364 66.845 122.382 84.029 ;
     RECT  133.308 79.709 133.614 84.029 ;
     RECT  61.815 67.757 62.097 84.037 ;
     RECT  70.596 83.669 70.614 84.037 ;
     RECT  64.656 83.605 69.174 84.109 ;
     RECT  70.092 84.037 70.614 84.109 ;
     RECT  118.584 84.001 118.602 84.137 ;
     RECT  61.815 84.037 62.19 84.181 ;
     RECT  24.015 68.639 24.297 84.271 ;
     RECT  34.815 68.009 35.097 84.271 ;
     RECT  56.415 75.659 56.697 84.271 ;
     RECT  61.815 84.181 62.514 84.271 ;
     RECT  78.015 68.009 78.297 84.271 ;
     RECT  88.815 68.009 89.097 84.271 ;
     RECT  99.615 68.009 99.897 84.271 ;
     RECT  110.415 68.009 110.697 84.271 ;
     RECT  121.215 83.489 121.497 84.271 ;
     RECT  126.54 83.489 126.897 84.271 ;
     RECT  64.656 84.109 70.614 84.283 ;
     RECT  43.848 83.767 43.866 84.299 ;
     RECT  64.08 84.283 70.614 84.299 ;
     RECT  128.196 83.759 128.754 84.299 ;
     RECT  130.32 83.759 132.297 84.299 ;
     RECT  133.596 84.029 133.614 84.299 ;
     RECT  20.844 83.255 22.554 84.307 ;
     RECT  64.08 84.299 69.174 84.307 ;
     RECT  23.904 84.271 24.297 84.317 ;
     RECT  45.504 83.759 45.897 84.317 ;
     RECT  56.304 84.271 56.697 84.317 ;
     RECT  61.704 84.271 62.514 84.317 ;
     RECT  126.468 84.271 126.897 84.317 ;
     RECT  61.815 84.317 62.514 84.365 ;
     RECT  126.54 84.317 126.897 84.371 ;
     RECT  20.844 84.307 22.806 84.407 ;
     RECT  20.844 84.407 22.59 84.479 ;
     RECT  70.092 84.299 70.614 84.479 ;
     RECT  38.304 83.767 38.322 84.569 ;
     RECT  123.696 83.533 123.714 84.569 ;
     RECT  124.956 82.949 124.974 84.569 ;
     RECT  129.564 83.759 129.582 84.569 ;
     RECT  130.32 84.299 130.338 84.713 ;
     RECT  34.704 84.271 35.097 84.721 ;
     RECT  70.74 84.649 70.758 84.749 ;
     RECT  34.596 84.721 35.097 84.839 ;
     RECT  128.196 84.299 128.502 84.839 ;
     RECT  110.304 84.271 110.697 84.845 ;
     RECT  77.904 84.271 78.297 84.848 ;
     RECT  88.704 84.271 89.097 84.848 ;
     RECT  99.504 84.271 99.897 84.848 ;
     RECT  121.104 84.271 121.497 84.848 ;
     RECT  128.196 84.839 128.394 84.848 ;
     RECT  21.204 84.479 22.59 85.225 ;
     RECT  63.72 84.307 69.174 85.261 ;
     RECT  131.436 84.299 132.297 85.261 ;
     RECT  63.72 85.261 69.786 85.379 ;
     RECT  128.196 84.848 128.214 85.379 ;
     RECT  131.364 85.261 132.297 85.379 ;
     RECT  63.72 85.379 69.39 85.483 ;
     RECT  20.988 85.225 22.734 85.531 ;
     RECT  63.216 85.483 69.39 85.649 ;
     RECT  63.216 85.649 68.454 85.657 ;
     RECT  62.928 85.657 68.454 85.685 ;
     RECT  20.988 85.531 22.842 85.693 ;
     RECT  20.916 85.693 22.842 85.723 ;
     RECT  62.928 85.685 68.382 85.757 ;
     RECT  70.164 85.387 70.182 85.919 ;
     RECT  69.192 85.649 69.39 85.955 ;
     RECT  20.916 85.723 23.238 86.071 ;
     RECT  62.928 85.757 68.202 86.093 ;
     RECT  2.415 63.545 2.697 86.147 ;
     RECT  7.815 63.053 8.097 86.147 ;
     RECT  13.215 67.037 13.497 86.147 ;
     RECT  18.615 67.805 18.897 86.147 ;
     RECT  24.015 84.317 24.297 86.147 ;
     RECT  29.415 68.639 29.697 86.147 ;
     RECT  34.815 84.839 35.097 86.147 ;
     RECT  40.215 67.757 40.497 86.147 ;
     RECT  45.615 84.317 45.897 86.147 ;
     RECT  51.015 67.757 51.297 86.147 ;
     RECT  56.415 84.317 56.697 86.147 ;
     RECT  72.615 67.757 72.897 86.147 ;
     RECT  78.015 84.848 78.297 86.147 ;
     RECT  83.415 67.757 83.697 86.147 ;
     RECT  88.815 84.848 89.097 86.147 ;
     RECT  94.215 67.757 94.497 86.147 ;
     RECT  99.615 84.848 99.897 86.147 ;
     RECT  105.015 67.757 105.297 86.147 ;
     RECT  110.415 84.845 110.697 86.147 ;
     RECT  115.815 68.639 116.097 86.147 ;
     RECT  121.215 84.848 121.497 86.147 ;
     RECT  126.615 84.371 126.897 86.147 ;
     RECT  132.015 85.379 132.297 86.147 ;
     RECT  137.415 53.825 137.697 86.147 ;
     RECT  20.844 86.071 23.238 86.189 ;
     RECT  69.372 85.955 69.39 86.189 ;
     RECT  65.124 86.093 68.202 86.237 ;
     RECT  65.124 86.237 67.305 86.261 ;
     RECT  61.815 84.365 62.097 86.269 ;
     RECT  62.928 86.093 64.35 86.269 ;
     RECT  20.844 86.189 23.058 86.305 ;
     RECT  68.184 86.237 68.202 86.333 ;
     RECT  61.815 86.269 64.35 86.369 ;
     RECT  63.216 86.369 64.35 86.381 ;
     RECT  2.415 86.147 2.505 86.417 ;
     RECT  7.815 86.147 7.905 86.417 ;
     RECT  13.215 86.147 13.305 86.417 ;
     RECT  18.615 86.147 18.705 86.417 ;
     RECT  24.015 86.147 24.105 86.417 ;
     RECT  29.415 86.147 29.505 86.417 ;
     RECT  34.815 86.147 34.905 86.417 ;
     RECT  40.215 86.147 40.305 86.417 ;
     RECT  45.615 86.147 45.705 86.417 ;
     RECT  51.015 86.147 51.105 86.417 ;
     RECT  56.415 86.147 56.505 86.417 ;
     RECT  61.815 86.369 61.905 86.417 ;
     RECT  66.708 86.261 67.305 86.417 ;
     RECT  72.615 86.147 72.705 86.417 ;
     RECT  78.015 86.147 78.105 86.417 ;
     RECT  83.415 86.147 83.505 86.417 ;
     RECT  88.815 86.147 88.905 86.417 ;
     RECT  94.215 86.147 94.305 86.417 ;
     RECT  99.615 86.147 99.705 86.417 ;
     RECT  105.015 86.147 105.105 86.417 ;
     RECT  110.415 86.147 110.505 86.417 ;
     RECT  115.815 86.147 115.905 86.417 ;
     RECT  121.215 86.147 121.305 86.417 ;
     RECT  126.615 86.147 126.705 86.417 ;
     RECT  132.015 86.147 132.105 86.417 ;
     RECT  137.415 86.147 137.505 86.417 ;
     RECT  20.664 86.305 23.058 86.573 ;
     RECT  20.664 86.573 21.69 86.621 ;
     RECT  23.04 86.573 23.058 86.621 ;
     RECT  63.216 86.381 64.17 86.621 ;
     RECT  63.324 86.621 64.17 86.669 ;
     RECT  66.708 86.417 66.726 86.669 ;
     RECT  21.132 86.621 21.15 87.197 ;
     RECT  65.124 86.261 65.61 87.197 ;
     RECT  63.324 86.669 63.774 87.245 ;
     RECT  63.324 87.245 63.486 87.293 ;
     RECT  63.468 87.293 63.486 87.821 ;
     RECT  20.988 88.315 21.402 88.445 ;
     RECT  65.16 88.315 65.358 88.445 ;
    LAYER M4 ;
     RECT  0.06 50.256 0.133 62.472 ;
     RECT  0.06 21.072 0.173 27.144 ;
     RECT  0.06 31.056 0.173 37.128 ;
     RECT  0.173 21.072 0.569 26.952 ;
     RECT  0.173 31.056 0.569 37.032 ;
     RECT  0.569 21.36 1.253 26.952 ;
     RECT  2.252 19.92 2.408 19.944 ;
     RECT  1.253 21.36 2.408 26.856 ;
     RECT  0.569 31.344 2.408 37.032 ;
     RECT  0.133 50.064 2.408 62.472 ;
     RECT  2.408 2.148 2.512 86.412 ;
     RECT  2.512 2.418 2.704 86.142 ;
     RECT  2.704 32.208 2.765 35.016 ;
     RECT  2.704 36.624 2.765 37.032 ;
     RECT  2.765 32.304 2.837 35.016 ;
     RECT  2.704 19.824 2.953 27.96 ;
     RECT  2.837 34.704 3.017 34.776 ;
     RECT  2.704 49.872 3.059 64.008 ;
     RECT  2.953 19.824 3.125 27.384 ;
     RECT  3.125 19.824 3.251 26.808 ;
     RECT  2.765 37.008 3.395 37.032 ;
     RECT  3.017 34.704 3.449 34.728 ;
     RECT  2.837 32.304 3.845 33.288 ;
     RECT  2.704 38.208 3.925 38.232 ;
     RECT  3.059 49.92 3.949 64.008 ;
     RECT  3.845 32.304 3.985 32.952 ;
     RECT  3.251 19.92 3.997 26.808 ;
     RECT  3.949 49.92 4.021 64.056 ;
     RECT  3.805 28.416 4.057 28.44 ;
     RECT  3.985 31.776 4.093 32.952 ;
     RECT  4.021 49.536 4.124 64.056 ;
     RECT  3.997 26.688 4.133 26.808 ;
     RECT  4.057 27.936 4.133 28.44 ;
     RECT  4.093 31.104 4.165 32.952 ;
     RECT  4.165 30.816 4.277 32.952 ;
     RECT  4.133 27.936 4.345 27.96 ;
     RECT  4.309 29.76 4.381 29.784 ;
     RECT  3.997 19.92 4.499 25.656 ;
     RECT  3.925 38.16 4.501 38.232 ;
     RECT  2.704 39.36 4.501 39.384 ;
     RECT  4.124 49.488 4.501 64.056 ;
     RECT  4.345 26.832 4.547 27.96 ;
     RECT  4.499 19.92 4.565 25.176 ;
     RECT  4.501 38.16 4.588 39.432 ;
     RECT  4.277 31.104 4.745 32.952 ;
     RECT  4.745 31.248 4.849 32.952 ;
     RECT  4.849 31.248 4.885 33.096 ;
     RECT  4.588 38.16 4.889 38.76 ;
     RECT  4.565 22.656 5.123 25.176 ;
     RECT  4.885 31.248 5.285 33.864 ;
     RECT  4.633 36.48 5.389 36.504 ;
     RECT  4.547 26.832 5.393 27.912 ;
     RECT  4.565 19.92 5.411 21.672 ;
     RECT  4.501 49.44 5.42 64.056 ;
     RECT  5.42 49.392 5.507 64.056 ;
     RECT  5.389 36.48 5.533 36.936 ;
     RECT  4.889 38.16 5.533 38.232 ;
     RECT  5.507 49.488 5.555 64.056 ;
     RECT  4.993 35.328 5.569 35.352 ;
     RECT  5.533 36.48 5.573 38.232 ;
     RECT  4.381 28.992 5.677 29.784 ;
     RECT  5.569 34.944 5.681 35.352 ;
     RECT  5.285 31.248 5.725 33.816 ;
     RECT  5.411 20.544 5.747 21.672 ;
     RECT  5.123 22.656 5.747 25.128 ;
     RECT  5.747 22.704 5.753 25.128 ;
     RECT  5.393 26.832 5.789 27.24 ;
     RECT  5.753 25.104 5.825 25.128 ;
     RECT  5.681 35.328 5.861 35.352 ;
     RECT  5.725 31.248 5.933 32.568 ;
     RECT  5.789 26.832 5.965 26.856 ;
     RECT  5.677 28.224 5.996 29.784 ;
     RECT  5.996 28.224 6.037 30.024 ;
     RECT  5.555 50.016 6.041 64.056 ;
     RECT  6.037 28.224 6.083 30.312 ;
     RECT  6.041 50.016 6.179 63.96 ;
     RECT  6.083 28.224 6.221 29.112 ;
     RECT  6.179 50.016 6.229 63.864 ;
     RECT  6.236 25.632 6.323 25.656 ;
     RECT  5.725 33.792 6.323 33.816 ;
     RECT  6.083 30.24 6.409 30.312 ;
     RECT  5.753 22.704 6.437 24.12 ;
     RECT  5.933 31.536 6.545 32.568 ;
     RECT  6.229 50.016 6.563 63.72 ;
     RECT  5.747 20.544 6.649 20.568 ;
     RECT  5.573 36.48 6.689 37.608 ;
     RECT  6.437 24.096 6.716 24.12 ;
     RECT  6.689 37.584 6.757 37.608 ;
     RECT  5.965 26.64 6.793 26.856 ;
     RECT  6.221 28.224 6.793 28.248 ;
     RECT  6.037 35.472 6.793 35.496 ;
     RECT  5.747 21.648 6.803 21.672 ;
     RECT  6.716 24.096 6.803 24.648 ;
     RECT  6.793 26.64 6.803 28.248 ;
     RECT  6.793 35.472 6.803 36.216 ;
     RECT  6.437 22.704 6.829 22.824 ;
     RECT  6.649 20.448 6.865 20.568 ;
     RECT  6.409 30.288 7.009 30.312 ;
     RECT  6.545 31.536 7.009 32.472 ;
     RECT  6.325 13.584 7.081 13.608 ;
     RECT  6.829 22.656 7.369 22.824 ;
     RECT  7.009 15.792 7.441 15.816 ;
     RECT  7.297 33.648 7.621 33.672 ;
     RECT  6.865 20.448 7.765 20.952 ;
     RECT  7.369 22.032 7.765 22.824 ;
     RECT  6.685 11.424 7.808 11.448 ;
     RECT  7.081 13.584 7.808 14.232 ;
     RECT  7.441 15.792 7.808 16.536 ;
     RECT  7.765 20.448 7.808 22.824 ;
     RECT  6.803 24.096 7.808 24.12 ;
     RECT  6.803 26.64 7.808 27.48 ;
     RECT  7.009 30.288 7.808 32.472 ;
     RECT  7.621 33.648 7.808 33.912 ;
     RECT  6.803 36.192 7.808 36.216 ;
     RECT  6.757 37.584 7.808 38.088 ;
     RECT  7.381 47.856 7.808 47.88 ;
     RECT  6.563 50.016 7.808 63.048 ;
     RECT  6.517 67.008 7.808 67.032 ;
     RECT  7.808 2.148 7.912 86.412 ;
     RECT  7.912 2.418 8.104 86.142 ;
     RECT  8.104 56.256 8.165 63.048 ;
     RECT  8.104 37.584 8.237 38.472 ;
     RECT  8.104 26.64 8.243 27.576 ;
     RECT  8.165 56.256 8.345 60.696 ;
     RECT  8.165 62.544 8.345 63.048 ;
     RECT  8.104 32.304 8.381 32.328 ;
     RECT  8.104 51.12 8.381 52.92 ;
     RECT  8.345 56.496 8.381 60.696 ;
     RECT  8.104 25.104 8.417 25.128 ;
     RECT  8.381 56.496 8.453 58.92 ;
     RECT  8.104 35.136 8.489 36.552 ;
     RECT  8.345 62.736 8.489 63.048 ;
     RECT  8.453 57.072 8.525 58.92 ;
     RECT  8.381 60.048 8.597 60.696 ;
     RECT  8.525 57.072 8.669 58.68 ;
     RECT  8.489 62.736 8.957 62.76 ;
     RECT  8.597 60.048 9.029 60.072 ;
     RECT  8.381 52.224 9.245 52.92 ;
     RECT  8.104 10.848 9.301 11.448 ;
     RECT  8.669 58.656 9.317 58.68 ;
     RECT  8.104 19.632 9.349 22.296 ;
     RECT  8.104 30.288 9.349 31.128 ;
     RECT  8.104 33.888 9.349 33.912 ;
     RECT  8.104 13.392 9.445 14.232 ;
     RECT  8.104 15.264 9.445 16.536 ;
     RECT  8.104 54 9.497 54.648 ;
     RECT  9.497 54.384 9.601 54.648 ;
     RECT  9.301 10.704 9.637 11.448 ;
     RECT  8.489 35.136 9.637 35.352 ;
     RECT  8.489 36.48 9.637 36.552 ;
     RECT  9.349 33.648 9.673 33.912 ;
     RECT  9.637 35.136 9.673 36.552 ;
     RECT  9.673 33.648 9.721 36.552 ;
     RECT  9.349 9.504 9.733 9.528 ;
     RECT  9.637 10.704 9.733 12.216 ;
     RECT  9.721 33.648 9.781 35.352 ;
     RECT  9.781 33.072 9.785 35.352 ;
     RECT  9.349 30.288 9.817 31.368 ;
     RECT  8.669 57.072 9.821 57.432 ;
     RECT  9.817 30.288 9.971 31.944 ;
     RECT  9.889 25.104 10.019 25.128 ;
     RECT  9.601 54.384 10.073 55.32 ;
     RECT  9.821 57.216 10.145 57.432 ;
     RECT  9.971 30.288 10.225 31.368 ;
     RECT  9.733 9.504 10.357 12.216 ;
     RECT  9.445 13.392 10.357 16.536 ;
     RECT  8.243 27.456 10.357 27.48 ;
     RECT  9.785 33.072 10.405 35.16 ;
     RECT  10.357 9.504 10.453 16.536 ;
     RECT  9.245 52.272 10.577 52.92 ;
     RECT  10.405 33.648 10.643 35.16 ;
     RECT  10.643 33.648 10.793 33.912 ;
     RECT  8.237 38.112 10.825 38.472 ;
     RECT  10.073 54.384 10.829 54.696 ;
     RECT  10.793 33.648 10.835 33.816 ;
     RECT  10.145 57.216 10.865 57.336 ;
     RECT  10.829 54.576 10.901 54.696 ;
     RECT  10.501 59.76 10.973 59.784 ;
     RECT  10.643 35.136 10.997 35.16 ;
     RECT  9.721 36.48 10.997 36.552 ;
     RECT  9.817 63.312 11.005 63.336 ;
     RECT  10.789 61.68 11.261 61.704 ;
     RECT  11.005 63.12 11.405 63.336 ;
     RECT  10.577 52.272 11.441 52.296 ;
     RECT  10.997 35.136 11.485 36.552 ;
     RECT  10.357 27.456 11.653 27.768 ;
     RECT  11.365 58.752 11.801 58.776 ;
     RECT  11.485 35.136 11.809 35.352 ;
     RECT  10.865 57.312 12.589 57.336 ;
     RECT  11.405 63.312 13.021 63.336 ;
     RECT  11.809 35.136 13.085 35.16 ;
     RECT  11.653 27.168 13.165 27.768 ;
     RECT  10.453 9.504 13.208 16.872 ;
     RECT  9.349 19.104 13.208 22.296 ;
     RECT  13.165 26.64 13.208 27.768 ;
     RECT  10.225 30.288 13.208 31.128 ;
     RECT  10.835 33.792 13.208 33.816 ;
     RECT  13.085 34.8 13.208 35.16 ;
     RECT  11.485 36.48 13.208 36.552 ;
     RECT  10.825 37.968 13.208 38.472 ;
     RECT  8.104 47.856 13.208 47.88 ;
     RECT  12.301 52.176 13.208 52.2 ;
     RECT  10.901 54.672 13.208 54.696 ;
     RECT  12.589 57.312 13.208 57.96 ;
     RECT  13.021 63.312 13.208 63.576 ;
     RECT  8.104 67.008 13.208 67.032 ;
     RECT  13.208 2.148 13.312 86.412 ;
     RECT  13.312 2.418 13.504 86.142 ;
     RECT  13.504 33.792 13.619 39.384 ;
     RECT  13.504 42.72 13.619 43.032 ;
     RECT  13.504 57.312 13.709 57.96 ;
     RECT  13.504 26.64 14.497 27.768 ;
     RECT  13.504 29.04 14.497 29.928 ;
     RECT  13.619 39.36 14.497 39.384 ;
     RECT  13.504 40.704 14.497 40.728 ;
     RECT  14.497 39.36 14.533 40.728 ;
     RECT  13.504 67.008 14.533 67.032 ;
     RECT  13.504 54.576 14.537 54.696 ;
     RECT  13.504 19.056 14.569 22.296 ;
     RECT  13.504 62.592 14.581 63.816 ;
     RECT  14.569 19.056 14.641 22.872 ;
     RECT  14.533 67.008 14.677 67.176 ;
     RECT  14.497 26.64 14.717 29.928 ;
     RECT  13.619 42.72 14.741 42.744 ;
     RECT  14.533 39.36 14.749 41.016 ;
     RECT  14.641 18.432 14.773 22.872 ;
     RECT  14.537 54.576 14.789 54.648 ;
     RECT  14.717 26.64 14.821 28.92 ;
     RECT  14.785 53.04 14.857 53.064 ;
     RECT  13.504 31.104 14.929 32.76 ;
     RECT  14.857 52.224 14.969 53.064 ;
     RECT  13.709 57.312 14.969 57.576 ;
     RECT  13.504 44.208 15.077 45.288 ;
     RECT  13.619 33.792 15.113 37.992 ;
     RECT  14.773 18.432 15.181 23.64 ;
     RECT  14.677 66.192 15.181 67.176 ;
     RECT  14.741 42.192 15.185 42.744 ;
     RECT  15.181 66.192 15.217 67.848 ;
     RECT  14.749 39.36 15.361 41.112 ;
     RECT  15.077 44.208 15.361 44.904 ;
     RECT  15.113 37.056 15.365 37.992 ;
     RECT  15.113 33.792 15.373 35.4 ;
     RECT  15.365 37.584 15.505 37.992 ;
     RECT  14.929 30.72 15.613 32.76 ;
     RECT  15.373 33.792 15.613 35.352 ;
     RECT  15.253 59.184 15.653 59.208 ;
     RECT  15.217 65.76 15.733 67.848 ;
     RECT  15.361 39.36 15.769 42.168 ;
     RECT  15.793 49.632 15.865 49.656 ;
     RECT  15.505 37.584 15.893 38.184 ;
     RECT  15.613 30.72 15.901 35.352 ;
     RECT  13.504 47.28 15.901 48.264 ;
     RECT  15.865 49.248 15.901 49.656 ;
     RECT  14.821 26.208 15.937 28.92 ;
     RECT  14.581 62.592 15.941 64.68 ;
     RECT  15.901 46.368 15.949 49.656 ;
     RECT  14.969 57.312 15.977 57.336 ;
     RECT  14.789 54.624 16.013 54.648 ;
     RECT  15.937 26.112 16.045 28.92 ;
     RECT  15.901 30.144 16.045 35.352 ;
     RECT  15.941 63.024 16.165 64.68 ;
     RECT  15.733 65.76 16.165 68.808 ;
     RECT  15.361 44.16 16.181 44.904 ;
     RECT  15.949 46.368 16.181 46.728 ;
     RECT  16.181 44.16 16.229 46.728 ;
     RECT  15.973 60.864 16.229 60.888 ;
     RECT  16.229 44.16 16.265 46.536 ;
     RECT  15.901 50.832 16.265 50.856 ;
     RECT  16.045 26.112 16.369 35.352 ;
     RECT  16.265 44.16 16.441 45.144 ;
     RECT  16.265 46.128 16.453 46.536 ;
     RECT  13.504 9.504 16.585 16.872 ;
     RECT  16.369 26.112 16.589 35.928 ;
     RECT  16.585 9.504 16.597 17.208 ;
     RECT  15.181 18.192 16.597 23.64 ;
     RECT  15.769 39.36 16.633 42.072 ;
     RECT  15.893 37.584 16.643 38.232 ;
     RECT  16.873 36.24 17.017 36.264 ;
     RECT  16.633 39.888 17.017 42.072 ;
     RECT  16.453 46.368 17.021 46.536 ;
     RECT  16.589 26.112 17.089 34.728 ;
     RECT  17.017 39.888 17.165 42.888 ;
     RECT  16.441 43.968 17.165 45.144 ;
     RECT  17.017 36.24 17.197 36.504 ;
     RECT  16.643 37.584 17.197 37.704 ;
     RECT  17.165 43.968 17.219 45.048 ;
     RECT  17.219 43.968 17.269 45 ;
     RECT  17.021 46.512 17.413 46.536 ;
     RECT  15.949 47.76 17.413 49.656 ;
     RECT  17.089 51.696 17.629 51.72 ;
     RECT  17.089 25.632 17.701 34.728 ;
     RECT  17.197 36.24 17.701 37.704 ;
     RECT  17.629 50.88 17.953 51.72 ;
     RECT  17.413 46.512 18.017 49.656 ;
     RECT  17.953 50.832 18.017 51.72 ;
     RECT  17.953 38.976 18.025 39 ;
     RECT  18.025 38.688 18.161 39 ;
     RECT  17.165 40.32 18.161 42.888 ;
     RECT  17.701 25.632 18.169 37.704 ;
     RECT  17.269 43.872 18.205 45 ;
     RECT  18.161 38.688 18.241 42.888 ;
     RECT  18.205 43.872 18.241 45.48 ;
     RECT  17.089 56.304 18.241 56.328 ;
     RECT  18.169 25.296 18.277 37.704 ;
     RECT  18.017 46.512 18.277 51.72 ;
     RECT  14.969 53.04 18.277 53.064 ;
     RECT  18.241 38.688 18.565 45.48 ;
     RECT  18.277 46.512 18.565 53.064 ;
     RECT  16.597 9.504 18.608 23.64 ;
     RECT  18.277 24.912 18.608 37.704 ;
     RECT  18.565 38.688 18.608 53.064 ;
     RECT  18.241 56.304 18.608 56.856 ;
     RECT  16.513 60.624 18.608 60.648 ;
     RECT  16.165 63.024 18.608 68.808 ;
     RECT  18.608 2.148 18.712 86.412 ;
     RECT  18.712 2.418 18.904 86.142 ;
     RECT  18.904 9.504 19.325 47.784 ;
     RECT  18.904 48.768 19.837 53.928 ;
     RECT  19.837 50.928 19.897 53.928 ;
     RECT  19.325 25.008 19.969 47.784 ;
     RECT  19.837 48.768 19.969 49.896 ;
     RECT  19.897 50.928 19.969 54.12 ;
     RECT  18.904 56.304 19.969 57.576 ;
     RECT  19.969 50.928 20.012 54.984 ;
     RECT  19.969 56.304 20.012 57.864 ;
     RECT  20.012 50.928 20.077 57.864 ;
     RECT  20.077 50.928 20.189 58.728 ;
     RECT  18.904 60.528 20.437 60.552 ;
     RECT  18.904 61.68 20.617 61.992 ;
     RECT  18.904 63.024 20.617 68.808 ;
     RECT  19.969 25.008 20.761 49.896 ;
     RECT  19.325 9.504 20.821 23.688 ;
     RECT  20.761 24.816 20.821 49.896 ;
     RECT  20.437 60.528 20.833 60.648 ;
     RECT  20.821 9.504 20.869 49.896 ;
     RECT  20.189 50.928 20.869 58.344 ;
     RECT  20.053 85.536 20.876 85.56 ;
     RECT  20.653 86.592 20.876 86.616 ;
     RECT  20.677 88.416 20.917 88.44 ;
     RECT  20.833 59.664 21.013 60.648 ;
     RECT  20.617 61.68 21.013 68.808 ;
     RECT  20.876 85.536 21.061 86.616 ;
     RECT  21.061 85.536 21.161 87.192 ;
     RECT  19.909 83.232 21.253 83.256 ;
     RECT  20.869 9.504 21.265 58.344 ;
     RECT  21.013 59.664 21.265 68.808 ;
     RECT  21.265 9.504 21.269 68.808 ;
     RECT  21.253 83.232 21.301 84.168 ;
     RECT  21.161 85.536 21.301 86.664 ;
     RECT  21.301 83.232 21.587 86.664 ;
     RECT  20.917 88.32 21.587 88.44 ;
     RECT  21.269 10.032 21.625 68.808 ;
     RECT  21.587 88.32 21.635 88.344 ;
     RECT  21.587 83.232 21.769 86.616 ;
     RECT  21.769 82.56 21.875 86.616 ;
     RECT  21.875 83.088 21.923 86.616 ;
     RECT  21.949 80.928 22.033 80.952 ;
     RECT  21.923 83.232 22.277 86.616 ;
     RECT  21.625 10.032 22.345 68.952 ;
     RECT  22.277 83.616 22.355 86.616 ;
     RECT  22.355 84.288 22.601 86.616 ;
     RECT  22.601 85.536 22.853 86.616 ;
     RECT  22.853 85.728 23.069 86.616 ;
     RECT  22.345 9.504 24.008 68.952 ;
     RECT  22.601 84.288 24.008 84.312 ;
     RECT  23.069 85.728 24.008 86.412 ;
     RECT  24.008 2.148 24.112 86.412 ;
     RECT  24.112 2.418 24.304 86.142 ;
     RECT  24.304 9.504 29.408 68.952 ;
     RECT  24.304 84.288 29.408 84.312 ;
     RECT  24.304 85.728 29.408 85.752 ;
     RECT  29.408 2.148 29.512 86.412 ;
     RECT  29.512 2.418 29.704 86.142 ;
     RECT  29.704 9.504 34.808 68.952 ;
     RECT  29.704 84.288 34.808 84.312 ;
     RECT  29.704 85.728 34.808 85.752 ;
     RECT  34.808 2.148 34.912 86.412 ;
     RECT  34.912 2.418 35.104 86.142 ;
     RECT  35.104 9.504 40.208 68.952 ;
     RECT  35.104 84.288 40.208 84.312 ;
     RECT  35.104 85.728 40.208 85.752 ;
     RECT  40.208 2.148 40.312 86.412 ;
     RECT  40.312 2.418 40.504 86.142 ;
     RECT  40.504 9.504 45.608 68.952 ;
     RECT  40.504 84.288 45.608 84.312 ;
     RECT  40.504 85.728 45.608 85.752 ;
     RECT  45.608 2.148 45.712 86.412 ;
     RECT  45.712 2.418 45.904 86.142 ;
     RECT  45.904 9.504 51.008 68.952 ;
     RECT  47.221 75.456 51.008 75.48 ;
     RECT  45.904 84.288 51.008 84.312 ;
     RECT  45.904 85.728 51.008 85.752 ;
     RECT  51.008 2.148 51.112 86.412 ;
     RECT  51.112 2.418 51.304 86.142 ;
     RECT  51.304 75.456 55.465 75.48 ;
     RECT  51.304 9.504 56.408 68.952 ;
     RECT  55.465 75.456 56.408 75.72 ;
     RECT  51.304 84.288 56.408 84.312 ;
     RECT  51.304 85.728 56.408 85.752 ;
     RECT  56.408 2.148 56.512 86.412 ;
     RECT  56.512 2.418 56.704 86.142 ;
     RECT  56.704 9.504 61.808 68.952 ;
     RECT  56.704 75.696 61.808 75.72 ;
     RECT  56.704 84.288 61.808 84.312 ;
     RECT  56.704 85.728 61.808 85.752 ;
     RECT  61.808 2.148 61.912 86.412 ;
     RECT  61.912 2.418 62.104 86.142 ;
     RECT  62.104 85.728 62.957 85.752 ;
     RECT  63.205 85.488 63.289 85.512 ;
     RECT  63.205 86.592 63.313 86.616 ;
     RECT  63.313 86.592 63.457 87.288 ;
     RECT  62.104 75.696 63.731 75.72 ;
     RECT  62.104 84.048 63.853 84.36 ;
     RECT  63.457 86.592 63.973 87.816 ;
     RECT  63.973 86.592 64.307 88.392 ;
     RECT  64.307 86.592 64.309 87.192 ;
     RECT  63.853 84.048 64.453 85.32 ;
     RECT  64.309 86.352 64.453 87.192 ;
     RECT  64.453 84.048 64.691 87.192 ;
     RECT  64.307 88.272 65.105 88.392 ;
     RECT  65.005 83.04 65.149 83.064 ;
     RECT  64.691 84.048 65.149 86.088 ;
     RECT  65.105 88.272 65.315 88.44 ;
     RECT  65.149 83.04 65.333 86.088 ;
     RECT  65.333 83.04 65.341 85.992 ;
     RECT  65.315 88.32 65.369 88.44 ;
     RECT  65.369 88.32 65.411 88.344 ;
     RECT  64.691 87.168 65.621 87.192 ;
     RECT  65.341 83.04 66.373 85.8 ;
     RECT  66.373 83.04 66.469 86.088 ;
     RECT  66.373 88.368 66.563 88.392 ;
     RECT  66.469 83.04 66.633 86.28 ;
     RECT  66.633 83.04 66.745 86.664 ;
     RECT  66.745 83.04 66.86 86.412 ;
     RECT  66.86 82.944 66.913 86.412 ;
     RECT  62.104 9.504 67.208 68.952 ;
     RECT  66.949 79.728 67.208 79.752 ;
     RECT  66.913 82.656 67.208 86.412 ;
     RECT  67.208 2.148 67.312 86.412 ;
     RECT  67.312 2.418 67.504 86.28 ;
     RECT  67.504 83.04 67.619 86.28 ;
     RECT  67.619 86.064 68.213 86.28 ;
     RECT  67.619 83.04 68.357 84.984 ;
     RECT  68.213 86.064 68.387 86.088 ;
     RECT  68.357 83.232 68.821 84.984 ;
     RECT  68.821 83.232 69.005 85.512 ;
     RECT  69.005 84.288 69.221 85.512 ;
     RECT  67.504 9.504 72.608 68.952 ;
     RECT  67.504 79.728 72.608 79.752 ;
     RECT  69.221 84.288 72.608 84.84 ;
     RECT  72.608 2.148 72.712 86.412 ;
     RECT  72.712 2.418 72.904 86.142 ;
     RECT  72.904 9.504 78.008 68.952 ;
     RECT  72.904 79.728 78.008 79.752 ;
     RECT  72.904 84.288 78.008 84.84 ;
     RECT  78.008 2.148 78.112 86.412 ;
     RECT  78.112 2.418 78.304 86.142 ;
     RECT  78.304 9.504 83.408 68.952 ;
     RECT  78.304 79.728 83.408 79.752 ;
     RECT  78.304 84.288 83.408 84.84 ;
     RECT  83.408 2.148 83.512 86.412 ;
     RECT  83.512 2.418 83.704 86.142 ;
     RECT  83.704 9.504 88.808 68.952 ;
     RECT  83.704 79.728 88.808 79.752 ;
     RECT  83.704 84.288 88.808 84.84 ;
     RECT  88.808 2.148 88.912 86.412 ;
     RECT  88.912 2.418 89.104 86.142 ;
     RECT  89.104 9.504 94.208 68.952 ;
     RECT  89.104 79.728 94.208 79.752 ;
     RECT  89.104 84.288 94.208 84.84 ;
     RECT  94.208 2.148 94.312 86.412 ;
     RECT  94.312 2.418 94.504 86.142 ;
     RECT  94.504 9.504 99.608 68.952 ;
     RECT  94.504 79.728 99.608 79.752 ;
     RECT  94.504 84.288 99.608 84.84 ;
     RECT  99.608 2.148 99.712 86.412 ;
     RECT  99.712 2.418 99.904 86.142 ;
     RECT  99.904 9.504 105.008 68.952 ;
     RECT  99.904 79.728 105.008 79.752 ;
     RECT  99.904 84.288 105.008 84.84 ;
     RECT  105.008 2.148 105.112 86.412 ;
     RECT  105.112 2.418 105.304 86.142 ;
     RECT  105.304 9.504 110.408 68.952 ;
     RECT  105.304 79.728 110.408 79.752 ;
     RECT  105.304 84.288 110.408 84.84 ;
     RECT  110.408 2.148 110.512 86.412 ;
     RECT  110.512 2.418 110.704 86.142 ;
     RECT  110.704 9.504 115.808 68.952 ;
     RECT  110.704 79.728 115.808 79.752 ;
     RECT  110.704 84.288 115.808 84.84 ;
     RECT  115.808 2.148 115.912 86.412 ;
     RECT  115.912 2.418 116.104 86.142 ;
     RECT  116.104 9.504 117.216 68.952 ;
     RECT  117.216 9.504 117.389 63.72 ;
     RECT  117.389 9.504 117.425 63.624 ;
     RECT  117.425 9.504 117.461 45.432 ;
     RECT  117.425 52.368 117.461 63.624 ;
     RECT  117.425 46.704 118.001 50.184 ;
     RECT  117.461 52.368 118.001 54.216 ;
     RECT  117.461 55.344 118.001 59.88 ;
     RECT  117.461 61.488 118.001 63.336 ;
     RECT  118.001 46.704 118.037 47.592 ;
     RECT  118.001 52.368 118.037 52.392 ;
     RECT  118.001 55.728 118.037 57 ;
     RECT  118.001 61.488 118.037 62.088 ;
     RECT  117.216 64.992 118.307 68.952 ;
     RECT  117.461 37.104 118.453 45.432 ;
     RECT  118.453 37.104 118.597 45.72 ;
     RECT  118.307 64.992 118.643 68.76 ;
     RECT  117.461 9.504 118.645 36.072 ;
     RECT  118.597 37.104 118.645 46.008 ;
     RECT  118.645 9.504 118.835 46.008 ;
     RECT  118.643 64.992 118.883 68.664 ;
     RECT  118.883 64.992 119.075 68.52 ;
     RECT  118.835 10.128 119.117 46.008 ;
     RECT  119.117 10.128 119.549 37.224 ;
     RECT  119.549 25.2 119.585 37.224 ;
     RECT  119.117 38.928 119.657 38.952 ;
     RECT  118.001 63.312 119.657 63.336 ;
     RECT  119.585 25.584 119.693 37.224 ;
     RECT  119.693 25.584 119.701 37.176 ;
     RECT  119.701 25.584 119.765 35.88 ;
     RECT  119.765 25.584 119.801 35.544 ;
     RECT  119.801 26.112 119.873 35.544 ;
     RECT  119.873 26.112 119.891 29.112 ;
     RECT  119.873 30.336 119.891 35.544 ;
     RECT  119.891 33.072 119.939 35.544 ;
     RECT  119.891 26.928 119.981 29.112 ;
     RECT  119.891 30.336 120.035 31.992 ;
     RECT  119.117 40.128 120.089 46.008 ;
     RECT  119.981 27.168 120.179 29.112 ;
     RECT  120.089 40.128 120.997 42.024 ;
     RECT  120.035 30.336 121.093 31.944 ;
     RECT  119.939 33.552 121.093 35.544 ;
     RECT  119.549 10.128 121.208 24.216 ;
     RECT  120.179 27.168 121.208 28.296 ;
     RECT  121.093 30.336 121.208 35.544 ;
     RECT  119.701 37.152 121.208 37.176 ;
     RECT  121.045 38.688 121.208 38.712 ;
     RECT  120.997 40.08 121.208 42.024 ;
     RECT  120.089 43.008 121.208 46.008 ;
     RECT  118.037 47.136 121.208 47.592 ;
     RECT  119.075 64.992 121.208 67.896 ;
     RECT  116.104 79.728 121.208 79.752 ;
     RECT  116.104 84.288 121.208 84.84 ;
     RECT  121.208 2.148 121.312 86.412 ;
     RECT  121.312 2.418 121.504 86.142 ;
     RECT  121.504 27.168 121.601 28.296 ;
     RECT  121.504 40.08 121.601 46.008 ;
     RECT  121.504 10.128 121.619 24.216 ;
     RECT  121.504 30.288 121.763 31.944 ;
     RECT  121.763 30.288 121.859 31.464 ;
     RECT  121.504 32.976 122.051 35.592 ;
     RECT  121.619 10.608 122.387 24.216 ;
     RECT  122.051 32.976 122.387 34.44 ;
     RECT  121.601 40.128 122.533 46.008 ;
     RECT  121.504 47.136 122.533 47.592 ;
     RECT  122.387 12.768 122.573 24.216 ;
     RECT  122.051 35.424 122.725 35.592 ;
     RECT  121.504 37.296 122.773 38.712 ;
     RECT  122.533 40.128 122.773 47.592 ;
     RECT  122.573 13.344 122.819 24.216 ;
     RECT  122.819 14.448 122.867 24.216 ;
     RECT  122.819 13.344 122.915 13.416 ;
     RECT  122.387 10.608 122.963 11.208 ;
     RECT  122.867 14.688 123.011 24.216 ;
     RECT  122.963 10.992 123.059 11.208 ;
     RECT  122.725 35.424 123.061 36.024 ;
     RECT  122.773 37.296 123.061 47.592 ;
     RECT  123.059 11.184 123.395 11.208 ;
     RECT  122.387 32.976 125.557 34.248 ;
     RECT  125.557 32.496 125.641 34.248 ;
     RECT  121.859 30.288 125.773 30.6 ;
     RECT  121.601 27.312 125.845 28.296 ;
     RECT  125.773 29.664 125.845 30.6 ;
     RECT  123.061 35.424 126.349 47.592 ;
     RECT  123.011 14.784 126.601 24.216 ;
     RECT  122.915 13.344 126.608 13.368 ;
     RECT  126.601 14.688 126.608 24.216 ;
     RECT  126.349 26.064 126.608 26.088 ;
     RECT  125.845 27.312 126.608 30.6 ;
     RECT  125.641 32.976 126.608 34.248 ;
     RECT  126.349 35.424 126.608 47.928 ;
     RECT  121.504 64.992 126.608 67.896 ;
     RECT  121.504 79.728 126.608 79.752 ;
     RECT  121.504 84.288 126.608 84.84 ;
     RECT  126.608 2.148 126.712 86.412 ;
     RECT  126.712 2.418 126.904 86.142 ;
     RECT  126.904 14.688 127.613 26.088 ;
     RECT  126.904 27.072 127.708 31.992 ;
     RECT  126.904 32.976 127.721 42.216 ;
     RECT  127.613 26.064 127.901 26.088 ;
     RECT  126.904 43.584 127.933 47.64 ;
     RECT  127.708 31.92 127.973 31.992 ;
     RECT  127.721 38.688 128.053 42.216 ;
     RECT  127.933 43.248 128.053 47.64 ;
     RECT  126.904 84.816 128.405 84.84 ;
     RECT  127.708 27.072 128.579 30.84 ;
     RECT  128.053 38.688 128.581 47.64 ;
     RECT  127.721 32.976 128.761 37.464 ;
     RECT  126.904 51.504 128.869 51.528 ;
     RECT  127.973 31.92 128.941 31.944 ;
     RECT  128.761 32.976 128.981 37.656 ;
     RECT  128.869 50.592 128.981 51.528 ;
     RECT  127.613 14.688 129.053 24.216 ;
     RECT  129.053 19.248 129.059 24.216 ;
     RECT  129.053 14.688 129.155 18.024 ;
     RECT  128.579 27.072 129.625 30.6 ;
     RECT  126.904 13.344 129.731 13.368 ;
     RECT  129.625 27.024 129.836 30.6 ;
     RECT  129.836 26.736 129.877 30.6 ;
     RECT  128.941 31.824 129.877 31.944 ;
     RECT  128.981 33.552 129.913 37.656 ;
     RECT  128.581 38.688 129.913 48.216 ;
     RECT  129.913 33.552 129.949 48.216 ;
     RECT  129.949 33.552 129.985 48.408 ;
     RECT  126.904 49.584 130.076 49.608 ;
     RECT  129.877 26.736 130.129 31.944 ;
     RECT  129.985 32.976 130.129 48.408 ;
     RECT  130.076 49.584 130.163 49.704 ;
     RECT  128.981 51.504 130.165 51.528 ;
     RECT  130.129 26.736 130.273 48.408 ;
     RECT  130.273 26.736 130.381 48.456 ;
     RECT  129.059 19.296 130.385 24.216 ;
     RECT  130.165 51.168 130.417 51.528 ;
     RECT  130.381 26.544 130.453 48.456 ;
     RECT  130.453 26.544 130.529 49.368 ;
     RECT  130.417 51.168 130.561 51.912 ;
     RECT  130.529 31.728 130.637 49.368 ;
     RECT  130.637 31.728 130.673 32.136 ;
     RECT  130.561 50.832 130.705 52.008 ;
     RECT  130.385 19.344 130.745 24.216 ;
     RECT  130.745 19.344 130.787 21 ;
     RECT  130.705 50.736 130.925 52.008 ;
     RECT  130.637 33.648 130.997 49.368 ;
     RECT  130.529 26.544 131.101 30.696 ;
     RECT  129.155 15.312 131.749 18.024 ;
     RECT  130.787 19.344 131.749 20.712 ;
     RECT  131.749 15.312 132.008 20.712 ;
     RECT  130.745 21.984 132.008 24.216 ;
     RECT  131.101 26.304 132.008 30.696 ;
     RECT  130.673 31.728 132.008 31.752 ;
     RECT  130.997 33.648 132.008 47.16 ;
     RECT  130.997 48.192 132.008 49.368 ;
     RECT  130.925 50.832 132.008 52.008 ;
     RECT  126.904 64.992 132.008 67.896 ;
     RECT  126.904 79.728 132.008 79.752 ;
     RECT  132.008 2.148 132.112 86.412 ;
     RECT  132.112 2.418 132.304 86.142 ;
     RECT  132.304 26.304 132.401 28.68 ;
     RECT  132.304 65.232 132.437 66.792 ;
     RECT  132.304 30.816 132.473 36.264 ;
     RECT  132.304 40.848 132.473 42.312 ;
     RECT  132.304 17.424 132.545 17.448 ;
     RECT  132.473 40.896 132.581 42.312 ;
     RECT  132.437 65.664 132.653 66.792 ;
     RECT  132.304 21.984 132.689 23.64 ;
     RECT  132.401 26.784 132.689 28.68 ;
     RECT  132.304 38.736 132.689 39.528 ;
     RECT  132.653 65.664 132.689 66.312 ;
     RECT  132.689 65.664 132.725 65.688 ;
     RECT  132.304 16.368 132.761 16.392 ;
     RECT  132.689 22.176 132.797 23.64 ;
     RECT  132.689 39.264 132.905 39.528 ;
     RECT  132.304 67.872 132.941 67.896 ;
     RECT  132.905 39.264 132.977 39.288 ;
     RECT  132.797 22.176 133.085 22.776 ;
     RECT  133.085 22.176 133.229 22.2 ;
     RECT  132.689 26.928 133.301 28.68 ;
     RECT  132.581 41.04 133.369 42.312 ;
     RECT  132.304 43.344 133.369 51.912 ;
     RECT  133.301 26.928 133.445 28.248 ;
     RECT  132.473 30.816 133.477 36.216 ;
     RECT  133.445 27.12 133.553 28.248 ;
     RECT  132.304 20.496 133.805 20.52 ;
     RECT  133.369 41.04 133.909 51.912 ;
     RECT  133.477 30.816 133.945 36.36 ;
     RECT  132.304 37.392 133.945 37.464 ;
     RECT  133.553 28.224 134.305 28.248 ;
     RECT  132.304 29.76 134.305 29.784 ;
     RECT  133.945 30.816 134.305 37.464 ;
     RECT  134.305 28.224 134.341 37.464 ;
     RECT  133.553 27.12 134.417 27.144 ;
     RECT  133.909 40.464 134.449 51.96 ;
     RECT  134.449 40.08 134.629 51.96 ;
     RECT  134.629 40.08 134.701 52.296 ;
     RECT  134.341 28.224 134.737 37.608 ;
     RECT  134.413 21.792 134.845 21.816 ;
     RECT  134.377 38.736 134.845 38.76 ;
     RECT  134.701 40.032 134.845 52.296 ;
     RECT  134.845 21.792 134.917 22.296 ;
     RECT  134.737 28.224 134.989 37.704 ;
     RECT  134.845 38.736 134.989 52.296 ;
     RECT  134.917 21.648 135.025 22.296 ;
     RECT  135.025 21.648 135.205 23.016 ;
     RECT  134.989 28.128 135.277 52.296 ;
     RECT  135.241 26.736 135.385 26.76 ;
     RECT  135.277 27.84 135.385 52.296 ;
     RECT  135.205 21.264 135.637 23.016 ;
     RECT  135.637 21.168 135.785 23.016 ;
     RECT  135.785 21.168 137.408 22.776 ;
     RECT  135.385 26.736 137.408 52.296 ;
     RECT  137.408 2.148 137.512 86.412 ;
     RECT  137.512 2.418 137.704 86.142 ;
     RECT  137.704 26.064 137.729 52.056 ;
     RECT  137.729 26.064 137.765 51.96 ;
     RECT  137.765 26.064 138.089 51.336 ;
     RECT  138.089 39.504 139.093 51.336 ;
     RECT  138.089 26.064 139.597 38.184 ;
     RECT  139.093 39.312 139.597 51.336 ;
     RECT  137.704 20.016 139.633 23.016 ;
     RECT  139.633 19.92 140.364 23.016 ;
     RECT  139.597 26.064 140.364 51.336 ;
    LAYER M5 ;
     RECT  2.4 2.137 2.52 2.151 ;
     RECT  7.8 2.137 7.92 2.151 ;
     RECT  13.2 2.137 13.32 2.151 ;
     RECT  18.6 2.137 18.72 2.151 ;
     RECT  24 2.137 24.12 2.151 ;
     RECT  29.4 2.137 29.52 2.151 ;
     RECT  34.8 2.137 34.92 2.151 ;
     RECT  40.2 2.137 40.32 2.151 ;
     RECT  45.6 2.137 45.72 2.151 ;
     RECT  51 2.137 51.12 2.151 ;
     RECT  56.4 2.137 56.52 2.151 ;
     RECT  61.8 2.137 61.92 2.151 ;
     RECT  67.2 2.137 67.32 2.151 ;
     RECT  72.6 2.137 72.72 2.151 ;
     RECT  78 2.137 78.12 2.151 ;
     RECT  83.4 2.137 83.52 2.151 ;
     RECT  88.8 2.137 88.92 2.151 ;
     RECT  94.2 2.137 94.32 2.151 ;
     RECT  99.6 2.137 99.72 2.151 ;
     RECT  105 2.137 105.12 2.151 ;
     RECT  110.4 2.137 110.52 2.151 ;
     RECT  115.8 2.137 115.92 2.151 ;
     RECT  121.2 2.137 121.32 2.151 ;
     RECT  126.6 2.137 126.72 2.151 ;
     RECT  132 2.137 132.12 2.151 ;
     RECT  137.4 2.137 137.52 2.151 ;
     RECT  9.36 9.493 9.384 10.021 ;
     RECT  121.2 2.151 121.512 10.117 ;
     RECT  118.8 9.493 118.824 10.309 ;
     RECT  13.2 2.151 13.512 10.357 ;
     RECT  118.8 10.309 118.968 10.357 ;
     RECT  9.36 10.021 9.768 10.597 ;
     RECT  121.2 10.117 121.608 10.597 ;
     RECT  9.36 10.597 10.2 10.645 ;
     RECT  120.864 10.597 121.608 10.645 ;
     RECT  9.36 10.645 10.296 10.693 ;
     RECT  118.8 10.357 119.832 10.693 ;
     RECT  120.864 10.645 121.656 10.693 ;
     RECT  118.8 10.693 121.656 10.885 ;
     RECT  18.6 2.151 18.912 10.981 ;
     RECT  122.928 10.597 122.952 10.981 ;
     RECT  118.224 10.885 121.656 11.125 ;
     RECT  18.6 10.981 19.128 11.173 ;
     RECT  115.8 2.151 116.112 11.173 ;
     RECT  122.928 10.981 123.048 11.173 ;
     RECT  22.8 11.077 22.824 11.219 ;
     RECT  30.768 11.077 30.792 11.219 ;
     RECT  115.8 11.173 116.904 11.221 ;
     RECT  12.384 10.357 13.512 11.317 ;
     RECT  115.8 11.221 117.096 11.317 ;
     RECT  17.712 11.173 19.128 11.365 ;
     RECT  9.312 10.693 10.296 11.509 ;
     RECT  115.8 11.317 117.144 11.749 ;
     RECT  118.224 11.125 121.848 11.749 ;
     RECT  9.312 11.509 10.728 11.941 ;
     RECT  115.8 11.749 121.848 11.941 ;
     RECT  122.928 11.173 123.384 11.941 ;
     RECT  12.384 11.317 13.656 12.037 ;
     RECT  9.312 11.941 11.064 12.229 ;
     RECT  12.336 12.037 13.656 12.229 ;
     RECT  17.712 11.365 19.752 12.469 ;
     RECT  26.736 12.277 26.76 12.515 ;
     RECT  9.312 12.229 13.656 12.997 ;
     RECT  114.576 13.141 114.6 13.333 ;
     RECT  114.576 13.333 114.696 13.379 ;
     RECT  7.8 2.151 8.112 13.381 ;
     RECT  9.312 12.997 14.04 13.381 ;
     RECT  114.672 13.379 114.696 13.619 ;
     RECT  7.8 13.381 14.04 13.621 ;
     RECT  7.536 13.621 14.04 14.101 ;
     RECT  15.984 10.453 16.008 14.437 ;
     RECT  15.984 14.437 16.152 14.677 ;
     RECT  129.696 13.333 129.72 14.677 ;
     RECT  126.6 2.151 126.912 14.965 ;
     RECT  7.344 14.101 14.04 15.013 ;
     RECT  7.344 15.013 14.664 15.299 ;
     RECT  15.984 14.677 16.584 15.541 ;
     RECT  42.72 15.445 42.744 15.827 ;
     RECT  129.12 14.677 129.72 16.021 ;
     RECT  17.712 12.469 20.424 16.357 ;
     RECT  21.888 16.021 21.912 16.357 ;
     RECT  132 2.151 132.312 16.885 ;
     RECT  17.712 16.357 21.912 17.317 ;
     RECT  129.12 16.021 130.152 17.365 ;
     RECT  129.12 17.365 130.392 17.941 ;
     RECT  15.312 15.541 16.584 18.133 ;
     RECT  112.848 19.189 112.872 19.237 ;
     RECT  112.848 19.237 112.968 19.379 ;
     RECT  17.712 17.317 21.96 19.477 ;
     RECT  124.56 17.173 124.584 19.525 ;
     RECT  2.4 2.151 2.712 19.813 ;
     RECT  2.4 19.813 3.24 19.909 ;
     RECT  6.336 13.573 6.36 19.909 ;
     RECT  17.712 19.477 22.2 20.005 ;
     RECT  17.712 20.005 22.728 20.053 ;
     RECT  15.312 18.133 16.632 20.149 ;
     RECT  17.712 20.053 22.824 20.149 ;
     RECT  125.808 14.965 126.912 20.341 ;
     RECT  15.312 20.149 22.824 20.387 ;
     RECT  112.896 19.379 112.92 20.387 ;
     RECT  15.312 20.387 22.728 20.677 ;
     RECT  128.928 17.941 130.392 20.965 ;
     RECT  131.376 16.885 132.312 20.965 ;
     RECT  2.304 19.909 4.392 21.155 ;
     RECT  15.168 20.677 22.728 21.155 ;
     RECT  5.376 19.909 6.36 21.205 ;
     RECT  15.168 21.155 22.584 21.395 ;
     RECT  24 2.151 24.312 21.445 ;
     RECT  4.464 21.205 6.36 21.637 ;
     RECT  7.344 15.299 14.04 21.637 ;
     RECT  124.512 19.525 124.584 21.781 ;
     RECT  125.568 20.341 126.912 21.781 ;
     RECT  124.512 21.781 126.912 21.973 ;
     RECT  124.512 21.973 127.56 22.019 ;
     RECT  2.304 21.155 3.384 22.259 ;
     RECT  4.464 21.637 14.04 22.501 ;
     RECT  15.168 21.395 22.2 22.501 ;
     RECT  0.528 21.973 0.552 22.597 ;
     RECT  2.4 22.259 3.384 22.741 ;
     RECT  24 21.445 24.504 23.315 ;
     RECT  2.4 22.741 3.432 23.317 ;
     RECT  128.928 20.965 132.312 23.317 ;
     RECT  125.568 22.019 127.56 23.557 ;
     RECT  128.928 23.317 132.408 23.557 ;
     RECT  0.144 22.597 0.552 23.603 ;
     RECT  2.304 23.317 3.432 23.651 ;
     RECT  115.8 11.941 123.384 23.651 ;
     RECT  4.464 22.501 22.2 23.701 ;
     RECT  0.144 23.603 0.312 23.987 ;
     RECT  0.144 23.987 0.264 24.179 ;
     RECT  3.84 23.701 22.2 24.563 ;
     RECT  117.36 23.651 123.384 24.563 ;
     RECT  117.408 24.563 123.384 24.755 ;
     RECT  2.304 23.651 2.856 24.901 ;
     RECT  3.84 24.563 22.104 24.901 ;
     RECT  0.144 24.179 0.216 25.427 ;
     RECT  117.504 24.755 123.384 25.523 ;
     RECT  2.304 24.901 22.104 25.763 ;
     RECT  0.144 25.427 0.168 25.859 ;
     RECT  0.192 26.533 0.216 26.723 ;
     RECT  2.4 25.763 22.104 26.819 ;
     RECT  4.464 26.819 22.104 26.867 ;
     RECT  117.6 25.523 123.384 27.347 ;
     RECT  2.4 26.819 2.904 27.971 ;
     RECT  4.512 26.867 22.104 27.971 ;
     RECT  117.648 27.347 123.384 29.747 ;
     RECT  5.376 27.971 22.104 30.275 ;
     RECT  117.696 29.747 123.384 30.323 ;
     RECT  137.4 2.151 137.712 30.373 ;
     RECT  137.184 30.373 137.712 30.515 ;
     RECT  6.768 30.275 22.104 30.757 ;
     RECT  6.768 30.757 22.248 30.949 ;
     RECT  6.768 30.949 22.344 31.139 ;
     RECT  5.376 30.275 5.4 31.237 ;
     RECT  5.376 31.237 5.688 31.285 ;
     RECT  137.4 30.515 137.712 32.005 ;
     RECT  117.744 30.323 123.384 32.051 ;
     RECT  137.4 32.005 138.504 32.339 ;
     RECT  125.568 23.557 132.408 32.531 ;
     RECT  5.088 31.285 5.688 32.533 ;
     RECT  6.768 31.139 22.008 32.533 ;
     RECT  5.088 32.533 22.008 32.771 ;
     RECT  5.376 32.771 22.008 33.253 ;
     RECT  5.376 33.253 22.392 33.443 ;
     RECT  5.376 33.443 22.008 33.683 ;
     RECT  5.376 33.683 6.792 33.827 ;
     RECT  7.8 33.683 22.008 33.827 ;
     RECT  117.84 32.051 123.384 34.115 ;
     RECT  134.544 34.021 134.568 34.211 ;
     RECT  137.4 32.339 137.712 34.501 ;
     RECT  7.8 33.827 21.528 34.739 ;
     RECT  136.464 34.501 137.712 34.787 ;
     RECT  7.8 34.739 21.432 35.363 ;
     RECT  118.224 34.115 123.384 35.987 ;
     RECT  9.312 35.363 21.432 36.515 ;
     RECT  125.952 32.531 132.408 36.563 ;
     RECT  118.416 35.987 123.384 36.611 ;
     RECT  118.416 36.611 123.096 36.851 ;
     RECT  2.4 27.971 2.712 36.997 ;
     RECT  13.2 36.515 21.432 37.091 ;
     RECT  126.6 36.563 132.408 37.091 ;
     RECT  118.416 36.851 123 37.187 ;
     RECT  124.512 22.019 124.584 37.475 ;
     RECT  139.008 37.285 139.032 37.475 ;
     RECT  6.768 33.827 6.792 38.099 ;
     RECT  2.4 36.997 3.384 38.149 ;
     RECT  7.8 35.363 8.112 38.149 ;
     RECT  2.4 38.149 3.96 38.243 ;
     RECT  13.2 37.091 13.512 38.437 ;
     RECT  7.8 38.149 8.664 38.483 ;
     RECT  3.936 38.243 3.96 38.725 ;
     RECT  5.376 33.827 5.4 38.725 ;
     RECT  126.6 37.091 130.776 38.819 ;
     RECT  3.936 38.725 5.4 39.395 ;
     RECT  14.784 37.091 21.432 39.395 ;
     RECT  4.512 39.395 5.4 39.443 ;
     RECT  118.848 37.187 123 39.443 ;
     RECT  118.848 39.443 122.904 39.491 ;
     RECT  16.176 39.395 21.432 39.923 ;
     RECT  126.6 38.819 129.336 39.971 ;
     RECT  118.848 39.491 122.856 40.067 ;
     RECT  124.512 37.475 124.536 40.115 ;
     RECT  118.848 40.067 122.28 40.163 ;
     RECT  14.784 39.395 15.192 40.499 ;
     RECT  118.848 40.163 119.352 40.837 ;
     RECT  13.2 38.437 13.608 40.981 ;
     RECT  14.784 40.499 14.808 40.981 ;
     RECT  16.272 39.923 21.432 41.123 ;
     RECT  137.4 34.787 137.712 41.221 ;
     RECT  17.568 41.123 21.432 41.651 ;
     RECT  130.32 38.819 130.776 41.651 ;
     RECT  120.528 40.163 122.28 41.747 ;
     RECT  118.224 40.837 119.352 41.795 ;
     RECT  118.224 41.795 119.256 41.891 ;
     RECT  118.224 41.891 118.872 41.893 ;
     RECT  16.272 41.123 16.536 42.085 ;
     RECT  17.568 41.651 19.656 42.085 ;
     RECT  137.28 41.221 137.712 42.131 ;
     RECT  13.2 40.981 14.808 42.133 ;
     RECT  16.272 42.085 19.656 42.133 ;
     RECT  13.2 42.133 19.656 42.227 ;
     RECT  20.784 41.651 20.856 42.227 ;
     RECT  126.6 39.971 128.088 42.227 ;
     RECT  121.2 41.747 122.28 42.467 ;
     RECT  132 37.091 132.408 42.661 ;
     RECT  129.312 39.971 129.336 42.803 ;
     RECT  20.784 42.227 20.808 42.851 ;
     RECT  128.064 42.227 128.088 42.851 ;
     RECT  131.616 42.661 132.408 42.995 ;
     RECT  117.744 41.893 118.872 42.997 ;
     RECT  13.2 42.227 14.568 43.043 ;
     RECT  117.648 42.997 118.872 43.573 ;
     RECT  130.32 41.651 130.344 43.619 ;
     RECT  15.696 42.227 19.656 43.861 ;
     RECT  117.36 43.573 118.872 44.725 ;
     RECT  14.544 43.043 14.568 44.965 ;
     RECT  134.544 45.013 134.568 45.203 ;
     RECT  15.696 43.861 20.328 45.541 ;
     RECT  126.6 42.227 126.912 45.973 ;
     RECT  15.696 45.541 20.376 46.117 ;
     RECT  15.696 46.117 20.424 46.645 ;
     RECT  130.176 44.965 130.2 46.645 ;
     RECT  137.4 42.131 137.712 46.837 ;
     RECT  130.128 46.645 130.536 47.027 ;
     RECT  137.184 46.837 137.712 47.123 ;
     RECT  140.208 46.837 140.232 47.123 ;
     RECT  137.28 47.123 137.712 47.555 ;
     RECT  7.8 38.483 8.112 47.845 ;
     RECT  126.384 45.973 126.912 47.939 ;
     RECT  130.128 47.027 130.2 48.421 ;
     RECT  134.16 48.757 134.184 48.995 ;
     RECT  15.696 46.645 20.472 49.237 ;
     RECT  21.984 44.965 22.008 49.237 ;
     RECT  5.376 39.443 5.4 49.381 ;
     RECT  5.376 49.381 5.496 49.429 ;
     RECT  4.512 49.429 5.496 49.477 ;
     RECT  132 42.995 132.408 49.573 ;
     RECT  132 49.573 133.32 49.715 ;
     RECT  2.4 38.243 2.712 49.861 ;
     RECT  2.4 49.861 3.048 49.909 ;
     RECT  7.392 47.845 8.112 50.005 ;
     RECT  2.4 49.909 3.144 50.101 ;
     RECT  4.176 49.477 5.544 50.101 ;
     RECT  0.144 50.053 0.168 50.389 ;
     RECT  2.4 50.101 5.928 50.533 ;
     RECT  6.912 50.005 8.112 50.533 ;
     RECT  132 49.715 132.6 50.579 ;
     RECT  0.144 50.389 0.216 51.205 ;
     RECT  128.88 50.581 128.904 51.539 ;
     RECT  0.144 51.205 0.312 52.789 ;
     RECT  0.144 52.789 0.552 52.883 ;
     RECT  0.192 52.883 0.552 53.171 ;
     RECT  0.192 53.171 0.312 53.459 ;
     RECT  0.24 53.459 0.312 54.035 ;
     RECT  0.24 54.035 0.264 54.901 ;
     RECT  0.144 54.901 0.264 55.331 ;
     RECT  2.4 50.533 8.112 55.955 ;
     RECT  0.144 55.331 0.216 56.003 ;
     RECT  2.4 55.955 5.592 57.013 ;
     RECT  6.864 55.955 8.112 57.013 ;
     RECT  0.144 56.003 0.168 57.059 ;
     RECT  2.4 57.013 8.112 57.059 ;
     RECT  0.288 57.445 0.312 57.925 ;
     RECT  0.288 57.925 0.36 58.021 ;
     RECT  2.4 57.059 6.552 58.163 ;
     RECT  0.144 58.021 0.36 58.165 ;
     RECT  0.144 58.165 0.408 58.451 ;
     RECT  6.528 58.163 6.552 58.981 ;
     RECT  7.8 57.059 8.112 58.981 ;
     RECT  0.144 58.451 0.36 59.027 ;
     RECT  2.4 58.163 5.496 60.037 ;
     RECT  6.528 58.981 8.112 60.037 ;
     RECT  0.144 59.027 0.168 60.275 ;
     RECT  0.144 61.909 0.168 62.099 ;
     RECT  2.4 60.037 8.112 62.243 ;
     RECT  2.4 62.243 6.552 63.395 ;
     RECT  4.512 63.395 5.112 63.875 ;
     RECT  4.512 63.875 4.536 63.971 ;
     RECT  6.144 63.395 6.552 63.971 ;
     RECT  2.4 63.395 3.432 64.019 ;
     RECT  15.696 49.237 22.008 64.645 ;
     RECT  14.544 44.965 14.616 64.691 ;
     RECT  40.2 2.151 40.512 65.221 ;
     RECT  40.2 65.221 40.632 65.269 ;
     RECT  24 23.315 24.312 65.365 ;
     RECT  40.2 65.269 40.728 65.413 ;
     RECT  15.696 64.645 22.296 65.747 ;
     RECT  130.128 48.421 130.344 65.795 ;
     RECT  117.36 44.725 119.064 65.843 ;
     RECT  132 50.579 132.408 66.083 ;
     RECT  24 65.365 24.408 66.421 ;
     RECT  117.552 65.843 119.064 66.467 ;
     RECT  23.328 66.421 24.408 66.469 ;
     RECT  25.632 65.845 25.656 66.469 ;
     RECT  45.6 2.151 45.912 66.517 ;
     RECT  21.984 65.747 22.296 66.709 ;
     RECT  40.2 65.413 40.776 66.757 ;
     RECT  21.552 66.709 22.296 66.851 ;
     RECT  48.576 66.805 48.6 66.853 ;
     RECT  103.776 65.797 103.8 66.947 ;
     RECT  40.2 66.757 41.064 66.995 ;
     RECT  6.528 63.971 6.552 67.043 ;
     RECT  45.6 66.517 46.008 67.045 ;
     RECT  45.6 67.045 46.2 67.141 ;
     RECT  14.544 64.691 14.568 67.187 ;
     RECT  21.984 66.851 22.296 67.237 ;
     RECT  23.328 66.469 25.656 67.237 ;
     RECT  45.6 67.141 46.296 67.237 ;
     RECT  21.984 67.237 25.656 67.283 ;
     RECT  27.888 65.893 27.912 67.283 ;
     RECT  63.216 23.269 63.24 67.333 ;
     RECT  22.176 67.283 24.408 67.379 ;
     RECT  22.176 67.379 24.312 67.475 ;
     RECT  45.6 67.237 47.256 67.475 ;
     RECT  48.48 66.853 48.6 67.571 ;
     RECT  130.128 65.795 130.2 67.571 ;
     RECT  67.2 2.151 67.512 67.669 ;
     RECT  15.696 65.747 20.52 67.715 ;
     RECT  48.48 67.571 48.504 67.715 ;
     RECT  15.744 67.715 20.52 67.813 ;
     RECT  130.176 67.571 130.2 67.859 ;
     RECT  117.648 66.467 119.064 67.907 ;
     RECT  15.744 67.813 20.952 67.955 ;
     RECT  22.176 67.475 22.2 67.955 ;
     RECT  67.2 67.669 68.424 68.051 ;
     RECT  114.576 67.861 114.6 68.147 ;
     RECT  15.744 67.955 20.328 68.195 ;
     RECT  117.696 67.907 119.064 68.435 ;
     RECT  15.744 68.195 20.088 68.483 ;
     RECT  15.744 68.483 16.632 68.531 ;
     RECT  117.792 68.435 119.064 68.531 ;
     RECT  18.24 68.483 20.088 68.579 ;
     RECT  18.24 68.579 18.912 68.675 ;
     RECT  117.792 68.531 118.872 68.675 ;
     RECT  23.328 67.475 24.312 68.723 ;
     RECT  30.768 67.381 30.792 68.723 ;
     RECT  117.792 68.675 118.632 68.723 ;
     RECT  118.272 68.723 118.632 68.771 ;
     RECT  15.744 68.531 15.768 68.819 ;
     RECT  118.272 68.771 118.296 68.963 ;
     RECT  47.232 67.475 47.256 75.491 ;
     RECT  63.216 67.333 63.528 75.685 ;
     RECT  67.2 68.051 68.088 79.717 ;
     RECT  21.984 80.917 22.008 82.549 ;
     RECT  66.96 79.717 68.088 82.933 ;
     RECT  66.912 82.933 68.088 83.173 ;
     RECT  19.92 68.579 20.088 83.267 ;
     RECT  21.84 82.549 22.008 83.605 ;
     RECT  66.096 83.173 68.088 83.605 ;
     RECT  65.472 83.605 68.088 83.653 ;
     RECT  21.36 83.605 22.344 83.749 ;
     RECT  65.376 83.653 68.088 83.749 ;
     RECT  65.184 83.749 68.088 84.037 ;
     RECT  21.312 83.749 22.344 84.133 ;
     RECT  65.184 84.037 68.376 84.181 ;
     RECT  63.216 75.685 63.72 84.949 ;
     RECT  64.848 84.181 68.376 84.949 ;
     RECT  63.216 84.949 68.376 85.523 ;
     RECT  20.064 83.267 20.088 85.571 ;
     RECT  21.264 84.133 22.344 85.717 ;
     RECT  20.928 85.717 22.344 86.005 ;
     RECT  63.696 85.523 68.376 86.099 ;
     RECT  2.4 64.019 2.712 86.409 ;
     RECT  7.8 62.243 8.112 86.409 ;
     RECT  13.2 43.043 13.512 86.409 ;
     RECT  18.6 68.675 18.912 86.409 ;
     RECT  24 68.723 24.312 86.409 ;
     RECT  29.4 2.151 29.712 86.409 ;
     RECT  34.8 2.151 35.112 86.409 ;
     RECT  40.2 66.995 40.512 86.409 ;
     RECT  45.6 67.475 45.912 86.409 ;
     RECT  51 2.151 51.312 86.409 ;
     RECT  56.4 2.151 56.712 86.409 ;
     RECT  61.8 2.151 62.112 86.409 ;
     RECT  63.696 86.099 67.512 86.409 ;
     RECT  72.6 2.151 72.912 86.409 ;
     RECT  78 2.151 78.312 86.409 ;
     RECT  83.4 2.151 83.712 86.409 ;
     RECT  88.8 2.151 89.112 86.409 ;
     RECT  94.2 2.151 94.512 86.409 ;
     RECT  99.6 2.151 99.912 86.409 ;
     RECT  105 2.151 105.312 86.409 ;
     RECT  110.4 2.151 110.712 86.409 ;
     RECT  115.8 23.651 116.112 86.409 ;
     RECT  121.2 42.467 121.512 86.409 ;
     RECT  126.6 47.939 126.912 86.409 ;
     RECT  132 66.083 132.312 86.409 ;
     RECT  137.4 47.555 137.712 86.409 ;
     RECT  2.4 86.409 2.52 86.423 ;
     RECT  7.8 86.409 7.92 86.423 ;
     RECT  13.2 86.409 13.32 86.423 ;
     RECT  18.6 86.409 18.72 86.423 ;
     RECT  24 86.409 24.12 86.423 ;
     RECT  29.4 86.409 29.52 86.423 ;
     RECT  34.8 86.409 34.92 86.423 ;
     RECT  40.2 86.409 40.32 86.423 ;
     RECT  45.6 86.409 45.72 86.423 ;
     RECT  51 86.409 51.12 86.423 ;
     RECT  56.4 86.409 56.52 86.423 ;
     RECT  61.8 86.409 61.92 86.423 ;
     RECT  63.696 86.409 67.32 86.423 ;
     RECT  72.6 86.409 72.72 86.423 ;
     RECT  78 86.409 78.12 86.423 ;
     RECT  83.4 86.409 83.52 86.423 ;
     RECT  88.8 86.409 88.92 86.423 ;
     RECT  94.2 86.409 94.32 86.423 ;
     RECT  99.6 86.409 99.72 86.423 ;
     RECT  105 86.409 105.12 86.423 ;
     RECT  110.4 86.409 110.52 86.423 ;
     RECT  115.8 86.409 115.92 86.423 ;
     RECT  121.2 86.409 121.32 86.423 ;
     RECT  126.6 86.409 126.72 86.423 ;
     RECT  132 86.409 132.12 86.423 ;
     RECT  137.4 86.409 137.52 86.423 ;
     RECT  20.928 86.005 22.44 86.437 ;
     RECT  20.928 86.437 22.536 86.533 ;
     RECT  20.928 86.533 22.632 86.581 ;
     RECT  20.688 86.581 22.632 88.451 ;
     RECT  20.88 88.451 22.632 88.528 ;
     RECT  63.696 86.423 66.696 88.528 ;
     RECT  8.112 9.493 9.36 10.693 ;
     RECT  119.832 10.357 121.2 10.597 ;
     RECT  119.832 10.597 120.864 10.693 ;
     RECT  121.608 10.597 122.928 10.645 ;
     RECT  121.656 10.645 122.928 11.125 ;
     RECT  8.112 10.693 9.312 13.381 ;
     RECT  22.824 11.077 24 11.219 ;
     RECT  29.712 11.077 30.768 11.219 ;
     RECT  121.848 11.125 122.928 11.941 ;
     RECT  116.904 11.173 118.224 11.221 ;
     RECT  117.096 11.221 118.224 11.317 ;
     RECT  117.144 11.317 118.224 11.749 ;
     RECT  11.064 11.941 12.384 12.037 ;
     RECT  11.064 12.037 12.336 12.229 ;
     RECT  114.6 13.141 115.8 13.333 ;
     RECT  114.696 13.333 115.8 13.619 ;
     RECT  6.36 13.573 7.8 13.621 ;
     RECT  6.36 13.621 7.536 14.101 ;
     RECT  6.36 14.101 7.344 21.637 ;
     RECT  16.584 14.677 17.712 18.133 ;
     RECT  14.664 15.013 15.984 15.299 ;
     RECT  14.04 15.299 15.984 15.541 ;
     RECT  14.04 15.541 15.312 20.677 ;
     RECT  20.424 16.021 21.888 16.357 ;
     RECT  130.152 16.885 131.376 17.365 ;
     RECT  123.384 17.173 124.56 19.525 ;
     RECT  124.584 17.173 125.808 20.341 ;
     RECT  130.392 17.365 131.376 20.965 ;
     RECT  16.632 18.133 17.712 20.149 ;
     RECT  123.384 19.525 124.512 36.611 ;
     RECT  4.392 19.909 5.376 21.155 ;
     RECT  22.728 20.005 24 20.053 ;
     RECT  22.824 20.053 24 20.387 ;
     RECT  124.584 20.341 125.568 21.781 ;
     RECT  22.728 20.387 24 21.155 ;
     RECT  14.04 20.677 15.168 22.501 ;
     RECT  3.384 21.155 5.376 21.205 ;
     RECT  22.584 21.155 24 21.395 ;
     RECT  3.384 21.205 4.464 22.741 ;
     RECT  127.56 21.973 128.928 23.557 ;
     RECT  124.584 22.019 125.568 32.531 ;
     RECT  2.304 22.259 2.4 23.317 ;
     RECT  3.432 22.741 4.464 23.651 ;
     RECT  62.112 23.269 63.216 85.523 ;
     RECT  2.856 23.651 4.464 23.701 ;
     RECT  116.112 23.651 117.36 24.563 ;
     RECT  2.856 23.701 3.84 24.901 ;
     RECT  116.112 24.563 117.408 24.755 ;
     RECT  116.112 24.755 117.504 25.523 ;
     RECT  0.168 25.427 0.216 25.859 ;
     RECT  116.112 25.523 117.6 27.347 ;
     RECT  0.192 25.859 0.216 26.533 ;
     RECT  5.4 30.275 6.768 31.237 ;
     RECT  5.688 31.237 6.768 32.533 ;
     RECT  124.584 32.531 125.952 36.563 ;
     RECT  6.792 33.683 7.8 38.099 ;
     RECT  5.4 33.827 6.768 38.099 ;
     RECT  8.112 35.363 9.312 36.515 ;
     RECT  123.096 36.611 124.512 36.851 ;
     RECT  123 36.851 124.512 39.443 ;
     RECT  13.512 37.091 14.784 38.437 ;
     RECT  130.776 37.091 132 41.651 ;
     RECT  137.712 37.285 139.008 37.475 ;
     RECT  3.96 38.149 5.376 38.725 ;
     RECT  2.712 38.243 3.936 39.395 ;
     RECT  13.608 38.437 14.784 40.981 ;
     RECT  129.336 38.819 130.32 42.803 ;
     RECT  15.192 39.395 16.176 39.923 ;
     RECT  15.192 39.923 16.272 40.499 ;
     RECT  128.088 39.971 129.312 42.803 ;
     RECT  119.352 40.163 120.528 41.747 ;
     RECT  14.808 40.499 16.272 42.133 ;
     RECT  16.536 41.123 17.568 42.085 ;
     RECT  19.656 41.651 20.784 42.851 ;
     RECT  130.344 41.651 132 42.661 ;
     RECT  14.568 42.227 15.696 44.965 ;
     RECT  126.912 42.227 128.064 42.851 ;
     RECT  130.344 42.661 131.616 42.995 ;
     RECT  19.656 42.851 20.328 43.861 ;
     RECT  13.512 43.043 14.544 67.187 ;
     RECT  116.112 43.573 117.36 65.843 ;
     RECT  14.616 44.965 15.696 64.691 ;
     RECT  20.472 46.645 21.984 49.237 ;
     RECT  130.536 46.645 132 47.027 ;
     RECT  130.2 47.027 130.344 48.421 ;
     RECT  2.712 49.477 4.176 49.861 ;
     RECT  3.048 49.861 4.176 49.909 ;
     RECT  3.144 49.909 4.176 50.101 ;
     RECT  5.544 50.005 6.912 50.101 ;
     RECT  5.928 50.101 6.912 50.533 ;
     RECT  128.904 50.581 130.128 51.539 ;
     RECT  0.192 53.459 0.24 54.901 ;
     RECT  5.592 55.955 6.864 57.013 ;
     RECT  0.168 56.003 0.216 57.059 ;
     RECT  0.144 57.059 0.216 57.445 ;
     RECT  6.552 57.059 7.8 58.981 ;
     RECT  0.144 57.445 0.288 58.021 ;
     RECT  5.496 58.163 6.528 60.037 ;
     RECT  6.552 62.243 7.8 67.043 ;
     RECT  3.432 63.395 4.512 63.971 ;
     RECT  5.112 63.395 6.144 63.875 ;
     RECT  14.568 64.691 15.696 67.187 ;
     RECT  20.52 65.747 21.984 66.709 ;
     RECT  103.8 65.797 105 66.947 ;
     RECT  116.112 65.843 117.552 66.467 ;
     RECT  24.408 65.845 25.632 66.469 ;
     RECT  27.912 65.893 29.4 67.283 ;
     RECT  22.296 66.421 23.328 67.237 ;
     RECT  20.52 66.709 21.552 66.851 ;
     RECT  20.52 66.851 21.984 67.283 ;
     RECT  47.256 67.237 48.48 67.715 ;
     RECT  20.52 67.283 22.176 67.813 ;
     RECT  29.712 67.381 30.768 68.723 ;
     RECT  22.2 67.475 23.328 67.955 ;
     RECT  45.912 67.475 47.232 75.491 ;
     RECT  20.952 67.813 22.176 67.955 ;
     RECT  114.6 67.861 115.8 68.147 ;
     RECT  18.912 68.579 19.92 83.267 ;
     RECT  18.912 83.267 20.064 85.571 ;
     RECT  20.088 83.605 21.36 83.749 ;
     RECT  20.088 83.749 21.312 84.133 ;
     RECT  63.72 83.749 65.184 84.181 ;
     RECT  20.088 84.133 21.264 85.571 ;
     RECT  63.72 84.181 64.848 84.949 ;
     RECT  20.688 85.571 21.264 85.717 ;
     RECT  20.688 85.717 20.928 86.581 ;
  END
END ot_hgi_dma_back_landing_bank
END LIBRARY
